VERSION 5.8 ;
BUSBITCHARS "[]" ;
DIVIDERCHAR "/" ;
UNITS
    DATABASE MICRONS 1000 ;
END UNITS

VIA ino_decode_predict_via1_2_1000_440_1_2_410_410
  VIARULE via1Array ;
  CUTSIZE 0.19 0.19 ;
  LAYERS Metal1 Via1 Metal2 ;
  CUTSPACING 0.22 0.22 ;
  ENCLOSURE 0.05 0.125 0.005 0.05 ;
  ROWCOL 1 2 ;
END ino_decode_predict_via1_2_1000_440_1_2_410_410

VIA ino_decode_predict_via2_3_1000_440_1_2_410_410
  VIARULE via2Array ;
  CUTSIZE 0.19 0.19 ;
  LAYERS Metal2 Via2 Metal3 ;
  CUTSPACING 0.22 0.22 ;
  ENCLOSURE 0.005 0.05 0.05 0.005 ;
  ROWCOL 1 2 ;
END ino_decode_predict_via2_3_1000_440_1_2_410_410

VIA ino_decode_predict_via3_4_1000_440_1_2_410_410
  VIARULE via3Array ;
  CUTSIZE 0.19 0.19 ;
  LAYERS Metal3 Via3 Metal4 ;
  CUTSPACING 0.22 0.22 ;
  ENCLOSURE 0.05 0.005 0.2 0.05 ;
  ROWCOL 1 2 ;
END ino_decode_predict_via3_4_1000_440_1_2_410_410

VIA ino_decode_predict_via4_5_1000_2000_1_1_840_840
  VIARULE viaTop1Array ;
  CUTSIZE 0.42 0.42 ;
  LAYERS Metal4 TopVia1 TopMetal1 ;
  CUTSPACING 0.42 0.42 ;
  ENCLOSURE 0.29 0.1 0.42 0.79 ;
END ino_decode_predict_via4_5_1000_2000_1_1_840_840

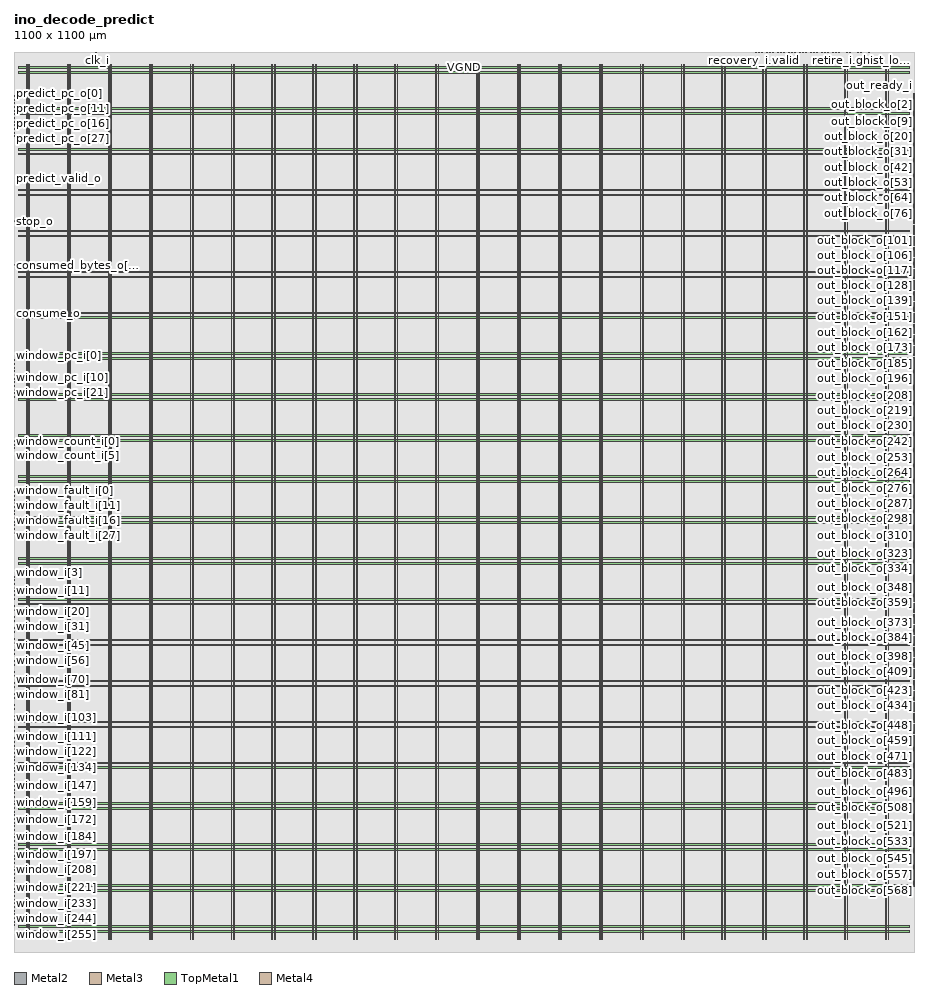
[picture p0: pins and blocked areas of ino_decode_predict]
MACRO ino_decode_predict
  FOREIGN ino_decode_predict 0 0 ;
  CLASS BLOCK ;
  SIZE 1100 BY 1100 ;
  PIN clk_i
    DIRECTION INPUT ;
    USE SIGNAL ;
    PORT
      LAYER Metal2 ;
        RECT  102.04 1099.6 102.44 1100 ;
    END
  END clk_i
  PIN consume_o
    DIRECTION OUTPUT ;
    USE SIGNAL ;
    PORT
      LAYER Metal3 ;
        RECT  0 780.58 0.4 780.98 ;
    END
  END consume_o
  PIN consumed_bytes_o[0]
    DIRECTION OUTPUT ;
    USE SIGNAL ;
    PORT
      LAYER Metal3 ;
        RECT  0 841.06 0.4 841.46 ;
    END
  END consumed_bytes_o[0]
  PIN consumed_bytes_o[1]
    DIRECTION OUTPUT ;
    USE SIGNAL ;
    PORT
      LAYER Metal3 ;
        RECT  0 839.38 0.4 839.78 ;
    END
  END consumed_bytes_o[1]
  PIN consumed_bytes_o[2]
    DIRECTION OUTPUT ;
    USE SIGNAL ;
    PORT
      LAYER Metal3 ;
        RECT  0 837.7 0.4 838.1 ;
    END
  END consumed_bytes_o[2]
  PIN consumed_bytes_o[3]
    DIRECTION OUTPUT ;
    USE SIGNAL ;
    PORT
      LAYER Metal3 ;
        RECT  0 836.02 0.4 836.42 ;
    END
  END consumed_bytes_o[3]
  PIN consumed_bytes_o[4]
    DIRECTION OUTPUT ;
    USE SIGNAL ;
    PORT
      LAYER Metal3 ;
        RECT  0 834.34 0.4 834.74 ;
    END
  END consumed_bytes_o[4]
  PIN consumed_bytes_o[5]
    DIRECTION OUTPUT ;
    USE SIGNAL ;
    PORT
      LAYER Metal3 ;
        RECT  0 832.66 0.4 833.06 ;
    END
  END consumed_bytes_o[5]
  PIN out_block_o[0]
    DIRECTION OUTPUT ;
    USE SIGNAL ;
    PORT
      LAYER Metal3 ;
        RECT  1099.6 1039.3 1100 1039.7 ;
    END
  END out_block_o[0]
  PIN out_block_o[100]
    DIRECTION OUTPUT ;
    USE SIGNAL ;
    PORT
      LAYER Metal3 ;
        RECT  1099.6 871.3 1100 871.7 ;
    END
  END out_block_o[100]
  PIN out_block_o[101]
    DIRECTION OUTPUT ;
    USE SIGNAL ;
    PORT
      LAYER Metal3 ;
        RECT  1099.6 869.62 1100 870.02 ;
    END
  END out_block_o[101]
  PIN out_block_o[102]
    DIRECTION OUTPUT ;
    USE SIGNAL ;
    PORT
      LAYER Metal3 ;
        RECT  1099.6 867.94 1100 868.34 ;
    END
  END out_block_o[102]
  PIN out_block_o[103]
    DIRECTION OUTPUT ;
    USE SIGNAL ;
    PORT
      LAYER Metal3 ;
        RECT  1099.6 866.26 1100 866.66 ;
    END
  END out_block_o[103]
  PIN out_block_o[104]
    DIRECTION OUTPUT ;
    USE SIGNAL ;
    PORT
      LAYER Metal3 ;
        RECT  1099.6 864.58 1100 864.98 ;
    END
  END out_block_o[104]
  PIN out_block_o[105]
    DIRECTION OUTPUT ;
    USE SIGNAL ;
    PORT
      LAYER Metal3 ;
        RECT  1099.6 862.9 1100 863.3 ;
    END
  END out_block_o[105]
  PIN out_block_o[106]
    DIRECTION OUTPUT ;
    USE SIGNAL ;
    PORT
      LAYER Metal3 ;
        RECT  1099.6 861.22 1100 861.62 ;
    END
  END out_block_o[106]
  PIN out_block_o[107]
    DIRECTION OUTPUT ;
    USE SIGNAL ;
    PORT
      LAYER Metal3 ;
        RECT  1099.6 859.54 1100 859.94 ;
    END
  END out_block_o[107]
  PIN out_block_o[108]
    DIRECTION OUTPUT ;
    USE SIGNAL ;
    PORT
      LAYER Metal3 ;
        RECT  1099.6 857.86 1100 858.26 ;
    END
  END out_block_o[108]
  PIN out_block_o[109]
    DIRECTION OUTPUT ;
    USE SIGNAL ;
    PORT
      LAYER Metal3 ;
        RECT  1099.6 856.18 1100 856.58 ;
    END
  END out_block_o[109]
  PIN out_block_o[10]
    DIRECTION OUTPUT ;
    USE SIGNAL ;
    PORT
      LAYER Metal3 ;
        RECT  1099.6 1022.5 1100 1022.9 ;
    END
  END out_block_o[10]
  PIN out_block_o[110]
    DIRECTION OUTPUT ;
    USE SIGNAL ;
    PORT
      LAYER Metal3 ;
        RECT  1099.6 854.5 1100 854.9 ;
    END
  END out_block_o[110]
  PIN out_block_o[111]
    DIRECTION OUTPUT ;
    USE SIGNAL ;
    PORT
      LAYER Metal3 ;
        RECT  1099.6 852.82 1100 853.22 ;
    END
  END out_block_o[111]
  PIN out_block_o[112]
    DIRECTION OUTPUT ;
    USE SIGNAL ;
    PORT
      LAYER Metal3 ;
        RECT  1099.6 851.14 1100 851.54 ;
    END
  END out_block_o[112]
  PIN out_block_o[113]
    DIRECTION OUTPUT ;
    USE SIGNAL ;
    PORT
      LAYER Metal3 ;
        RECT  1099.6 849.46 1100 849.86 ;
    END
  END out_block_o[113]
  PIN out_block_o[114]
    DIRECTION OUTPUT ;
    USE SIGNAL ;
    PORT
      LAYER Metal3 ;
        RECT  1099.6 847.78 1100 848.18 ;
    END
  END out_block_o[114]
  PIN out_block_o[115]
    DIRECTION OUTPUT ;
    USE SIGNAL ;
    PORT
      LAYER Metal3 ;
        RECT  1099.6 846.1 1100 846.5 ;
    END
  END out_block_o[115]
  PIN out_block_o[116]
    DIRECTION OUTPUT ;
    USE SIGNAL ;
    PORT
      LAYER Metal3 ;
        RECT  1099.6 844.42 1100 844.82 ;
    END
  END out_block_o[116]
  PIN out_block_o[117]
    DIRECTION OUTPUT ;
    USE SIGNAL ;
    PORT
      LAYER Metal3 ;
        RECT  1099.6 842.74 1100 843.14 ;
    END
  END out_block_o[117]
  PIN out_block_o[118]
    DIRECTION OUTPUT ;
    USE SIGNAL ;
    PORT
      LAYER Metal3 ;
        RECT  1099.6 841.06 1100 841.46 ;
    END
  END out_block_o[118]
  PIN out_block_o[119]
    DIRECTION OUTPUT ;
    USE SIGNAL ;
    PORT
      LAYER Metal3 ;
        RECT  1099.6 839.38 1100 839.78 ;
    END
  END out_block_o[119]
  PIN out_block_o[11]
    DIRECTION OUTPUT ;
    USE SIGNAL ;
    PORT
      LAYER Metal3 ;
        RECT  1099.6 1020.82 1100 1021.22 ;
    END
  END out_block_o[11]
  PIN out_block_o[120]
    DIRECTION OUTPUT ;
    USE SIGNAL ;
    PORT
      LAYER Metal3 ;
        RECT  1099.6 837.7 1100 838.1 ;
    END
  END out_block_o[120]
  PIN out_block_o[121]
    DIRECTION OUTPUT ;
    USE SIGNAL ;
    PORT
      LAYER Metal3 ;
        RECT  1099.6 836.02 1100 836.42 ;
    END
  END out_block_o[121]
  PIN out_block_o[122]
    DIRECTION OUTPUT ;
    USE SIGNAL ;
    PORT
      LAYER Metal3 ;
        RECT  1099.6 834.34 1100 834.74 ;
    END
  END out_block_o[122]
  PIN out_block_o[123]
    DIRECTION OUTPUT ;
    USE SIGNAL ;
    PORT
      LAYER Metal3 ;
        RECT  1099.6 832.66 1100 833.06 ;
    END
  END out_block_o[123]
  PIN out_block_o[124]
    DIRECTION OUTPUT ;
    USE SIGNAL ;
    PORT
      LAYER Metal3 ;
        RECT  1099.6 830.98 1100 831.38 ;
    END
  END out_block_o[124]
  PIN out_block_o[125]
    DIRECTION OUTPUT ;
    USE SIGNAL ;
    PORT
      LAYER Metal3 ;
        RECT  1099.6 829.3 1100 829.7 ;
    END
  END out_block_o[125]
  PIN out_block_o[126]
    DIRECTION OUTPUT ;
    USE SIGNAL ;
    PORT
      LAYER Metal3 ;
        RECT  1099.6 827.62 1100 828.02 ;
    END
  END out_block_o[126]
  PIN out_block_o[127]
    DIRECTION OUTPUT ;
    USE SIGNAL ;
    PORT
      LAYER Metal3 ;
        RECT  1099.6 825.94 1100 826.34 ;
    END
  END out_block_o[127]
  PIN out_block_o[128]
    DIRECTION OUTPUT ;
    USE SIGNAL ;
    PORT
      LAYER Metal3 ;
        RECT  1099.6 824.26 1100 824.66 ;
    END
  END out_block_o[128]
  PIN out_block_o[129]
    DIRECTION OUTPUT ;
    USE SIGNAL ;
    PORT
      LAYER Metal3 ;
        RECT  1099.6 822.58 1100 822.98 ;
    END
  END out_block_o[129]
  PIN out_block_o[12]
    DIRECTION OUTPUT ;
    USE SIGNAL ;
    PORT
      LAYER Metal3 ;
        RECT  1099.6 1019.14 1100 1019.54 ;
    END
  END out_block_o[12]
  PIN out_block_o[130]
    DIRECTION OUTPUT ;
    USE SIGNAL ;
    PORT
      LAYER Metal3 ;
        RECT  1099.6 820.9 1100 821.3 ;
    END
  END out_block_o[130]
  PIN out_block_o[131]
    DIRECTION OUTPUT ;
    USE SIGNAL ;
    PORT
      LAYER Metal3 ;
        RECT  1099.6 819.22 1100 819.62 ;
    END
  END out_block_o[131]
  PIN out_block_o[132]
    DIRECTION OUTPUT ;
    USE SIGNAL ;
    PORT
      LAYER Metal3 ;
        RECT  1099.6 817.54 1100 817.94 ;
    END
  END out_block_o[132]
  PIN out_block_o[133]
    DIRECTION OUTPUT ;
    USE SIGNAL ;
    PORT
      LAYER Metal3 ;
        RECT  1099.6 815.86 1100 816.26 ;
    END
  END out_block_o[133]
  PIN out_block_o[134]
    DIRECTION OUTPUT ;
    USE SIGNAL ;
    PORT
      LAYER Metal3 ;
        RECT  1099.6 814.18 1100 814.58 ;
    END
  END out_block_o[134]
  PIN out_block_o[135]
    DIRECTION OUTPUT ;
    USE SIGNAL ;
    PORT
      LAYER Metal3 ;
        RECT  1099.6 812.5 1100 812.9 ;
    END
  END out_block_o[135]
  PIN out_block_o[136]
    DIRECTION OUTPUT ;
    USE SIGNAL ;
    PORT
      LAYER Metal3 ;
        RECT  1099.6 810.82 1100 811.22 ;
    END
  END out_block_o[136]
  PIN out_block_o[137]
    DIRECTION OUTPUT ;
    USE SIGNAL ;
    PORT
      LAYER Metal3 ;
        RECT  1099.6 809.14 1100 809.54 ;
    END
  END out_block_o[137]
  PIN out_block_o[138]
    DIRECTION OUTPUT ;
    USE SIGNAL ;
    PORT
      LAYER Metal3 ;
        RECT  1099.6 807.46 1100 807.86 ;
    END
  END out_block_o[138]
  PIN out_block_o[139]
    DIRECTION OUTPUT ;
    USE SIGNAL ;
    PORT
      LAYER Metal3 ;
        RECT  1099.6 805.78 1100 806.18 ;
    END
  END out_block_o[139]
  PIN out_block_o[13]
    DIRECTION OUTPUT ;
    USE SIGNAL ;
    PORT
      LAYER Metal3 ;
        RECT  1099.6 1017.46 1100 1017.86 ;
    END
  END out_block_o[13]
  PIN out_block_o[140]
    DIRECTION OUTPUT ;
    USE SIGNAL ;
    PORT
      LAYER Metal3 ;
        RECT  1099.6 804.1 1100 804.5 ;
    END
  END out_block_o[140]
  PIN out_block_o[141]
    DIRECTION OUTPUT ;
    USE SIGNAL ;
    PORT
      LAYER Metal3 ;
        RECT  1099.6 802.42 1100 802.82 ;
    END
  END out_block_o[141]
  PIN out_block_o[142]
    DIRECTION OUTPUT ;
    USE SIGNAL ;
    PORT
      LAYER Metal3 ;
        RECT  1099.6 800.74 1100 801.14 ;
    END
  END out_block_o[142]
  PIN out_block_o[143]
    DIRECTION OUTPUT ;
    USE SIGNAL ;
    PORT
      LAYER Metal3 ;
        RECT  1099.6 799.06 1100 799.46 ;
    END
  END out_block_o[143]
  PIN out_block_o[144]
    DIRECTION OUTPUT ;
    USE SIGNAL ;
    PORT
      LAYER Metal3 ;
        RECT  1099.6 797.38 1100 797.78 ;
    END
  END out_block_o[144]
  PIN out_block_o[145]
    DIRECTION OUTPUT ;
    USE SIGNAL ;
    PORT
      LAYER Metal3 ;
        RECT  1099.6 795.7 1100 796.1 ;
    END
  END out_block_o[145]
  PIN out_block_o[146]
    DIRECTION OUTPUT ;
    USE SIGNAL ;
    PORT
      LAYER Metal3 ;
        RECT  1099.6 794.02 1100 794.42 ;
    END
  END out_block_o[146]
  PIN out_block_o[147]
    DIRECTION OUTPUT ;
    USE SIGNAL ;
    PORT
      LAYER Metal3 ;
        RECT  1099.6 792.34 1100 792.74 ;
    END
  END out_block_o[147]
  PIN out_block_o[148]
    DIRECTION OUTPUT ;
    USE SIGNAL ;
    PORT
      LAYER Metal3 ;
        RECT  1099.6 790.66 1100 791.06 ;
    END
  END out_block_o[148]
  PIN out_block_o[149]
    DIRECTION OUTPUT ;
    USE SIGNAL ;
    PORT
      LAYER Metal3 ;
        RECT  1099.6 788.98 1100 789.38 ;
    END
  END out_block_o[149]
  PIN out_block_o[14]
    DIRECTION OUTPUT ;
    USE SIGNAL ;
    PORT
      LAYER Metal3 ;
        RECT  1099.6 1015.78 1100 1016.18 ;
    END
  END out_block_o[14]
  PIN out_block_o[150]
    DIRECTION OUTPUT ;
    USE SIGNAL ;
    PORT
      LAYER Metal3 ;
        RECT  1099.6 787.3 1100 787.7 ;
    END
  END out_block_o[150]
  PIN out_block_o[151]
    DIRECTION OUTPUT ;
    USE SIGNAL ;
    PORT
      LAYER Metal3 ;
        RECT  1099.6 785.62 1100 786.02 ;
    END
  END out_block_o[151]
  PIN out_block_o[152]
    DIRECTION OUTPUT ;
    USE SIGNAL ;
    PORT
      LAYER Metal3 ;
        RECT  1099.6 783.94 1100 784.34 ;
    END
  END out_block_o[152]
  PIN out_block_o[153]
    DIRECTION OUTPUT ;
    USE SIGNAL ;
    PORT
      LAYER Metal3 ;
        RECT  1099.6 782.26 1100 782.66 ;
    END
  END out_block_o[153]
  PIN out_block_o[154]
    DIRECTION OUTPUT ;
    USE SIGNAL ;
    PORT
      LAYER Metal3 ;
        RECT  1099.6 780.58 1100 780.98 ;
    END
  END out_block_o[154]
  PIN out_block_o[155]
    DIRECTION OUTPUT ;
    USE SIGNAL ;
    PORT
      LAYER Metal3 ;
        RECT  1099.6 778.9 1100 779.3 ;
    END
  END out_block_o[155]
  PIN out_block_o[156]
    DIRECTION OUTPUT ;
    USE SIGNAL ;
    PORT
      LAYER Metal3 ;
        RECT  1099.6 777.22 1100 777.62 ;
    END
  END out_block_o[156]
  PIN out_block_o[157]
    DIRECTION OUTPUT ;
    USE SIGNAL ;
    PORT
      LAYER Metal3 ;
        RECT  1099.6 775.54 1100 775.94 ;
    END
  END out_block_o[157]
  PIN out_block_o[158]
    DIRECTION OUTPUT ;
    USE SIGNAL ;
    PORT
      LAYER Metal3 ;
        RECT  1099.6 773.86 1100 774.26 ;
    END
  END out_block_o[158]
  PIN out_block_o[159]
    DIRECTION OUTPUT ;
    USE SIGNAL ;
    PORT
      LAYER Metal3 ;
        RECT  1099.6 772.18 1100 772.58 ;
    END
  END out_block_o[159]
  PIN out_block_o[15]
    DIRECTION OUTPUT ;
    USE SIGNAL ;
    PORT
      LAYER Metal3 ;
        RECT  1099.6 1014.1 1100 1014.5 ;
    END
  END out_block_o[15]
  PIN out_block_o[160]
    DIRECTION OUTPUT ;
    USE SIGNAL ;
    PORT
      LAYER Metal3 ;
        RECT  1099.6 770.5 1100 770.9 ;
    END
  END out_block_o[160]
  PIN out_block_o[161]
    DIRECTION OUTPUT ;
    USE SIGNAL ;
    PORT
      LAYER Metal3 ;
        RECT  1099.6 768.82 1100 769.22 ;
    END
  END out_block_o[161]
  PIN out_block_o[162]
    DIRECTION OUTPUT ;
    USE SIGNAL ;
    PORT
      LAYER Metal3 ;
        RECT  1099.6 767.14 1100 767.54 ;
    END
  END out_block_o[162]
  PIN out_block_o[163]
    DIRECTION OUTPUT ;
    USE SIGNAL ;
    PORT
      LAYER Metal3 ;
        RECT  1099.6 765.46 1100 765.86 ;
    END
  END out_block_o[163]
  PIN out_block_o[164]
    DIRECTION OUTPUT ;
    USE SIGNAL ;
    PORT
      LAYER Metal3 ;
        RECT  1099.6 763.78 1100 764.18 ;
    END
  END out_block_o[164]
  PIN out_block_o[165]
    DIRECTION OUTPUT ;
    USE SIGNAL ;
    PORT
      LAYER Metal3 ;
        RECT  1099.6 762.1 1100 762.5 ;
    END
  END out_block_o[165]
  PIN out_block_o[166]
    DIRECTION OUTPUT ;
    USE SIGNAL ;
    PORT
      LAYER Metal3 ;
        RECT  1099.6 760.42 1100 760.82 ;
    END
  END out_block_o[166]
  PIN out_block_o[167]
    DIRECTION OUTPUT ;
    USE SIGNAL ;
    PORT
      LAYER Metal3 ;
        RECT  1099.6 758.74 1100 759.14 ;
    END
  END out_block_o[167]
  PIN out_block_o[168]
    DIRECTION OUTPUT ;
    USE SIGNAL ;
    PORT
      LAYER Metal3 ;
        RECT  1099.6 757.06 1100 757.46 ;
    END
  END out_block_o[168]
  PIN out_block_o[169]
    DIRECTION OUTPUT ;
    USE SIGNAL ;
    PORT
      LAYER Metal3 ;
        RECT  1099.6 755.38 1100 755.78 ;
    END
  END out_block_o[169]
  PIN out_block_o[16]
    DIRECTION OUTPUT ;
    USE SIGNAL ;
    PORT
      LAYER Metal3 ;
        RECT  1099.6 1012.42 1100 1012.82 ;
    END
  END out_block_o[16]
  PIN out_block_o[170]
    DIRECTION OUTPUT ;
    USE SIGNAL ;
    PORT
      LAYER Metal3 ;
        RECT  1099.6 753.7 1100 754.1 ;
    END
  END out_block_o[170]
  PIN out_block_o[171]
    DIRECTION OUTPUT ;
    USE SIGNAL ;
    PORT
      LAYER Metal3 ;
        RECT  1099.6 752.02 1100 752.42 ;
    END
  END out_block_o[171]
  PIN out_block_o[172]
    DIRECTION OUTPUT ;
    USE SIGNAL ;
    PORT
      LAYER Metal3 ;
        RECT  1099.6 750.34 1100 750.74 ;
    END
  END out_block_o[172]
  PIN out_block_o[173]
    DIRECTION OUTPUT ;
    USE SIGNAL ;
    PORT
      LAYER Metal3 ;
        RECT  1099.6 748.66 1100 749.06 ;
    END
  END out_block_o[173]
  PIN out_block_o[174]
    DIRECTION OUTPUT ;
    USE SIGNAL ;
    PORT
      LAYER Metal3 ;
        RECT  1099.6 746.98 1100 747.38 ;
    END
  END out_block_o[174]
  PIN out_block_o[175]
    DIRECTION OUTPUT ;
    USE SIGNAL ;
    PORT
      LAYER Metal3 ;
        RECT  1099.6 745.3 1100 745.7 ;
    END
  END out_block_o[175]
  PIN out_block_o[176]
    DIRECTION OUTPUT ;
    USE SIGNAL ;
    PORT
      LAYER Metal3 ;
        RECT  1099.6 743.62 1100 744.02 ;
    END
  END out_block_o[176]
  PIN out_block_o[177]
    DIRECTION OUTPUT ;
    USE SIGNAL ;
    PORT
      LAYER Metal3 ;
        RECT  1099.6 741.94 1100 742.34 ;
    END
  END out_block_o[177]
  PIN out_block_o[178]
    DIRECTION OUTPUT ;
    USE SIGNAL ;
    PORT
      LAYER Metal3 ;
        RECT  1099.6 740.26 1100 740.66 ;
    END
  END out_block_o[178]
  PIN out_block_o[179]
    DIRECTION OUTPUT ;
    USE SIGNAL ;
    PORT
      LAYER Metal3 ;
        RECT  1099.6 738.58 1100 738.98 ;
    END
  END out_block_o[179]
  PIN out_block_o[17]
    DIRECTION OUTPUT ;
    USE SIGNAL ;
    PORT
      LAYER Metal3 ;
        RECT  1099.6 1010.74 1100 1011.14 ;
    END
  END out_block_o[17]
  PIN out_block_o[180]
    DIRECTION OUTPUT ;
    USE SIGNAL ;
    PORT
      LAYER Metal3 ;
        RECT  1099.6 736.9 1100 737.3 ;
    END
  END out_block_o[180]
  PIN out_block_o[181]
    DIRECTION OUTPUT ;
    USE SIGNAL ;
    PORT
      LAYER Metal3 ;
        RECT  1099.6 735.22 1100 735.62 ;
    END
  END out_block_o[181]
  PIN out_block_o[182]
    DIRECTION OUTPUT ;
    USE SIGNAL ;
    PORT
      LAYER Metal3 ;
        RECT  1099.6 733.54 1100 733.94 ;
    END
  END out_block_o[182]
  PIN out_block_o[183]
    DIRECTION OUTPUT ;
    USE SIGNAL ;
    PORT
      LAYER Metal3 ;
        RECT  1099.6 731.86 1100 732.26 ;
    END
  END out_block_o[183]
  PIN out_block_o[184]
    DIRECTION OUTPUT ;
    USE SIGNAL ;
    PORT
      LAYER Metal3 ;
        RECT  1099.6 730.18 1100 730.58 ;
    END
  END out_block_o[184]
  PIN out_block_o[185]
    DIRECTION OUTPUT ;
    USE SIGNAL ;
    PORT
      LAYER Metal3 ;
        RECT  1099.6 728.5 1100 728.9 ;
    END
  END out_block_o[185]
  PIN out_block_o[186]
    DIRECTION OUTPUT ;
    USE SIGNAL ;
    PORT
      LAYER Metal3 ;
        RECT  1099.6 726.82 1100 727.22 ;
    END
  END out_block_o[186]
  PIN out_block_o[187]
    DIRECTION OUTPUT ;
    USE SIGNAL ;
    PORT
      LAYER Metal3 ;
        RECT  1099.6 725.14 1100 725.54 ;
    END
  END out_block_o[187]
  PIN out_block_o[188]
    DIRECTION OUTPUT ;
    USE SIGNAL ;
    PORT
      LAYER Metal3 ;
        RECT  1099.6 723.46 1100 723.86 ;
    END
  END out_block_o[188]
  PIN out_block_o[189]
    DIRECTION OUTPUT ;
    USE SIGNAL ;
    PORT
      LAYER Metal3 ;
        RECT  1099.6 721.78 1100 722.18 ;
    END
  END out_block_o[189]
  PIN out_block_o[18]
    DIRECTION OUTPUT ;
    USE SIGNAL ;
    PORT
      LAYER Metal3 ;
        RECT  1099.6 1009.06 1100 1009.46 ;
    END
  END out_block_o[18]
  PIN out_block_o[190]
    DIRECTION OUTPUT ;
    USE SIGNAL ;
    PORT
      LAYER Metal3 ;
        RECT  1099.6 720.1 1100 720.5 ;
    END
  END out_block_o[190]
  PIN out_block_o[191]
    DIRECTION OUTPUT ;
    USE SIGNAL ;
    PORT
      LAYER Metal3 ;
        RECT  1099.6 718.42 1100 718.82 ;
    END
  END out_block_o[191]
  PIN out_block_o[192]
    DIRECTION OUTPUT ;
    USE SIGNAL ;
    PORT
      LAYER Metal3 ;
        RECT  1099.6 716.74 1100 717.14 ;
    END
  END out_block_o[192]
  PIN out_block_o[193]
    DIRECTION OUTPUT ;
    USE SIGNAL ;
    PORT
      LAYER Metal3 ;
        RECT  1099.6 715.06 1100 715.46 ;
    END
  END out_block_o[193]
  PIN out_block_o[194]
    DIRECTION OUTPUT ;
    USE SIGNAL ;
    PORT
      LAYER Metal3 ;
        RECT  1099.6 713.38 1100 713.78 ;
    END
  END out_block_o[194]
  PIN out_block_o[195]
    DIRECTION OUTPUT ;
    USE SIGNAL ;
    PORT
      LAYER Metal3 ;
        RECT  1099.6 711.7 1100 712.1 ;
    END
  END out_block_o[195]
  PIN out_block_o[196]
    DIRECTION OUTPUT ;
    USE SIGNAL ;
    PORT
      LAYER Metal3 ;
        RECT  1099.6 710.02 1100 710.42 ;
    END
  END out_block_o[196]
  PIN out_block_o[197]
    DIRECTION OUTPUT ;
    USE SIGNAL ;
    PORT
      LAYER Metal3 ;
        RECT  1099.6 708.34 1100 708.74 ;
    END
  END out_block_o[197]
  PIN out_block_o[198]
    DIRECTION OUTPUT ;
    USE SIGNAL ;
    PORT
      LAYER Metal3 ;
        RECT  1099.6 706.66 1100 707.06 ;
    END
  END out_block_o[198]
  PIN out_block_o[199]
    DIRECTION OUTPUT ;
    USE SIGNAL ;
    PORT
      LAYER Metal3 ;
        RECT  1099.6 704.98 1100 705.38 ;
    END
  END out_block_o[199]
  PIN out_block_o[19]
    DIRECTION OUTPUT ;
    USE SIGNAL ;
    PORT
      LAYER Metal3 ;
        RECT  1099.6 1007.38 1100 1007.78 ;
    END
  END out_block_o[19]
  PIN out_block_o[1]
    DIRECTION OUTPUT ;
    USE SIGNAL ;
    PORT
      LAYER Metal3 ;
        RECT  1099.6 1037.62 1100 1038.02 ;
    END
  END out_block_o[1]
  PIN out_block_o[200]
    DIRECTION OUTPUT ;
    USE SIGNAL ;
    PORT
      LAYER Metal3 ;
        RECT  1099.6 703.3 1100 703.7 ;
    END
  END out_block_o[200]
  PIN out_block_o[201]
    DIRECTION OUTPUT ;
    USE SIGNAL ;
    PORT
      LAYER Metal3 ;
        RECT  1099.6 701.62 1100 702.02 ;
    END
  END out_block_o[201]
  PIN out_block_o[202]
    DIRECTION OUTPUT ;
    USE SIGNAL ;
    PORT
      LAYER Metal3 ;
        RECT  1099.6 699.94 1100 700.34 ;
    END
  END out_block_o[202]
  PIN out_block_o[203]
    DIRECTION OUTPUT ;
    USE SIGNAL ;
    PORT
      LAYER Metal3 ;
        RECT  1099.6 698.26 1100 698.66 ;
    END
  END out_block_o[203]
  PIN out_block_o[204]
    DIRECTION OUTPUT ;
    USE SIGNAL ;
    PORT
      LAYER Metal3 ;
        RECT  1099.6 696.58 1100 696.98 ;
    END
  END out_block_o[204]
  PIN out_block_o[205]
    DIRECTION OUTPUT ;
    USE SIGNAL ;
    PORT
      LAYER Metal3 ;
        RECT  1099.6 694.9 1100 695.3 ;
    END
  END out_block_o[205]
  PIN out_block_o[206]
    DIRECTION OUTPUT ;
    USE SIGNAL ;
    PORT
      LAYER Metal3 ;
        RECT  1099.6 693.22 1100 693.62 ;
    END
  END out_block_o[206]
  PIN out_block_o[207]
    DIRECTION OUTPUT ;
    USE SIGNAL ;
    PORT
      LAYER Metal3 ;
        RECT  1099.6 691.54 1100 691.94 ;
    END
  END out_block_o[207]
  PIN out_block_o[208]
    DIRECTION OUTPUT ;
    USE SIGNAL ;
    PORT
      LAYER Metal3 ;
        RECT  1099.6 689.86 1100 690.26 ;
    END
  END out_block_o[208]
  PIN out_block_o[209]
    DIRECTION OUTPUT ;
    USE SIGNAL ;
    PORT
      LAYER Metal3 ;
        RECT  1099.6 688.18 1100 688.58 ;
    END
  END out_block_o[209]
  PIN out_block_o[20]
    DIRECTION OUTPUT ;
    USE SIGNAL ;
    PORT
      LAYER Metal3 ;
        RECT  1099.6 1005.7 1100 1006.1 ;
    END
  END out_block_o[20]
  PIN out_block_o[210]
    DIRECTION OUTPUT ;
    USE SIGNAL ;
    PORT
      LAYER Metal3 ;
        RECT  1099.6 686.5 1100 686.9 ;
    END
  END out_block_o[210]
  PIN out_block_o[211]
    DIRECTION OUTPUT ;
    USE SIGNAL ;
    PORT
      LAYER Metal3 ;
        RECT  1099.6 684.82 1100 685.22 ;
    END
  END out_block_o[211]
  PIN out_block_o[212]
    DIRECTION OUTPUT ;
    USE SIGNAL ;
    PORT
      LAYER Metal3 ;
        RECT  1099.6 683.14 1100 683.54 ;
    END
  END out_block_o[212]
  PIN out_block_o[213]
    DIRECTION OUTPUT ;
    USE SIGNAL ;
    PORT
      LAYER Metal3 ;
        RECT  1099.6 681.46 1100 681.86 ;
    END
  END out_block_o[213]
  PIN out_block_o[214]
    DIRECTION OUTPUT ;
    USE SIGNAL ;
    PORT
      LAYER Metal3 ;
        RECT  1099.6 679.78 1100 680.18 ;
    END
  END out_block_o[214]
  PIN out_block_o[215]
    DIRECTION OUTPUT ;
    USE SIGNAL ;
    PORT
      LAYER Metal3 ;
        RECT  1099.6 678.1 1100 678.5 ;
    END
  END out_block_o[215]
  PIN out_block_o[216]
    DIRECTION OUTPUT ;
    USE SIGNAL ;
    PORT
      LAYER Metal3 ;
        RECT  1099.6 676.42 1100 676.82 ;
    END
  END out_block_o[216]
  PIN out_block_o[217]
    DIRECTION OUTPUT ;
    USE SIGNAL ;
    PORT
      LAYER Metal3 ;
        RECT  1099.6 674.74 1100 675.14 ;
    END
  END out_block_o[217]
  PIN out_block_o[218]
    DIRECTION OUTPUT ;
    USE SIGNAL ;
    PORT
      LAYER Metal3 ;
        RECT  1099.6 673.06 1100 673.46 ;
    END
  END out_block_o[218]
  PIN out_block_o[219]
    DIRECTION OUTPUT ;
    USE SIGNAL ;
    PORT
      LAYER Metal3 ;
        RECT  1099.6 671.38 1100 671.78 ;
    END
  END out_block_o[219]
  PIN out_block_o[21]
    DIRECTION OUTPUT ;
    USE SIGNAL ;
    PORT
      LAYER Metal3 ;
        RECT  1099.6 1004.02 1100 1004.42 ;
    END
  END out_block_o[21]
  PIN out_block_o[220]
    DIRECTION OUTPUT ;
    USE SIGNAL ;
    PORT
      LAYER Metal3 ;
        RECT  1099.6 669.7 1100 670.1 ;
    END
  END out_block_o[220]
  PIN out_block_o[221]
    DIRECTION OUTPUT ;
    USE SIGNAL ;
    PORT
      LAYER Metal3 ;
        RECT  1099.6 668.02 1100 668.42 ;
    END
  END out_block_o[221]
  PIN out_block_o[222]
    DIRECTION OUTPUT ;
    USE SIGNAL ;
    PORT
      LAYER Metal3 ;
        RECT  1099.6 666.34 1100 666.74 ;
    END
  END out_block_o[222]
  PIN out_block_o[223]
    DIRECTION OUTPUT ;
    USE SIGNAL ;
    PORT
      LAYER Metal3 ;
        RECT  1099.6 664.66 1100 665.06 ;
    END
  END out_block_o[223]
  PIN out_block_o[224]
    DIRECTION OUTPUT ;
    USE SIGNAL ;
    PORT
      LAYER Metal3 ;
        RECT  1099.6 662.98 1100 663.38 ;
    END
  END out_block_o[224]
  PIN out_block_o[225]
    DIRECTION OUTPUT ;
    USE SIGNAL ;
    PORT
      LAYER Metal3 ;
        RECT  1099.6 661.3 1100 661.7 ;
    END
  END out_block_o[225]
  PIN out_block_o[226]
    DIRECTION OUTPUT ;
    USE SIGNAL ;
    PORT
      LAYER Metal3 ;
        RECT  1099.6 659.62 1100 660.02 ;
    END
  END out_block_o[226]
  PIN out_block_o[227]
    DIRECTION OUTPUT ;
    USE SIGNAL ;
    PORT
      LAYER Metal3 ;
        RECT  1099.6 657.94 1100 658.34 ;
    END
  END out_block_o[227]
  PIN out_block_o[228]
    DIRECTION OUTPUT ;
    USE SIGNAL ;
    PORT
      LAYER Metal3 ;
        RECT  1099.6 656.26 1100 656.66 ;
    END
  END out_block_o[228]
  PIN out_block_o[229]
    DIRECTION OUTPUT ;
    USE SIGNAL ;
    PORT
      LAYER Metal3 ;
        RECT  1099.6 654.58 1100 654.98 ;
    END
  END out_block_o[229]
  PIN out_block_o[22]
    DIRECTION OUTPUT ;
    USE SIGNAL ;
    PORT
      LAYER Metal3 ;
        RECT  1099.6 1002.34 1100 1002.74 ;
    END
  END out_block_o[22]
  PIN out_block_o[230]
    DIRECTION OUTPUT ;
    USE SIGNAL ;
    PORT
      LAYER Metal3 ;
        RECT  1099.6 652.9 1100 653.3 ;
    END
  END out_block_o[230]
  PIN out_block_o[231]
    DIRECTION OUTPUT ;
    USE SIGNAL ;
    PORT
      LAYER Metal3 ;
        RECT  1099.6 651.22 1100 651.62 ;
    END
  END out_block_o[231]
  PIN out_block_o[232]
    DIRECTION OUTPUT ;
    USE SIGNAL ;
    PORT
      LAYER Metal3 ;
        RECT  1099.6 649.54 1100 649.94 ;
    END
  END out_block_o[232]
  PIN out_block_o[233]
    DIRECTION OUTPUT ;
    USE SIGNAL ;
    PORT
      LAYER Metal3 ;
        RECT  1099.6 647.86 1100 648.26 ;
    END
  END out_block_o[233]
  PIN out_block_o[234]
    DIRECTION OUTPUT ;
    USE SIGNAL ;
    PORT
      LAYER Metal3 ;
        RECT  1099.6 646.18 1100 646.58 ;
    END
  END out_block_o[234]
  PIN out_block_o[235]
    DIRECTION OUTPUT ;
    USE SIGNAL ;
    PORT
      LAYER Metal3 ;
        RECT  1099.6 644.5 1100 644.9 ;
    END
  END out_block_o[235]
  PIN out_block_o[236]
    DIRECTION OUTPUT ;
    USE SIGNAL ;
    PORT
      LAYER Metal3 ;
        RECT  1099.6 642.82 1100 643.22 ;
    END
  END out_block_o[236]
  PIN out_block_o[237]
    DIRECTION OUTPUT ;
    USE SIGNAL ;
    PORT
      LAYER Metal3 ;
        RECT  1099.6 641.14 1100 641.54 ;
    END
  END out_block_o[237]
  PIN out_block_o[238]
    DIRECTION OUTPUT ;
    USE SIGNAL ;
    PORT
      LAYER Metal3 ;
        RECT  1099.6 639.46 1100 639.86 ;
    END
  END out_block_o[238]
  PIN out_block_o[239]
    DIRECTION OUTPUT ;
    USE SIGNAL ;
    PORT
      LAYER Metal3 ;
        RECT  1099.6 637.78 1100 638.18 ;
    END
  END out_block_o[239]
  PIN out_block_o[23]
    DIRECTION OUTPUT ;
    USE SIGNAL ;
    PORT
      LAYER Metal3 ;
        RECT  1099.6 1000.66 1100 1001.06 ;
    END
  END out_block_o[23]
  PIN out_block_o[240]
    DIRECTION OUTPUT ;
    USE SIGNAL ;
    PORT
      LAYER Metal3 ;
        RECT  1099.6 636.1 1100 636.5 ;
    END
  END out_block_o[240]
  PIN out_block_o[241]
    DIRECTION OUTPUT ;
    USE SIGNAL ;
    PORT
      LAYER Metal3 ;
        RECT  1099.6 634.42 1100 634.82 ;
    END
  END out_block_o[241]
  PIN out_block_o[242]
    DIRECTION OUTPUT ;
    USE SIGNAL ;
    PORT
      LAYER Metal3 ;
        RECT  1099.6 632.74 1100 633.14 ;
    END
  END out_block_o[242]
  PIN out_block_o[243]
    DIRECTION OUTPUT ;
    USE SIGNAL ;
    PORT
      LAYER Metal3 ;
        RECT  1099.6 631.06 1100 631.46 ;
    END
  END out_block_o[243]
  PIN out_block_o[244]
    DIRECTION OUTPUT ;
    USE SIGNAL ;
    PORT
      LAYER Metal3 ;
        RECT  1099.6 629.38 1100 629.78 ;
    END
  END out_block_o[244]
  PIN out_block_o[245]
    DIRECTION OUTPUT ;
    USE SIGNAL ;
    PORT
      LAYER Metal3 ;
        RECT  1099.6 627.7 1100 628.1 ;
    END
  END out_block_o[245]
  PIN out_block_o[246]
    DIRECTION OUTPUT ;
    USE SIGNAL ;
    PORT
      LAYER Metal3 ;
        RECT  1099.6 626.02 1100 626.42 ;
    END
  END out_block_o[246]
  PIN out_block_o[247]
    DIRECTION OUTPUT ;
    USE SIGNAL ;
    PORT
      LAYER Metal3 ;
        RECT  1099.6 624.34 1100 624.74 ;
    END
  END out_block_o[247]
  PIN out_block_o[248]
    DIRECTION OUTPUT ;
    USE SIGNAL ;
    PORT
      LAYER Metal3 ;
        RECT  1099.6 622.66 1100 623.06 ;
    END
  END out_block_o[248]
  PIN out_block_o[249]
    DIRECTION OUTPUT ;
    USE SIGNAL ;
    PORT
      LAYER Metal3 ;
        RECT  1099.6 620.98 1100 621.38 ;
    END
  END out_block_o[249]
  PIN out_block_o[24]
    DIRECTION OUTPUT ;
    USE SIGNAL ;
    PORT
      LAYER Metal3 ;
        RECT  1099.6 998.98 1100 999.38 ;
    END
  END out_block_o[24]
  PIN out_block_o[250]
    DIRECTION OUTPUT ;
    USE SIGNAL ;
    PORT
      LAYER Metal3 ;
        RECT  1099.6 619.3 1100 619.7 ;
    END
  END out_block_o[250]
  PIN out_block_o[251]
    DIRECTION OUTPUT ;
    USE SIGNAL ;
    PORT
      LAYER Metal3 ;
        RECT  1099.6 617.62 1100 618.02 ;
    END
  END out_block_o[251]
  PIN out_block_o[252]
    DIRECTION OUTPUT ;
    USE SIGNAL ;
    PORT
      LAYER Metal3 ;
        RECT  1099.6 615.94 1100 616.34 ;
    END
  END out_block_o[252]
  PIN out_block_o[253]
    DIRECTION OUTPUT ;
    USE SIGNAL ;
    PORT
      LAYER Metal3 ;
        RECT  1099.6 614.26 1100 614.66 ;
    END
  END out_block_o[253]
  PIN out_block_o[254]
    DIRECTION OUTPUT ;
    USE SIGNAL ;
    PORT
      LAYER Metal3 ;
        RECT  1099.6 612.58 1100 612.98 ;
    END
  END out_block_o[254]
  PIN out_block_o[255]
    DIRECTION OUTPUT ;
    USE SIGNAL ;
    PORT
      LAYER Metal3 ;
        RECT  1099.6 610.9 1100 611.3 ;
    END
  END out_block_o[255]
  PIN out_block_o[256]
    DIRECTION OUTPUT ;
    USE SIGNAL ;
    PORT
      LAYER Metal3 ;
        RECT  1099.6 609.22 1100 609.62 ;
    END
  END out_block_o[256]
  PIN out_block_o[257]
    DIRECTION OUTPUT ;
    USE SIGNAL ;
    PORT
      LAYER Metal3 ;
        RECT  1099.6 607.54 1100 607.94 ;
    END
  END out_block_o[257]
  PIN out_block_o[258]
    DIRECTION OUTPUT ;
    USE SIGNAL ;
    PORT
      LAYER Metal3 ;
        RECT  1099.6 605.86 1100 606.26 ;
    END
  END out_block_o[258]
  PIN out_block_o[259]
    DIRECTION OUTPUT ;
    USE SIGNAL ;
    PORT
      LAYER Metal3 ;
        RECT  1099.6 604.18 1100 604.58 ;
    END
  END out_block_o[259]
  PIN out_block_o[25]
    DIRECTION OUTPUT ;
    USE SIGNAL ;
    PORT
      LAYER Metal3 ;
        RECT  1099.6 997.3 1100 997.7 ;
    END
  END out_block_o[25]
  PIN out_block_o[260]
    DIRECTION OUTPUT ;
    USE SIGNAL ;
    PORT
      LAYER Metal3 ;
        RECT  1099.6 602.5 1100 602.9 ;
    END
  END out_block_o[260]
  PIN out_block_o[261]
    DIRECTION OUTPUT ;
    USE SIGNAL ;
    PORT
      LAYER Metal3 ;
        RECT  1099.6 600.82 1100 601.22 ;
    END
  END out_block_o[261]
  PIN out_block_o[262]
    DIRECTION OUTPUT ;
    USE SIGNAL ;
    PORT
      LAYER Metal3 ;
        RECT  1099.6 599.14 1100 599.54 ;
    END
  END out_block_o[262]
  PIN out_block_o[263]
    DIRECTION OUTPUT ;
    USE SIGNAL ;
    PORT
      LAYER Metal3 ;
        RECT  1099.6 597.46 1100 597.86 ;
    END
  END out_block_o[263]
  PIN out_block_o[264]
    DIRECTION OUTPUT ;
    USE SIGNAL ;
    PORT
      LAYER Metal3 ;
        RECT  1099.6 595.78 1100 596.18 ;
    END
  END out_block_o[264]
  PIN out_block_o[265]
    DIRECTION OUTPUT ;
    USE SIGNAL ;
    PORT
      LAYER Metal3 ;
        RECT  1099.6 594.1 1100 594.5 ;
    END
  END out_block_o[265]
  PIN out_block_o[266]
    DIRECTION OUTPUT ;
    USE SIGNAL ;
    PORT
      LAYER Metal3 ;
        RECT  1099.6 592.42 1100 592.82 ;
    END
  END out_block_o[266]
  PIN out_block_o[267]
    DIRECTION OUTPUT ;
    USE SIGNAL ;
    PORT
      LAYER Metal3 ;
        RECT  1099.6 590.74 1100 591.14 ;
    END
  END out_block_o[267]
  PIN out_block_o[268]
    DIRECTION OUTPUT ;
    USE SIGNAL ;
    PORT
      LAYER Metal3 ;
        RECT  1099.6 589.06 1100 589.46 ;
    END
  END out_block_o[268]
  PIN out_block_o[269]
    DIRECTION OUTPUT ;
    USE SIGNAL ;
    PORT
      LAYER Metal3 ;
        RECT  1099.6 587.38 1100 587.78 ;
    END
  END out_block_o[269]
  PIN out_block_o[26]
    DIRECTION OUTPUT ;
    USE SIGNAL ;
    PORT
      LAYER Metal3 ;
        RECT  1099.6 995.62 1100 996.02 ;
    END
  END out_block_o[26]
  PIN out_block_o[270]
    DIRECTION OUTPUT ;
    USE SIGNAL ;
    PORT
      LAYER Metal3 ;
        RECT  1099.6 585.7 1100 586.1 ;
    END
  END out_block_o[270]
  PIN out_block_o[271]
    DIRECTION OUTPUT ;
    USE SIGNAL ;
    PORT
      LAYER Metal3 ;
        RECT  1099.6 584.02 1100 584.42 ;
    END
  END out_block_o[271]
  PIN out_block_o[272]
    DIRECTION OUTPUT ;
    USE SIGNAL ;
    PORT
      LAYER Metal3 ;
        RECT  1099.6 582.34 1100 582.74 ;
    END
  END out_block_o[272]
  PIN out_block_o[273]
    DIRECTION OUTPUT ;
    USE SIGNAL ;
    PORT
      LAYER Metal3 ;
        RECT  1099.6 580.66 1100 581.06 ;
    END
  END out_block_o[273]
  PIN out_block_o[274]
    DIRECTION OUTPUT ;
    USE SIGNAL ;
    PORT
      LAYER Metal3 ;
        RECT  1099.6 578.98 1100 579.38 ;
    END
  END out_block_o[274]
  PIN out_block_o[275]
    DIRECTION OUTPUT ;
    USE SIGNAL ;
    PORT
      LAYER Metal3 ;
        RECT  1099.6 577.3 1100 577.7 ;
    END
  END out_block_o[275]
  PIN out_block_o[276]
    DIRECTION OUTPUT ;
    USE SIGNAL ;
    PORT
      LAYER Metal3 ;
        RECT  1099.6 575.62 1100 576.02 ;
    END
  END out_block_o[276]
  PIN out_block_o[277]
    DIRECTION OUTPUT ;
    USE SIGNAL ;
    PORT
      LAYER Metal3 ;
        RECT  1099.6 573.94 1100 574.34 ;
    END
  END out_block_o[277]
  PIN out_block_o[278]
    DIRECTION OUTPUT ;
    USE SIGNAL ;
    PORT
      LAYER Metal3 ;
        RECT  1099.6 572.26 1100 572.66 ;
    END
  END out_block_o[278]
  PIN out_block_o[279]
    DIRECTION OUTPUT ;
    USE SIGNAL ;
    PORT
      LAYER Metal3 ;
        RECT  1099.6 570.58 1100 570.98 ;
    END
  END out_block_o[279]
  PIN out_block_o[27]
    DIRECTION OUTPUT ;
    USE SIGNAL ;
    PORT
      LAYER Metal3 ;
        RECT  1099.6 993.94 1100 994.34 ;
    END
  END out_block_o[27]
  PIN out_block_o[280]
    DIRECTION OUTPUT ;
    USE SIGNAL ;
    PORT
      LAYER Metal3 ;
        RECT  1099.6 568.9 1100 569.3 ;
    END
  END out_block_o[280]
  PIN out_block_o[281]
    DIRECTION OUTPUT ;
    USE SIGNAL ;
    PORT
      LAYER Metal3 ;
        RECT  1099.6 567.22 1100 567.62 ;
    END
  END out_block_o[281]
  PIN out_block_o[282]
    DIRECTION OUTPUT ;
    USE SIGNAL ;
    PORT
      LAYER Metal3 ;
        RECT  1099.6 565.54 1100 565.94 ;
    END
  END out_block_o[282]
  PIN out_block_o[283]
    DIRECTION OUTPUT ;
    USE SIGNAL ;
    PORT
      LAYER Metal3 ;
        RECT  1099.6 563.86 1100 564.26 ;
    END
  END out_block_o[283]
  PIN out_block_o[284]
    DIRECTION OUTPUT ;
    USE SIGNAL ;
    PORT
      LAYER Metal3 ;
        RECT  1099.6 562.18 1100 562.58 ;
    END
  END out_block_o[284]
  PIN out_block_o[285]
    DIRECTION OUTPUT ;
    USE SIGNAL ;
    PORT
      LAYER Metal3 ;
        RECT  1099.6 560.5 1100 560.9 ;
    END
  END out_block_o[285]
  PIN out_block_o[286]
    DIRECTION OUTPUT ;
    USE SIGNAL ;
    PORT
      LAYER Metal3 ;
        RECT  1099.6 558.82 1100 559.22 ;
    END
  END out_block_o[286]
  PIN out_block_o[287]
    DIRECTION OUTPUT ;
    USE SIGNAL ;
    PORT
      LAYER Metal3 ;
        RECT  1099.6 557.14 1100 557.54 ;
    END
  END out_block_o[287]
  PIN out_block_o[288]
    DIRECTION OUTPUT ;
    USE SIGNAL ;
    PORT
      LAYER Metal3 ;
        RECT  1099.6 555.46 1100 555.86 ;
    END
  END out_block_o[288]
  PIN out_block_o[289]
    DIRECTION OUTPUT ;
    USE SIGNAL ;
    PORT
      LAYER Metal3 ;
        RECT  1099.6 553.78 1100 554.18 ;
    END
  END out_block_o[289]
  PIN out_block_o[28]
    DIRECTION OUTPUT ;
    USE SIGNAL ;
    PORT
      LAYER Metal3 ;
        RECT  1099.6 992.26 1100 992.66 ;
    END
  END out_block_o[28]
  PIN out_block_o[290]
    DIRECTION OUTPUT ;
    USE SIGNAL ;
    PORT
      LAYER Metal3 ;
        RECT  1099.6 552.1 1100 552.5 ;
    END
  END out_block_o[290]
  PIN out_block_o[291]
    DIRECTION OUTPUT ;
    USE SIGNAL ;
    PORT
      LAYER Metal3 ;
        RECT  1099.6 550.42 1100 550.82 ;
    END
  END out_block_o[291]
  PIN out_block_o[292]
    DIRECTION OUTPUT ;
    USE SIGNAL ;
    PORT
      LAYER Metal3 ;
        RECT  1099.6 548.74 1100 549.14 ;
    END
  END out_block_o[292]
  PIN out_block_o[293]
    DIRECTION OUTPUT ;
    USE SIGNAL ;
    PORT
      LAYER Metal3 ;
        RECT  1099.6 547.06 1100 547.46 ;
    END
  END out_block_o[293]
  PIN out_block_o[294]
    DIRECTION OUTPUT ;
    USE SIGNAL ;
    PORT
      LAYER Metal3 ;
        RECT  1099.6 545.38 1100 545.78 ;
    END
  END out_block_o[294]
  PIN out_block_o[295]
    DIRECTION OUTPUT ;
    USE SIGNAL ;
    PORT
      LAYER Metal3 ;
        RECT  1099.6 543.7 1100 544.1 ;
    END
  END out_block_o[295]
  PIN out_block_o[296]
    DIRECTION OUTPUT ;
    USE SIGNAL ;
    PORT
      LAYER Metal3 ;
        RECT  1099.6 542.02 1100 542.42 ;
    END
  END out_block_o[296]
  PIN out_block_o[297]
    DIRECTION OUTPUT ;
    USE SIGNAL ;
    PORT
      LAYER Metal3 ;
        RECT  1099.6 540.34 1100 540.74 ;
    END
  END out_block_o[297]
  PIN out_block_o[298]
    DIRECTION OUTPUT ;
    USE SIGNAL ;
    PORT
      LAYER Metal3 ;
        RECT  1099.6 538.66 1100 539.06 ;
    END
  END out_block_o[298]
  PIN out_block_o[299]
    DIRECTION OUTPUT ;
    USE SIGNAL ;
    PORT
      LAYER Metal3 ;
        RECT  1099.6 536.98 1100 537.38 ;
    END
  END out_block_o[299]
  PIN out_block_o[29]
    DIRECTION OUTPUT ;
    USE SIGNAL ;
    PORT
      LAYER Metal3 ;
        RECT  1099.6 990.58 1100 990.98 ;
    END
  END out_block_o[29]
  PIN out_block_o[2]
    DIRECTION OUTPUT ;
    USE SIGNAL ;
    PORT
      LAYER Metal3 ;
        RECT  1099.6 1035.94 1100 1036.34 ;
    END
  END out_block_o[2]
  PIN out_block_o[300]
    DIRECTION OUTPUT ;
    USE SIGNAL ;
    PORT
      LAYER Metal3 ;
        RECT  1099.6 535.3 1100 535.7 ;
    END
  END out_block_o[300]
  PIN out_block_o[301]
    DIRECTION OUTPUT ;
    USE SIGNAL ;
    PORT
      LAYER Metal3 ;
        RECT  1099.6 533.62 1100 534.02 ;
    END
  END out_block_o[301]
  PIN out_block_o[302]
    DIRECTION OUTPUT ;
    USE SIGNAL ;
    PORT
      LAYER Metal3 ;
        RECT  1099.6 531.94 1100 532.34 ;
    END
  END out_block_o[302]
  PIN out_block_o[303]
    DIRECTION OUTPUT ;
    USE SIGNAL ;
    PORT
      LAYER Metal3 ;
        RECT  1099.6 530.26 1100 530.66 ;
    END
  END out_block_o[303]
  PIN out_block_o[304]
    DIRECTION OUTPUT ;
    USE SIGNAL ;
    PORT
      LAYER Metal3 ;
        RECT  1099.6 528.58 1100 528.98 ;
    END
  END out_block_o[304]
  PIN out_block_o[305]
    DIRECTION OUTPUT ;
    USE SIGNAL ;
    PORT
      LAYER Metal3 ;
        RECT  1099.6 526.9 1100 527.3 ;
    END
  END out_block_o[305]
  PIN out_block_o[306]
    DIRECTION OUTPUT ;
    USE SIGNAL ;
    PORT
      LAYER Metal3 ;
        RECT  1099.6 525.22 1100 525.62 ;
    END
  END out_block_o[306]
  PIN out_block_o[307]
    DIRECTION OUTPUT ;
    USE SIGNAL ;
    PORT
      LAYER Metal3 ;
        RECT  1099.6 523.54 1100 523.94 ;
    END
  END out_block_o[307]
  PIN out_block_o[308]
    DIRECTION OUTPUT ;
    USE SIGNAL ;
    PORT
      LAYER Metal3 ;
        RECT  1099.6 521.86 1100 522.26 ;
    END
  END out_block_o[308]
  PIN out_block_o[309]
    DIRECTION OUTPUT ;
    USE SIGNAL ;
    PORT
      LAYER Metal3 ;
        RECT  1099.6 520.18 1100 520.58 ;
    END
  END out_block_o[309]
  PIN out_block_o[30]
    DIRECTION OUTPUT ;
    USE SIGNAL ;
    PORT
      LAYER Metal3 ;
        RECT  1099.6 988.9 1100 989.3 ;
    END
  END out_block_o[30]
  PIN out_block_o[310]
    DIRECTION OUTPUT ;
    USE SIGNAL ;
    PORT
      LAYER Metal3 ;
        RECT  1099.6 518.5 1100 518.9 ;
    END
  END out_block_o[310]
  PIN out_block_o[311]
    DIRECTION OUTPUT ;
    USE SIGNAL ;
    PORT
      LAYER Metal3 ;
        RECT  1099.6 516.82 1100 517.22 ;
    END
  END out_block_o[311]
  PIN out_block_o[312]
    DIRECTION OUTPUT ;
    USE SIGNAL ;
    PORT
      LAYER Metal3 ;
        RECT  1099.6 515.14 1100 515.54 ;
    END
  END out_block_o[312]
  PIN out_block_o[313]
    DIRECTION OUTPUT ;
    USE SIGNAL ;
    PORT
      LAYER Metal3 ;
        RECT  1099.6 513.46 1100 513.86 ;
    END
  END out_block_o[313]
  PIN out_block_o[314]
    DIRECTION OUTPUT ;
    USE SIGNAL ;
    PORT
      LAYER Metal3 ;
        RECT  1099.6 511.78 1100 512.18 ;
    END
  END out_block_o[314]
  PIN out_block_o[315]
    DIRECTION OUTPUT ;
    USE SIGNAL ;
    PORT
      LAYER Metal3 ;
        RECT  1099.6 510.1 1100 510.5 ;
    END
  END out_block_o[315]
  PIN out_block_o[316]
    DIRECTION OUTPUT ;
    USE SIGNAL ;
    PORT
      LAYER Metal3 ;
        RECT  1099.6 508.42 1100 508.82 ;
    END
  END out_block_o[316]
  PIN out_block_o[317]
    DIRECTION OUTPUT ;
    USE SIGNAL ;
    PORT
      LAYER Metal3 ;
        RECT  1099.6 506.74 1100 507.14 ;
    END
  END out_block_o[317]
  PIN out_block_o[318]
    DIRECTION OUTPUT ;
    USE SIGNAL ;
    PORT
      LAYER Metal3 ;
        RECT  1099.6 505.06 1100 505.46 ;
    END
  END out_block_o[318]
  PIN out_block_o[319]
    DIRECTION OUTPUT ;
    USE SIGNAL ;
    PORT
      LAYER Metal3 ;
        RECT  1099.6 503.38 1100 503.78 ;
    END
  END out_block_o[319]
  PIN out_block_o[31]
    DIRECTION OUTPUT ;
    USE SIGNAL ;
    PORT
      LAYER Metal3 ;
        RECT  1099.6 987.22 1100 987.62 ;
    END
  END out_block_o[31]
  PIN out_block_o[320]
    DIRECTION OUTPUT ;
    USE SIGNAL ;
    PORT
      LAYER Metal3 ;
        RECT  1099.6 501.7 1100 502.1 ;
    END
  END out_block_o[320]
  PIN out_block_o[321]
    DIRECTION OUTPUT ;
    USE SIGNAL ;
    PORT
      LAYER Metal3 ;
        RECT  1099.6 500.02 1100 500.42 ;
    END
  END out_block_o[321]
  PIN out_block_o[322]
    DIRECTION OUTPUT ;
    USE SIGNAL ;
    PORT
      LAYER Metal3 ;
        RECT  1099.6 498.34 1100 498.74 ;
    END
  END out_block_o[322]
  PIN out_block_o[323]
    DIRECTION OUTPUT ;
    USE SIGNAL ;
    PORT
      LAYER Metal3 ;
        RECT  1099.6 496.66 1100 497.06 ;
    END
  END out_block_o[323]
  PIN out_block_o[324]
    DIRECTION OUTPUT ;
    USE SIGNAL ;
    PORT
      LAYER Metal3 ;
        RECT  1099.6 494.98 1100 495.38 ;
    END
  END out_block_o[324]
  PIN out_block_o[325]
    DIRECTION OUTPUT ;
    USE SIGNAL ;
    PORT
      LAYER Metal3 ;
        RECT  1099.6 493.3 1100 493.7 ;
    END
  END out_block_o[325]
  PIN out_block_o[326]
    DIRECTION OUTPUT ;
    USE SIGNAL ;
    PORT
      LAYER Metal3 ;
        RECT  1099.6 491.62 1100 492.02 ;
    END
  END out_block_o[326]
  PIN out_block_o[327]
    DIRECTION OUTPUT ;
    USE SIGNAL ;
    PORT
      LAYER Metal3 ;
        RECT  1099.6 489.94 1100 490.34 ;
    END
  END out_block_o[327]
  PIN out_block_o[328]
    DIRECTION OUTPUT ;
    USE SIGNAL ;
    PORT
      LAYER Metal3 ;
        RECT  1099.6 488.26 1100 488.66 ;
    END
  END out_block_o[328]
  PIN out_block_o[329]
    DIRECTION OUTPUT ;
    USE SIGNAL ;
    PORT
      LAYER Metal3 ;
        RECT  1099.6 486.58 1100 486.98 ;
    END
  END out_block_o[329]
  PIN out_block_o[32]
    DIRECTION OUTPUT ;
    USE SIGNAL ;
    PORT
      LAYER Metal3 ;
        RECT  1099.6 985.54 1100 985.94 ;
    END
  END out_block_o[32]
  PIN out_block_o[330]
    DIRECTION OUTPUT ;
    USE SIGNAL ;
    PORT
      LAYER Metal3 ;
        RECT  1099.6 484.9 1100 485.3 ;
    END
  END out_block_o[330]
  PIN out_block_o[331]
    DIRECTION OUTPUT ;
    USE SIGNAL ;
    PORT
      LAYER Metal3 ;
        RECT  1099.6 483.22 1100 483.62 ;
    END
  END out_block_o[331]
  PIN out_block_o[332]
    DIRECTION OUTPUT ;
    USE SIGNAL ;
    PORT
      LAYER Metal3 ;
        RECT  1099.6 481.54 1100 481.94 ;
    END
  END out_block_o[332]
  PIN out_block_o[333]
    DIRECTION OUTPUT ;
    USE SIGNAL ;
    PORT
      LAYER Metal3 ;
        RECT  1099.6 479.86 1100 480.26 ;
    END
  END out_block_o[333]
  PIN out_block_o[334]
    DIRECTION OUTPUT ;
    USE SIGNAL ;
    PORT
      LAYER Metal3 ;
        RECT  1099.6 478.18 1100 478.58 ;
    END
  END out_block_o[334]
  PIN out_block_o[335]
    DIRECTION OUTPUT ;
    USE SIGNAL ;
    PORT
      LAYER Metal3 ;
        RECT  1099.6 476.5 1100 476.9 ;
    END
  END out_block_o[335]
  PIN out_block_o[336]
    DIRECTION OUTPUT ;
    USE SIGNAL ;
    PORT
      LAYER Metal3 ;
        RECT  1099.6 474.82 1100 475.22 ;
    END
  END out_block_o[336]
  PIN out_block_o[337]
    DIRECTION OUTPUT ;
    USE SIGNAL ;
    PORT
      LAYER Metal3 ;
        RECT  1099.6 473.14 1100 473.54 ;
    END
  END out_block_o[337]
  PIN out_block_o[338]
    DIRECTION OUTPUT ;
    USE SIGNAL ;
    PORT
      LAYER Metal3 ;
        RECT  1099.6 471.46 1100 471.86 ;
    END
  END out_block_o[338]
  PIN out_block_o[339]
    DIRECTION OUTPUT ;
    USE SIGNAL ;
    PORT
      LAYER Metal3 ;
        RECT  1099.6 469.78 1100 470.18 ;
    END
  END out_block_o[339]
  PIN out_block_o[33]
    DIRECTION OUTPUT ;
    USE SIGNAL ;
    PORT
      LAYER Metal3 ;
        RECT  1099.6 983.86 1100 984.26 ;
    END
  END out_block_o[33]
  PIN out_block_o[340]
    DIRECTION OUTPUT ;
    USE SIGNAL ;
    PORT
      LAYER Metal3 ;
        RECT  1099.6 468.1 1100 468.5 ;
    END
  END out_block_o[340]
  PIN out_block_o[341]
    DIRECTION OUTPUT ;
    USE SIGNAL ;
    PORT
      LAYER Metal3 ;
        RECT  1099.6 466.42 1100 466.82 ;
    END
  END out_block_o[341]
  PIN out_block_o[342]
    DIRECTION OUTPUT ;
    USE SIGNAL ;
    PORT
      LAYER Metal3 ;
        RECT  1099.6 464.74 1100 465.14 ;
    END
  END out_block_o[342]
  PIN out_block_o[343]
    DIRECTION OUTPUT ;
    USE SIGNAL ;
    PORT
      LAYER Metal3 ;
        RECT  1099.6 463.06 1100 463.46 ;
    END
  END out_block_o[343]
  PIN out_block_o[344]
    DIRECTION OUTPUT ;
    USE SIGNAL ;
    PORT
      LAYER Metal3 ;
        RECT  1099.6 461.38 1100 461.78 ;
    END
  END out_block_o[344]
  PIN out_block_o[345]
    DIRECTION OUTPUT ;
    USE SIGNAL ;
    PORT
      LAYER Metal3 ;
        RECT  1099.6 459.7 1100 460.1 ;
    END
  END out_block_o[345]
  PIN out_block_o[346]
    DIRECTION OUTPUT ;
    USE SIGNAL ;
    PORT
      LAYER Metal3 ;
        RECT  1099.6 458.02 1100 458.42 ;
    END
  END out_block_o[346]
  PIN out_block_o[347]
    DIRECTION OUTPUT ;
    USE SIGNAL ;
    PORT
      LAYER Metal3 ;
        RECT  1099.6 456.34 1100 456.74 ;
    END
  END out_block_o[347]
  PIN out_block_o[348]
    DIRECTION OUTPUT ;
    USE SIGNAL ;
    PORT
      LAYER Metal3 ;
        RECT  1099.6 454.66 1100 455.06 ;
    END
  END out_block_o[348]
  PIN out_block_o[349]
    DIRECTION OUTPUT ;
    USE SIGNAL ;
    PORT
      LAYER Metal3 ;
        RECT  1099.6 452.98 1100 453.38 ;
    END
  END out_block_o[349]
  PIN out_block_o[34]
    DIRECTION OUTPUT ;
    USE SIGNAL ;
    PORT
      LAYER Metal3 ;
        RECT  1099.6 982.18 1100 982.58 ;
    END
  END out_block_o[34]
  PIN out_block_o[350]
    DIRECTION OUTPUT ;
    USE SIGNAL ;
    PORT
      LAYER Metal3 ;
        RECT  1099.6 451.3 1100 451.7 ;
    END
  END out_block_o[350]
  PIN out_block_o[351]
    DIRECTION OUTPUT ;
    USE SIGNAL ;
    PORT
      LAYER Metal3 ;
        RECT  1099.6 449.62 1100 450.02 ;
    END
  END out_block_o[351]
  PIN out_block_o[352]
    DIRECTION OUTPUT ;
    USE SIGNAL ;
    PORT
      LAYER Metal3 ;
        RECT  1099.6 447.94 1100 448.34 ;
    END
  END out_block_o[352]
  PIN out_block_o[353]
    DIRECTION OUTPUT ;
    USE SIGNAL ;
    PORT
      LAYER Metal3 ;
        RECT  1099.6 446.26 1100 446.66 ;
    END
  END out_block_o[353]
  PIN out_block_o[354]
    DIRECTION OUTPUT ;
    USE SIGNAL ;
    PORT
      LAYER Metal3 ;
        RECT  1099.6 444.58 1100 444.98 ;
    END
  END out_block_o[354]
  PIN out_block_o[355]
    DIRECTION OUTPUT ;
    USE SIGNAL ;
    PORT
      LAYER Metal3 ;
        RECT  1099.6 442.9 1100 443.3 ;
    END
  END out_block_o[355]
  PIN out_block_o[356]
    DIRECTION OUTPUT ;
    USE SIGNAL ;
    PORT
      LAYER Metal3 ;
        RECT  1099.6 441.22 1100 441.62 ;
    END
  END out_block_o[356]
  PIN out_block_o[357]
    DIRECTION OUTPUT ;
    USE SIGNAL ;
    PORT
      LAYER Metal3 ;
        RECT  1099.6 439.54 1100 439.94 ;
    END
  END out_block_o[357]
  PIN out_block_o[358]
    DIRECTION OUTPUT ;
    USE SIGNAL ;
    PORT
      LAYER Metal3 ;
        RECT  1099.6 437.86 1100 438.26 ;
    END
  END out_block_o[358]
  PIN out_block_o[359]
    DIRECTION OUTPUT ;
    USE SIGNAL ;
    PORT
      LAYER Metal3 ;
        RECT  1099.6 436.18 1100 436.58 ;
    END
  END out_block_o[359]
  PIN out_block_o[35]
    DIRECTION OUTPUT ;
    USE SIGNAL ;
    PORT
      LAYER Metal3 ;
        RECT  1099.6 980.5 1100 980.9 ;
    END
  END out_block_o[35]
  PIN out_block_o[360]
    DIRECTION OUTPUT ;
    USE SIGNAL ;
    PORT
      LAYER Metal3 ;
        RECT  1099.6 434.5 1100 434.9 ;
    END
  END out_block_o[360]
  PIN out_block_o[361]
    DIRECTION OUTPUT ;
    USE SIGNAL ;
    PORT
      LAYER Metal3 ;
        RECT  1099.6 432.82 1100 433.22 ;
    END
  END out_block_o[361]
  PIN out_block_o[362]
    DIRECTION OUTPUT ;
    USE SIGNAL ;
    PORT
      LAYER Metal3 ;
        RECT  1099.6 431.14 1100 431.54 ;
    END
  END out_block_o[362]
  PIN out_block_o[363]
    DIRECTION OUTPUT ;
    USE SIGNAL ;
    PORT
      LAYER Metal3 ;
        RECT  1099.6 429.46 1100 429.86 ;
    END
  END out_block_o[363]
  PIN out_block_o[364]
    DIRECTION OUTPUT ;
    USE SIGNAL ;
    PORT
      LAYER Metal3 ;
        RECT  1099.6 427.78 1100 428.18 ;
    END
  END out_block_o[364]
  PIN out_block_o[365]
    DIRECTION OUTPUT ;
    USE SIGNAL ;
    PORT
      LAYER Metal3 ;
        RECT  1099.6 426.1 1100 426.5 ;
    END
  END out_block_o[365]
  PIN out_block_o[366]
    DIRECTION OUTPUT ;
    USE SIGNAL ;
    PORT
      LAYER Metal3 ;
        RECT  1099.6 424.42 1100 424.82 ;
    END
  END out_block_o[366]
  PIN out_block_o[367]
    DIRECTION OUTPUT ;
    USE SIGNAL ;
    PORT
      LAYER Metal3 ;
        RECT  1099.6 422.74 1100 423.14 ;
    END
  END out_block_o[367]
  PIN out_block_o[368]
    DIRECTION OUTPUT ;
    USE SIGNAL ;
    PORT
      LAYER Metal3 ;
        RECT  1099.6 421.06 1100 421.46 ;
    END
  END out_block_o[368]
  PIN out_block_o[369]
    DIRECTION OUTPUT ;
    USE SIGNAL ;
    PORT
      LAYER Metal3 ;
        RECT  1099.6 419.38 1100 419.78 ;
    END
  END out_block_o[369]
  PIN out_block_o[36]
    DIRECTION OUTPUT ;
    USE SIGNAL ;
    PORT
      LAYER Metal3 ;
        RECT  1099.6 978.82 1100 979.22 ;
    END
  END out_block_o[36]
  PIN out_block_o[370]
    DIRECTION OUTPUT ;
    USE SIGNAL ;
    PORT
      LAYER Metal3 ;
        RECT  1099.6 417.7 1100 418.1 ;
    END
  END out_block_o[370]
  PIN out_block_o[371]
    DIRECTION OUTPUT ;
    USE SIGNAL ;
    PORT
      LAYER Metal3 ;
        RECT  1099.6 416.02 1100 416.42 ;
    END
  END out_block_o[371]
  PIN out_block_o[372]
    DIRECTION OUTPUT ;
    USE SIGNAL ;
    PORT
      LAYER Metal3 ;
        RECT  1099.6 414.34 1100 414.74 ;
    END
  END out_block_o[372]
  PIN out_block_o[373]
    DIRECTION OUTPUT ;
    USE SIGNAL ;
    PORT
      LAYER Metal3 ;
        RECT  1099.6 412.66 1100 413.06 ;
    END
  END out_block_o[373]
  PIN out_block_o[374]
    DIRECTION OUTPUT ;
    USE SIGNAL ;
    PORT
      LAYER Metal3 ;
        RECT  1099.6 410.98 1100 411.38 ;
    END
  END out_block_o[374]
  PIN out_block_o[375]
    DIRECTION OUTPUT ;
    USE SIGNAL ;
    PORT
      LAYER Metal3 ;
        RECT  1099.6 409.3 1100 409.7 ;
    END
  END out_block_o[375]
  PIN out_block_o[376]
    DIRECTION OUTPUT ;
    USE SIGNAL ;
    PORT
      LAYER Metal3 ;
        RECT  1099.6 407.62 1100 408.02 ;
    END
  END out_block_o[376]
  PIN out_block_o[377]
    DIRECTION OUTPUT ;
    USE SIGNAL ;
    PORT
      LAYER Metal3 ;
        RECT  1099.6 405.94 1100 406.34 ;
    END
  END out_block_o[377]
  PIN out_block_o[378]
    DIRECTION OUTPUT ;
    USE SIGNAL ;
    PORT
      LAYER Metal3 ;
        RECT  1099.6 404.26 1100 404.66 ;
    END
  END out_block_o[378]
  PIN out_block_o[379]
    DIRECTION OUTPUT ;
    USE SIGNAL ;
    PORT
      LAYER Metal3 ;
        RECT  1099.6 402.58 1100 402.98 ;
    END
  END out_block_o[379]
  PIN out_block_o[37]
    DIRECTION OUTPUT ;
    USE SIGNAL ;
    PORT
      LAYER Metal3 ;
        RECT  1099.6 977.14 1100 977.54 ;
    END
  END out_block_o[37]
  PIN out_block_o[380]
    DIRECTION OUTPUT ;
    USE SIGNAL ;
    PORT
      LAYER Metal3 ;
        RECT  1099.6 400.9 1100 401.3 ;
    END
  END out_block_o[380]
  PIN out_block_o[381]
    DIRECTION OUTPUT ;
    USE SIGNAL ;
    PORT
      LAYER Metal3 ;
        RECT  1099.6 399.22 1100 399.62 ;
    END
  END out_block_o[381]
  PIN out_block_o[382]
    DIRECTION OUTPUT ;
    USE SIGNAL ;
    PORT
      LAYER Metal3 ;
        RECT  1099.6 397.54 1100 397.94 ;
    END
  END out_block_o[382]
  PIN out_block_o[383]
    DIRECTION OUTPUT ;
    USE SIGNAL ;
    PORT
      LAYER Metal3 ;
        RECT  1099.6 395.86 1100 396.26 ;
    END
  END out_block_o[383]
  PIN out_block_o[384]
    DIRECTION OUTPUT ;
    USE SIGNAL ;
    PORT
      LAYER Metal3 ;
        RECT  1099.6 394.18 1100 394.58 ;
    END
  END out_block_o[384]
  PIN out_block_o[385]
    DIRECTION OUTPUT ;
    USE SIGNAL ;
    PORT
      LAYER Metal3 ;
        RECT  1099.6 392.5 1100 392.9 ;
    END
  END out_block_o[385]
  PIN out_block_o[386]
    DIRECTION OUTPUT ;
    USE SIGNAL ;
    PORT
      LAYER Metal3 ;
        RECT  1099.6 390.82 1100 391.22 ;
    END
  END out_block_o[386]
  PIN out_block_o[387]
    DIRECTION OUTPUT ;
    USE SIGNAL ;
    PORT
      LAYER Metal3 ;
        RECT  1099.6 389.14 1100 389.54 ;
    END
  END out_block_o[387]
  PIN out_block_o[388]
    DIRECTION OUTPUT ;
    USE SIGNAL ;
    PORT
      LAYER Metal3 ;
        RECT  1099.6 387.46 1100 387.86 ;
    END
  END out_block_o[388]
  PIN out_block_o[389]
    DIRECTION OUTPUT ;
    USE SIGNAL ;
    PORT
      LAYER Metal3 ;
        RECT  1099.6 385.78 1100 386.18 ;
    END
  END out_block_o[389]
  PIN out_block_o[38]
    DIRECTION OUTPUT ;
    USE SIGNAL ;
    PORT
      LAYER Metal3 ;
        RECT  1099.6 975.46 1100 975.86 ;
    END
  END out_block_o[38]
  PIN out_block_o[390]
    DIRECTION OUTPUT ;
    USE SIGNAL ;
    PORT
      LAYER Metal3 ;
        RECT  1099.6 384.1 1100 384.5 ;
    END
  END out_block_o[390]
  PIN out_block_o[391]
    DIRECTION OUTPUT ;
    USE SIGNAL ;
    PORT
      LAYER Metal3 ;
        RECT  1099.6 382.42 1100 382.82 ;
    END
  END out_block_o[391]
  PIN out_block_o[392]
    DIRECTION OUTPUT ;
    USE SIGNAL ;
    PORT
      LAYER Metal3 ;
        RECT  1099.6 380.74 1100 381.14 ;
    END
  END out_block_o[392]
  PIN out_block_o[393]
    DIRECTION OUTPUT ;
    USE SIGNAL ;
    PORT
      LAYER Metal3 ;
        RECT  1099.6 379.06 1100 379.46 ;
    END
  END out_block_o[393]
  PIN out_block_o[394]
    DIRECTION OUTPUT ;
    USE SIGNAL ;
    PORT
      LAYER Metal3 ;
        RECT  1099.6 377.38 1100 377.78 ;
    END
  END out_block_o[394]
  PIN out_block_o[395]
    DIRECTION OUTPUT ;
    USE SIGNAL ;
    PORT
      LAYER Metal3 ;
        RECT  1099.6 375.7 1100 376.1 ;
    END
  END out_block_o[395]
  PIN out_block_o[396]
    DIRECTION OUTPUT ;
    USE SIGNAL ;
    PORT
      LAYER Metal3 ;
        RECT  1099.6 374.02 1100 374.42 ;
    END
  END out_block_o[396]
  PIN out_block_o[397]
    DIRECTION OUTPUT ;
    USE SIGNAL ;
    PORT
      LAYER Metal3 ;
        RECT  1099.6 372.34 1100 372.74 ;
    END
  END out_block_o[397]
  PIN out_block_o[398]
    DIRECTION OUTPUT ;
    USE SIGNAL ;
    PORT
      LAYER Metal3 ;
        RECT  1099.6 370.66 1100 371.06 ;
    END
  END out_block_o[398]
  PIN out_block_o[399]
    DIRECTION OUTPUT ;
    USE SIGNAL ;
    PORT
      LAYER Metal3 ;
        RECT  1099.6 368.98 1100 369.38 ;
    END
  END out_block_o[399]
  PIN out_block_o[39]
    DIRECTION OUTPUT ;
    USE SIGNAL ;
    PORT
      LAYER Metal3 ;
        RECT  1099.6 973.78 1100 974.18 ;
    END
  END out_block_o[39]
  PIN out_block_o[3]
    DIRECTION OUTPUT ;
    USE SIGNAL ;
    PORT
      LAYER Metal3 ;
        RECT  1099.6 1034.26 1100 1034.66 ;
    END
  END out_block_o[3]
  PIN out_block_o[400]
    DIRECTION OUTPUT ;
    USE SIGNAL ;
    PORT
      LAYER Metal3 ;
        RECT  1099.6 367.3 1100 367.7 ;
    END
  END out_block_o[400]
  PIN out_block_o[401]
    DIRECTION OUTPUT ;
    USE SIGNAL ;
    PORT
      LAYER Metal3 ;
        RECT  1099.6 365.62 1100 366.02 ;
    END
  END out_block_o[401]
  PIN out_block_o[402]
    DIRECTION OUTPUT ;
    USE SIGNAL ;
    PORT
      LAYER Metal3 ;
        RECT  1099.6 363.94 1100 364.34 ;
    END
  END out_block_o[402]
  PIN out_block_o[403]
    DIRECTION OUTPUT ;
    USE SIGNAL ;
    PORT
      LAYER Metal3 ;
        RECT  1099.6 362.26 1100 362.66 ;
    END
  END out_block_o[403]
  PIN out_block_o[404]
    DIRECTION OUTPUT ;
    USE SIGNAL ;
    PORT
      LAYER Metal3 ;
        RECT  1099.6 360.58 1100 360.98 ;
    END
  END out_block_o[404]
  PIN out_block_o[405]
    DIRECTION OUTPUT ;
    USE SIGNAL ;
    PORT
      LAYER Metal3 ;
        RECT  1099.6 358.9 1100 359.3 ;
    END
  END out_block_o[405]
  PIN out_block_o[406]
    DIRECTION OUTPUT ;
    USE SIGNAL ;
    PORT
      LAYER Metal3 ;
        RECT  1099.6 357.22 1100 357.62 ;
    END
  END out_block_o[406]
  PIN out_block_o[407]
    DIRECTION OUTPUT ;
    USE SIGNAL ;
    PORT
      LAYER Metal3 ;
        RECT  1099.6 355.54 1100 355.94 ;
    END
  END out_block_o[407]
  PIN out_block_o[408]
    DIRECTION OUTPUT ;
    USE SIGNAL ;
    PORT
      LAYER Metal3 ;
        RECT  1099.6 353.86 1100 354.26 ;
    END
  END out_block_o[408]
  PIN out_block_o[409]
    DIRECTION OUTPUT ;
    USE SIGNAL ;
    PORT
      LAYER Metal3 ;
        RECT  1099.6 352.18 1100 352.58 ;
    END
  END out_block_o[409]
  PIN out_block_o[40]
    DIRECTION OUTPUT ;
    USE SIGNAL ;
    PORT
      LAYER Metal3 ;
        RECT  1099.6 972.1 1100 972.5 ;
    END
  END out_block_o[40]
  PIN out_block_o[410]
    DIRECTION OUTPUT ;
    USE SIGNAL ;
    PORT
      LAYER Metal3 ;
        RECT  1099.6 350.5 1100 350.9 ;
    END
  END out_block_o[410]
  PIN out_block_o[411]
    DIRECTION OUTPUT ;
    USE SIGNAL ;
    PORT
      LAYER Metal3 ;
        RECT  1099.6 348.82 1100 349.22 ;
    END
  END out_block_o[411]
  PIN out_block_o[412]
    DIRECTION OUTPUT ;
    USE SIGNAL ;
    PORT
      LAYER Metal3 ;
        RECT  1099.6 347.14 1100 347.54 ;
    END
  END out_block_o[412]
  PIN out_block_o[413]
    DIRECTION OUTPUT ;
    USE SIGNAL ;
    PORT
      LAYER Metal3 ;
        RECT  1099.6 345.46 1100 345.86 ;
    END
  END out_block_o[413]
  PIN out_block_o[414]
    DIRECTION OUTPUT ;
    USE SIGNAL ;
    PORT
      LAYER Metal3 ;
        RECT  1099.6 343.78 1100 344.18 ;
    END
  END out_block_o[414]
  PIN out_block_o[415]
    DIRECTION OUTPUT ;
    USE SIGNAL ;
    PORT
      LAYER Metal3 ;
        RECT  1099.6 342.1 1100 342.5 ;
    END
  END out_block_o[415]
  PIN out_block_o[416]
    DIRECTION OUTPUT ;
    USE SIGNAL ;
    PORT
      LAYER Metal3 ;
        RECT  1099.6 340.42 1100 340.82 ;
    END
  END out_block_o[416]
  PIN out_block_o[417]
    DIRECTION OUTPUT ;
    USE SIGNAL ;
    PORT
      LAYER Metal3 ;
        RECT  1099.6 338.74 1100 339.14 ;
    END
  END out_block_o[417]
  PIN out_block_o[418]
    DIRECTION OUTPUT ;
    USE SIGNAL ;
    PORT
      LAYER Metal3 ;
        RECT  1099.6 337.06 1100 337.46 ;
    END
  END out_block_o[418]
  PIN out_block_o[419]
    DIRECTION OUTPUT ;
    USE SIGNAL ;
    PORT
      LAYER Metal3 ;
        RECT  1099.6 335.38 1100 335.78 ;
    END
  END out_block_o[419]
  PIN out_block_o[41]
    DIRECTION OUTPUT ;
    USE SIGNAL ;
    PORT
      LAYER Metal3 ;
        RECT  1099.6 970.42 1100 970.82 ;
    END
  END out_block_o[41]
  PIN out_block_o[420]
    DIRECTION OUTPUT ;
    USE SIGNAL ;
    PORT
      LAYER Metal3 ;
        RECT  1099.6 333.7 1100 334.1 ;
    END
  END out_block_o[420]
  PIN out_block_o[421]
    DIRECTION OUTPUT ;
    USE SIGNAL ;
    PORT
      LAYER Metal3 ;
        RECT  1099.6 332.02 1100 332.42 ;
    END
  END out_block_o[421]
  PIN out_block_o[422]
    DIRECTION OUTPUT ;
    USE SIGNAL ;
    PORT
      LAYER Metal3 ;
        RECT  1099.6 330.34 1100 330.74 ;
    END
  END out_block_o[422]
  PIN out_block_o[423]
    DIRECTION OUTPUT ;
    USE SIGNAL ;
    PORT
      LAYER Metal3 ;
        RECT  1099.6 328.66 1100 329.06 ;
    END
  END out_block_o[423]
  PIN out_block_o[424]
    DIRECTION OUTPUT ;
    USE SIGNAL ;
    PORT
      LAYER Metal3 ;
        RECT  1099.6 326.98 1100 327.38 ;
    END
  END out_block_o[424]
  PIN out_block_o[425]
    DIRECTION OUTPUT ;
    USE SIGNAL ;
    PORT
      LAYER Metal3 ;
        RECT  1099.6 325.3 1100 325.7 ;
    END
  END out_block_o[425]
  PIN out_block_o[426]
    DIRECTION OUTPUT ;
    USE SIGNAL ;
    PORT
      LAYER Metal3 ;
        RECT  1099.6 323.62 1100 324.02 ;
    END
  END out_block_o[426]
  PIN out_block_o[427]
    DIRECTION OUTPUT ;
    USE SIGNAL ;
    PORT
      LAYER Metal3 ;
        RECT  1099.6 321.94 1100 322.34 ;
    END
  END out_block_o[427]
  PIN out_block_o[428]
    DIRECTION OUTPUT ;
    USE SIGNAL ;
    PORT
      LAYER Metal3 ;
        RECT  1099.6 320.26 1100 320.66 ;
    END
  END out_block_o[428]
  PIN out_block_o[429]
    DIRECTION OUTPUT ;
    USE SIGNAL ;
    PORT
      LAYER Metal3 ;
        RECT  1099.6 318.58 1100 318.98 ;
    END
  END out_block_o[429]
  PIN out_block_o[42]
    DIRECTION OUTPUT ;
    USE SIGNAL ;
    PORT
      LAYER Metal3 ;
        RECT  1099.6 968.74 1100 969.14 ;
    END
  END out_block_o[42]
  PIN out_block_o[430]
    DIRECTION OUTPUT ;
    USE SIGNAL ;
    PORT
      LAYER Metal3 ;
        RECT  1099.6 316.9 1100 317.3 ;
    END
  END out_block_o[430]
  PIN out_block_o[431]
    DIRECTION OUTPUT ;
    USE SIGNAL ;
    PORT
      LAYER Metal3 ;
        RECT  1099.6 315.22 1100 315.62 ;
    END
  END out_block_o[431]
  PIN out_block_o[432]
    DIRECTION OUTPUT ;
    USE SIGNAL ;
    PORT
      LAYER Metal3 ;
        RECT  1099.6 313.54 1100 313.94 ;
    END
  END out_block_o[432]
  PIN out_block_o[433]
    DIRECTION OUTPUT ;
    USE SIGNAL ;
    PORT
      LAYER Metal3 ;
        RECT  1099.6 311.86 1100 312.26 ;
    END
  END out_block_o[433]
  PIN out_block_o[434]
    DIRECTION OUTPUT ;
    USE SIGNAL ;
    PORT
      LAYER Metal3 ;
        RECT  1099.6 310.18 1100 310.58 ;
    END
  END out_block_o[434]
  PIN out_block_o[435]
    DIRECTION OUTPUT ;
    USE SIGNAL ;
    PORT
      LAYER Metal3 ;
        RECT  1099.6 308.5 1100 308.9 ;
    END
  END out_block_o[435]
  PIN out_block_o[436]
    DIRECTION OUTPUT ;
    USE SIGNAL ;
    PORT
      LAYER Metal3 ;
        RECT  1099.6 306.82 1100 307.22 ;
    END
  END out_block_o[436]
  PIN out_block_o[437]
    DIRECTION OUTPUT ;
    USE SIGNAL ;
    PORT
      LAYER Metal3 ;
        RECT  1099.6 305.14 1100 305.54 ;
    END
  END out_block_o[437]
  PIN out_block_o[438]
    DIRECTION OUTPUT ;
    USE SIGNAL ;
    PORT
      LAYER Metal3 ;
        RECT  1099.6 303.46 1100 303.86 ;
    END
  END out_block_o[438]
  PIN out_block_o[439]
    DIRECTION OUTPUT ;
    USE SIGNAL ;
    PORT
      LAYER Metal3 ;
        RECT  1099.6 301.78 1100 302.18 ;
    END
  END out_block_o[439]
  PIN out_block_o[43]
    DIRECTION OUTPUT ;
    USE SIGNAL ;
    PORT
      LAYER Metal3 ;
        RECT  1099.6 967.06 1100 967.46 ;
    END
  END out_block_o[43]
  PIN out_block_o[440]
    DIRECTION OUTPUT ;
    USE SIGNAL ;
    PORT
      LAYER Metal3 ;
        RECT  1099.6 300.1 1100 300.5 ;
    END
  END out_block_o[440]
  PIN out_block_o[441]
    DIRECTION OUTPUT ;
    USE SIGNAL ;
    PORT
      LAYER Metal3 ;
        RECT  1099.6 298.42 1100 298.82 ;
    END
  END out_block_o[441]
  PIN out_block_o[442]
    DIRECTION OUTPUT ;
    USE SIGNAL ;
    PORT
      LAYER Metal3 ;
        RECT  1099.6 296.74 1100 297.14 ;
    END
  END out_block_o[442]
  PIN out_block_o[443]
    DIRECTION OUTPUT ;
    USE SIGNAL ;
    PORT
      LAYER Metal3 ;
        RECT  1099.6 295.06 1100 295.46 ;
    END
  END out_block_o[443]
  PIN out_block_o[444]
    DIRECTION OUTPUT ;
    USE SIGNAL ;
    PORT
      LAYER Metal3 ;
        RECT  1099.6 293.38 1100 293.78 ;
    END
  END out_block_o[444]
  PIN out_block_o[445]
    DIRECTION OUTPUT ;
    USE SIGNAL ;
    PORT
      LAYER Metal3 ;
        RECT  1099.6 291.7 1100 292.1 ;
    END
  END out_block_o[445]
  PIN out_block_o[446]
    DIRECTION OUTPUT ;
    USE SIGNAL ;
    PORT
      LAYER Metal3 ;
        RECT  1099.6 290.02 1100 290.42 ;
    END
  END out_block_o[446]
  PIN out_block_o[447]
    DIRECTION OUTPUT ;
    USE SIGNAL ;
    PORT
      LAYER Metal3 ;
        RECT  1099.6 288.34 1100 288.74 ;
    END
  END out_block_o[447]
  PIN out_block_o[448]
    DIRECTION OUTPUT ;
    USE SIGNAL ;
    PORT
      LAYER Metal3 ;
        RECT  1099.6 286.66 1100 287.06 ;
    END
  END out_block_o[448]
  PIN out_block_o[449]
    DIRECTION OUTPUT ;
    USE SIGNAL ;
    PORT
      LAYER Metal3 ;
        RECT  1099.6 284.98 1100 285.38 ;
    END
  END out_block_o[449]
  PIN out_block_o[44]
    DIRECTION OUTPUT ;
    USE SIGNAL ;
    PORT
      LAYER Metal3 ;
        RECT  1099.6 965.38 1100 965.78 ;
    END
  END out_block_o[44]
  PIN out_block_o[450]
    DIRECTION OUTPUT ;
    USE SIGNAL ;
    PORT
      LAYER Metal3 ;
        RECT  1099.6 283.3 1100 283.7 ;
    END
  END out_block_o[450]
  PIN out_block_o[451]
    DIRECTION OUTPUT ;
    USE SIGNAL ;
    PORT
      LAYER Metal3 ;
        RECT  1099.6 281.62 1100 282.02 ;
    END
  END out_block_o[451]
  PIN out_block_o[452]
    DIRECTION OUTPUT ;
    USE SIGNAL ;
    PORT
      LAYER Metal3 ;
        RECT  1099.6 279.94 1100 280.34 ;
    END
  END out_block_o[452]
  PIN out_block_o[453]
    DIRECTION OUTPUT ;
    USE SIGNAL ;
    PORT
      LAYER Metal3 ;
        RECT  1099.6 278.26 1100 278.66 ;
    END
  END out_block_o[453]
  PIN out_block_o[454]
    DIRECTION OUTPUT ;
    USE SIGNAL ;
    PORT
      LAYER Metal3 ;
        RECT  1099.6 276.58 1100 276.98 ;
    END
  END out_block_o[454]
  PIN out_block_o[455]
    DIRECTION OUTPUT ;
    USE SIGNAL ;
    PORT
      LAYER Metal3 ;
        RECT  1099.6 274.9 1100 275.3 ;
    END
  END out_block_o[455]
  PIN out_block_o[456]
    DIRECTION OUTPUT ;
    USE SIGNAL ;
    PORT
      LAYER Metal3 ;
        RECT  1099.6 273.22 1100 273.62 ;
    END
  END out_block_o[456]
  PIN out_block_o[457]
    DIRECTION OUTPUT ;
    USE SIGNAL ;
    PORT
      LAYER Metal3 ;
        RECT  1099.6 271.54 1100 271.94 ;
    END
  END out_block_o[457]
  PIN out_block_o[458]
    DIRECTION OUTPUT ;
    USE SIGNAL ;
    PORT
      LAYER Metal3 ;
        RECT  1099.6 269.86 1100 270.26 ;
    END
  END out_block_o[458]
  PIN out_block_o[459]
    DIRECTION OUTPUT ;
    USE SIGNAL ;
    PORT
      LAYER Metal3 ;
        RECT  1099.6 268.18 1100 268.58 ;
    END
  END out_block_o[459]
  PIN out_block_o[45]
    DIRECTION OUTPUT ;
    USE SIGNAL ;
    PORT
      LAYER Metal3 ;
        RECT  1099.6 963.7 1100 964.1 ;
    END
  END out_block_o[45]
  PIN out_block_o[460]
    DIRECTION OUTPUT ;
    USE SIGNAL ;
    PORT
      LAYER Metal3 ;
        RECT  1099.6 266.5 1100 266.9 ;
    END
  END out_block_o[460]
  PIN out_block_o[461]
    DIRECTION OUTPUT ;
    USE SIGNAL ;
    PORT
      LAYER Metal3 ;
        RECT  1099.6 264.82 1100 265.22 ;
    END
  END out_block_o[461]
  PIN out_block_o[462]
    DIRECTION OUTPUT ;
    USE SIGNAL ;
    PORT
      LAYER Metal3 ;
        RECT  1099.6 263.14 1100 263.54 ;
    END
  END out_block_o[462]
  PIN out_block_o[463]
    DIRECTION OUTPUT ;
    USE SIGNAL ;
    PORT
      LAYER Metal3 ;
        RECT  1099.6 261.46 1100 261.86 ;
    END
  END out_block_o[463]
  PIN out_block_o[464]
    DIRECTION OUTPUT ;
    USE SIGNAL ;
    PORT
      LAYER Metal3 ;
        RECT  1099.6 259.78 1100 260.18 ;
    END
  END out_block_o[464]
  PIN out_block_o[465]
    DIRECTION OUTPUT ;
    USE SIGNAL ;
    PORT
      LAYER Metal3 ;
        RECT  1099.6 258.1 1100 258.5 ;
    END
  END out_block_o[465]
  PIN out_block_o[466]
    DIRECTION OUTPUT ;
    USE SIGNAL ;
    PORT
      LAYER Metal3 ;
        RECT  1099.6 256.42 1100 256.82 ;
    END
  END out_block_o[466]
  PIN out_block_o[467]
    DIRECTION OUTPUT ;
    USE SIGNAL ;
    PORT
      LAYER Metal3 ;
        RECT  1099.6 254.74 1100 255.14 ;
    END
  END out_block_o[467]
  PIN out_block_o[468]
    DIRECTION OUTPUT ;
    USE SIGNAL ;
    PORT
      LAYER Metal3 ;
        RECT  1099.6 253.06 1100 253.46 ;
    END
  END out_block_o[468]
  PIN out_block_o[469]
    DIRECTION OUTPUT ;
    USE SIGNAL ;
    PORT
      LAYER Metal3 ;
        RECT  1099.6 251.38 1100 251.78 ;
    END
  END out_block_o[469]
  PIN out_block_o[46]
    DIRECTION OUTPUT ;
    USE SIGNAL ;
    PORT
      LAYER Metal3 ;
        RECT  1099.6 962.02 1100 962.42 ;
    END
  END out_block_o[46]
  PIN out_block_o[470]
    DIRECTION OUTPUT ;
    USE SIGNAL ;
    PORT
      LAYER Metal3 ;
        RECT  1099.6 249.7 1100 250.1 ;
    END
  END out_block_o[470]
  PIN out_block_o[471]
    DIRECTION OUTPUT ;
    USE SIGNAL ;
    PORT
      LAYER Metal3 ;
        RECT  1099.6 248.02 1100 248.42 ;
    END
  END out_block_o[471]
  PIN out_block_o[472]
    DIRECTION OUTPUT ;
    USE SIGNAL ;
    PORT
      LAYER Metal3 ;
        RECT  1099.6 246.34 1100 246.74 ;
    END
  END out_block_o[472]
  PIN out_block_o[473]
    DIRECTION OUTPUT ;
    USE SIGNAL ;
    PORT
      LAYER Metal3 ;
        RECT  1099.6 244.66 1100 245.06 ;
    END
  END out_block_o[473]
  PIN out_block_o[474]
    DIRECTION OUTPUT ;
    USE SIGNAL ;
    PORT
      LAYER Metal3 ;
        RECT  1099.6 242.98 1100 243.38 ;
    END
  END out_block_o[474]
  PIN out_block_o[475]
    DIRECTION OUTPUT ;
    USE SIGNAL ;
    PORT
      LAYER Metal3 ;
        RECT  1099.6 241.3 1100 241.7 ;
    END
  END out_block_o[475]
  PIN out_block_o[476]
    DIRECTION OUTPUT ;
    USE SIGNAL ;
    PORT
      LAYER Metal3 ;
        RECT  1099.6 239.62 1100 240.02 ;
    END
  END out_block_o[476]
  PIN out_block_o[477]
    DIRECTION OUTPUT ;
    USE SIGNAL ;
    PORT
      LAYER Metal3 ;
        RECT  1099.6 237.94 1100 238.34 ;
    END
  END out_block_o[477]
  PIN out_block_o[478]
    DIRECTION OUTPUT ;
    USE SIGNAL ;
    PORT
      LAYER Metal3 ;
        RECT  1099.6 236.26 1100 236.66 ;
    END
  END out_block_o[478]
  PIN out_block_o[479]
    DIRECTION OUTPUT ;
    USE SIGNAL ;
    PORT
      LAYER Metal3 ;
        RECT  1099.6 234.58 1100 234.98 ;
    END
  END out_block_o[479]
  PIN out_block_o[47]
    DIRECTION OUTPUT ;
    USE SIGNAL ;
    PORT
      LAYER Metal3 ;
        RECT  1099.6 960.34 1100 960.74 ;
    END
  END out_block_o[47]
  PIN out_block_o[480]
    DIRECTION OUTPUT ;
    USE SIGNAL ;
    PORT
      LAYER Metal3 ;
        RECT  1099.6 232.9 1100 233.3 ;
    END
  END out_block_o[480]
  PIN out_block_o[481]
    DIRECTION OUTPUT ;
    USE SIGNAL ;
    PORT
      LAYER Metal3 ;
        RECT  1099.6 231.22 1100 231.62 ;
    END
  END out_block_o[481]
  PIN out_block_o[482]
    DIRECTION OUTPUT ;
    USE SIGNAL ;
    PORT
      LAYER Metal3 ;
        RECT  1099.6 229.54 1100 229.94 ;
    END
  END out_block_o[482]
  PIN out_block_o[483]
    DIRECTION OUTPUT ;
    USE SIGNAL ;
    PORT
      LAYER Metal3 ;
        RECT  1099.6 227.86 1100 228.26 ;
    END
  END out_block_o[483]
  PIN out_block_o[484]
    DIRECTION OUTPUT ;
    USE SIGNAL ;
    PORT
      LAYER Metal3 ;
        RECT  1099.6 226.18 1100 226.58 ;
    END
  END out_block_o[484]
  PIN out_block_o[485]
    DIRECTION OUTPUT ;
    USE SIGNAL ;
    PORT
      LAYER Metal3 ;
        RECT  1099.6 224.5 1100 224.9 ;
    END
  END out_block_o[485]
  PIN out_block_o[486]
    DIRECTION OUTPUT ;
    USE SIGNAL ;
    PORT
      LAYER Metal3 ;
        RECT  1099.6 222.82 1100 223.22 ;
    END
  END out_block_o[486]
  PIN out_block_o[487]
    DIRECTION OUTPUT ;
    USE SIGNAL ;
    PORT
      LAYER Metal3 ;
        RECT  1099.6 221.14 1100 221.54 ;
    END
  END out_block_o[487]
  PIN out_block_o[488]
    DIRECTION OUTPUT ;
    USE SIGNAL ;
    PORT
      LAYER Metal3 ;
        RECT  1099.6 219.46 1100 219.86 ;
    END
  END out_block_o[488]
  PIN out_block_o[489]
    DIRECTION OUTPUT ;
    USE SIGNAL ;
    PORT
      LAYER Metal3 ;
        RECT  1099.6 217.78 1100 218.18 ;
    END
  END out_block_o[489]
  PIN out_block_o[48]
    DIRECTION OUTPUT ;
    USE SIGNAL ;
    PORT
      LAYER Metal3 ;
        RECT  1099.6 958.66 1100 959.06 ;
    END
  END out_block_o[48]
  PIN out_block_o[490]
    DIRECTION OUTPUT ;
    USE SIGNAL ;
    PORT
      LAYER Metal3 ;
        RECT  1099.6 216.1 1100 216.5 ;
    END
  END out_block_o[490]
  PIN out_block_o[491]
    DIRECTION OUTPUT ;
    USE SIGNAL ;
    PORT
      LAYER Metal3 ;
        RECT  1099.6 214.42 1100 214.82 ;
    END
  END out_block_o[491]
  PIN out_block_o[492]
    DIRECTION OUTPUT ;
    USE SIGNAL ;
    PORT
      LAYER Metal3 ;
        RECT  1099.6 212.74 1100 213.14 ;
    END
  END out_block_o[492]
  PIN out_block_o[493]
    DIRECTION OUTPUT ;
    USE SIGNAL ;
    PORT
      LAYER Metal3 ;
        RECT  1099.6 211.06 1100 211.46 ;
    END
  END out_block_o[493]
  PIN out_block_o[494]
    DIRECTION OUTPUT ;
    USE SIGNAL ;
    PORT
      LAYER Metal3 ;
        RECT  1099.6 209.38 1100 209.78 ;
    END
  END out_block_o[494]
  PIN out_block_o[495]
    DIRECTION OUTPUT ;
    USE SIGNAL ;
    PORT
      LAYER Metal3 ;
        RECT  1099.6 207.7 1100 208.1 ;
    END
  END out_block_o[495]
  PIN out_block_o[496]
    DIRECTION OUTPUT ;
    USE SIGNAL ;
    PORT
      LAYER Metal3 ;
        RECT  1099.6 206.02 1100 206.42 ;
    END
  END out_block_o[496]
  PIN out_block_o[497]
    DIRECTION OUTPUT ;
    USE SIGNAL ;
    PORT
      LAYER Metal3 ;
        RECT  1099.6 204.34 1100 204.74 ;
    END
  END out_block_o[497]
  PIN out_block_o[498]
    DIRECTION OUTPUT ;
    USE SIGNAL ;
    PORT
      LAYER Metal3 ;
        RECT  1099.6 202.66 1100 203.06 ;
    END
  END out_block_o[498]
  PIN out_block_o[499]
    DIRECTION OUTPUT ;
    USE SIGNAL ;
    PORT
      LAYER Metal3 ;
        RECT  1099.6 200.98 1100 201.38 ;
    END
  END out_block_o[499]
  PIN out_block_o[49]
    DIRECTION OUTPUT ;
    USE SIGNAL ;
    PORT
      LAYER Metal3 ;
        RECT  1099.6 956.98 1100 957.38 ;
    END
  END out_block_o[49]
  PIN out_block_o[4]
    DIRECTION OUTPUT ;
    USE SIGNAL ;
    PORT
      LAYER Metal3 ;
        RECT  1099.6 1032.58 1100 1032.98 ;
    END
  END out_block_o[4]
  PIN out_block_o[500]
    DIRECTION OUTPUT ;
    USE SIGNAL ;
    PORT
      LAYER Metal3 ;
        RECT  1099.6 199.3 1100 199.7 ;
    END
  END out_block_o[500]
  PIN out_block_o[501]
    DIRECTION OUTPUT ;
    USE SIGNAL ;
    PORT
      LAYER Metal3 ;
        RECT  1099.6 197.62 1100 198.02 ;
    END
  END out_block_o[501]
  PIN out_block_o[502]
    DIRECTION OUTPUT ;
    USE SIGNAL ;
    PORT
      LAYER Metal3 ;
        RECT  1099.6 195.94 1100 196.34 ;
    END
  END out_block_o[502]
  PIN out_block_o[503]
    DIRECTION OUTPUT ;
    USE SIGNAL ;
    PORT
      LAYER Metal3 ;
        RECT  1099.6 194.26 1100 194.66 ;
    END
  END out_block_o[503]
  PIN out_block_o[504]
    DIRECTION OUTPUT ;
    USE SIGNAL ;
    PORT
      LAYER Metal3 ;
        RECT  1099.6 192.58 1100 192.98 ;
    END
  END out_block_o[504]
  PIN out_block_o[505]
    DIRECTION OUTPUT ;
    USE SIGNAL ;
    PORT
      LAYER Metal3 ;
        RECT  1099.6 190.9 1100 191.3 ;
    END
  END out_block_o[505]
  PIN out_block_o[506]
    DIRECTION OUTPUT ;
    USE SIGNAL ;
    PORT
      LAYER Metal3 ;
        RECT  1099.6 189.22 1100 189.62 ;
    END
  END out_block_o[506]
  PIN out_block_o[507]
    DIRECTION OUTPUT ;
    USE SIGNAL ;
    PORT
      LAYER Metal3 ;
        RECT  1099.6 187.54 1100 187.94 ;
    END
  END out_block_o[507]
  PIN out_block_o[508]
    DIRECTION OUTPUT ;
    USE SIGNAL ;
    PORT
      LAYER Metal3 ;
        RECT  1099.6 185.86 1100 186.26 ;
    END
  END out_block_o[508]
  PIN out_block_o[509]
    DIRECTION OUTPUT ;
    USE SIGNAL ;
    PORT
      LAYER Metal3 ;
        RECT  1099.6 184.18 1100 184.58 ;
    END
  END out_block_o[509]
  PIN out_block_o[50]
    DIRECTION OUTPUT ;
    USE SIGNAL ;
    PORT
      LAYER Metal3 ;
        RECT  1099.6 955.3 1100 955.7 ;
    END
  END out_block_o[50]
  PIN out_block_o[510]
    DIRECTION OUTPUT ;
    USE SIGNAL ;
    PORT
      LAYER Metal3 ;
        RECT  1099.6 182.5 1100 182.9 ;
    END
  END out_block_o[510]
  PIN out_block_o[511]
    DIRECTION OUTPUT ;
    USE SIGNAL ;
    PORT
      LAYER Metal3 ;
        RECT  1099.6 180.82 1100 181.22 ;
    END
  END out_block_o[511]
  PIN out_block_o[512]
    DIRECTION OUTPUT ;
    USE SIGNAL ;
    PORT
      LAYER Metal3 ;
        RECT  1099.6 179.14 1100 179.54 ;
    END
  END out_block_o[512]
  PIN out_block_o[513]
    DIRECTION OUTPUT ;
    USE SIGNAL ;
    PORT
      LAYER Metal3 ;
        RECT  1099.6 177.46 1100 177.86 ;
    END
  END out_block_o[513]
  PIN out_block_o[514]
    DIRECTION OUTPUT ;
    USE SIGNAL ;
    PORT
      LAYER Metal3 ;
        RECT  1099.6 175.78 1100 176.18 ;
    END
  END out_block_o[514]
  PIN out_block_o[515]
    DIRECTION OUTPUT ;
    USE SIGNAL ;
    PORT
      LAYER Metal3 ;
        RECT  1099.6 174.1 1100 174.5 ;
    END
  END out_block_o[515]
  PIN out_block_o[516]
    DIRECTION OUTPUT ;
    USE SIGNAL ;
    PORT
      LAYER Metal3 ;
        RECT  1099.6 172.42 1100 172.82 ;
    END
  END out_block_o[516]
  PIN out_block_o[517]
    DIRECTION OUTPUT ;
    USE SIGNAL ;
    PORT
      LAYER Metal3 ;
        RECT  1099.6 170.74 1100 171.14 ;
    END
  END out_block_o[517]
  PIN out_block_o[518]
    DIRECTION OUTPUT ;
    USE SIGNAL ;
    PORT
      LAYER Metal3 ;
        RECT  1099.6 169.06 1100 169.46 ;
    END
  END out_block_o[518]
  PIN out_block_o[519]
    DIRECTION OUTPUT ;
    USE SIGNAL ;
    PORT
      LAYER Metal3 ;
        RECT  1099.6 167.38 1100 167.78 ;
    END
  END out_block_o[519]
  PIN out_block_o[51]
    DIRECTION OUTPUT ;
    USE SIGNAL ;
    PORT
      LAYER Metal3 ;
        RECT  1099.6 953.62 1100 954.02 ;
    END
  END out_block_o[51]
  PIN out_block_o[520]
    DIRECTION OUTPUT ;
    USE SIGNAL ;
    PORT
      LAYER Metal3 ;
        RECT  1099.6 165.7 1100 166.1 ;
    END
  END out_block_o[520]
  PIN out_block_o[521]
    DIRECTION OUTPUT ;
    USE SIGNAL ;
    PORT
      LAYER Metal3 ;
        RECT  1099.6 164.02 1100 164.42 ;
    END
  END out_block_o[521]
  PIN out_block_o[522]
    DIRECTION OUTPUT ;
    USE SIGNAL ;
    PORT
      LAYER Metal3 ;
        RECT  1099.6 162.34 1100 162.74 ;
    END
  END out_block_o[522]
  PIN out_block_o[523]
    DIRECTION OUTPUT ;
    USE SIGNAL ;
    PORT
      LAYER Metal3 ;
        RECT  1099.6 160.66 1100 161.06 ;
    END
  END out_block_o[523]
  PIN out_block_o[524]
    DIRECTION OUTPUT ;
    USE SIGNAL ;
    PORT
      LAYER Metal3 ;
        RECT  1099.6 158.98 1100 159.38 ;
    END
  END out_block_o[524]
  PIN out_block_o[525]
    DIRECTION OUTPUT ;
    USE SIGNAL ;
    PORT
      LAYER Metal3 ;
        RECT  1099.6 157.3 1100 157.7 ;
    END
  END out_block_o[525]
  PIN out_block_o[526]
    DIRECTION OUTPUT ;
    USE SIGNAL ;
    PORT
      LAYER Metal3 ;
        RECT  1099.6 155.62 1100 156.02 ;
    END
  END out_block_o[526]
  PIN out_block_o[527]
    DIRECTION OUTPUT ;
    USE SIGNAL ;
    PORT
      LAYER Metal3 ;
        RECT  1099.6 153.94 1100 154.34 ;
    END
  END out_block_o[527]
  PIN out_block_o[528]
    DIRECTION OUTPUT ;
    USE SIGNAL ;
    PORT
      LAYER Metal3 ;
        RECT  1099.6 152.26 1100 152.66 ;
    END
  END out_block_o[528]
  PIN out_block_o[529]
    DIRECTION OUTPUT ;
    USE SIGNAL ;
    PORT
      LAYER Metal3 ;
        RECT  1099.6 150.58 1100 150.98 ;
    END
  END out_block_o[529]
  PIN out_block_o[52]
    DIRECTION OUTPUT ;
    USE SIGNAL ;
    PORT
      LAYER Metal3 ;
        RECT  1099.6 951.94 1100 952.34 ;
    END
  END out_block_o[52]
  PIN out_block_o[530]
    DIRECTION OUTPUT ;
    USE SIGNAL ;
    PORT
      LAYER Metal3 ;
        RECT  1099.6 148.9 1100 149.3 ;
    END
  END out_block_o[530]
  PIN out_block_o[531]
    DIRECTION OUTPUT ;
    USE SIGNAL ;
    PORT
      LAYER Metal3 ;
        RECT  1099.6 147.22 1100 147.62 ;
    END
  END out_block_o[531]
  PIN out_block_o[532]
    DIRECTION OUTPUT ;
    USE SIGNAL ;
    PORT
      LAYER Metal3 ;
        RECT  1099.6 145.54 1100 145.94 ;
    END
  END out_block_o[532]
  PIN out_block_o[533]
    DIRECTION OUTPUT ;
    USE SIGNAL ;
    PORT
      LAYER Metal3 ;
        RECT  1099.6 143.86 1100 144.26 ;
    END
  END out_block_o[533]
  PIN out_block_o[534]
    DIRECTION OUTPUT ;
    USE SIGNAL ;
    PORT
      LAYER Metal3 ;
        RECT  1099.6 142.18 1100 142.58 ;
    END
  END out_block_o[534]
  PIN out_block_o[535]
    DIRECTION OUTPUT ;
    USE SIGNAL ;
    PORT
      LAYER Metal3 ;
        RECT  1099.6 140.5 1100 140.9 ;
    END
  END out_block_o[535]
  PIN out_block_o[536]
    DIRECTION OUTPUT ;
    USE SIGNAL ;
    PORT
      LAYER Metal3 ;
        RECT  1099.6 138.82 1100 139.22 ;
    END
  END out_block_o[536]
  PIN out_block_o[537]
    DIRECTION OUTPUT ;
    USE SIGNAL ;
    PORT
      LAYER Metal3 ;
        RECT  1099.6 137.14 1100 137.54 ;
    END
  END out_block_o[537]
  PIN out_block_o[538]
    DIRECTION OUTPUT ;
    USE SIGNAL ;
    PORT
      LAYER Metal3 ;
        RECT  1099.6 135.46 1100 135.86 ;
    END
  END out_block_o[538]
  PIN out_block_o[539]
    DIRECTION OUTPUT ;
    USE SIGNAL ;
    PORT
      LAYER Metal3 ;
        RECT  1099.6 133.78 1100 134.18 ;
    END
  END out_block_o[539]
  PIN out_block_o[53]
    DIRECTION OUTPUT ;
    USE SIGNAL ;
    PORT
      LAYER Metal3 ;
        RECT  1099.6 950.26 1100 950.66 ;
    END
  END out_block_o[53]
  PIN out_block_o[540]
    DIRECTION OUTPUT ;
    USE SIGNAL ;
    PORT
      LAYER Metal3 ;
        RECT  1099.6 132.1 1100 132.5 ;
    END
  END out_block_o[540]
  PIN out_block_o[541]
    DIRECTION OUTPUT ;
    USE SIGNAL ;
    PORT
      LAYER Metal3 ;
        RECT  1099.6 130.42 1100 130.82 ;
    END
  END out_block_o[541]
  PIN out_block_o[542]
    DIRECTION OUTPUT ;
    USE SIGNAL ;
    PORT
      LAYER Metal3 ;
        RECT  1099.6 128.74 1100 129.14 ;
    END
  END out_block_o[542]
  PIN out_block_o[543]
    DIRECTION OUTPUT ;
    USE SIGNAL ;
    PORT
      LAYER Metal3 ;
        RECT  1099.6 127.06 1100 127.46 ;
    END
  END out_block_o[543]
  PIN out_block_o[544]
    DIRECTION OUTPUT ;
    USE SIGNAL ;
    PORT
      LAYER Metal3 ;
        RECT  1099.6 125.38 1100 125.78 ;
    END
  END out_block_o[544]
  PIN out_block_o[545]
    DIRECTION OUTPUT ;
    USE SIGNAL ;
    PORT
      LAYER Metal3 ;
        RECT  1099.6 123.7 1100 124.1 ;
    END
  END out_block_o[545]
  PIN out_block_o[546]
    DIRECTION OUTPUT ;
    USE SIGNAL ;
    PORT
      LAYER Metal3 ;
        RECT  1099.6 122.02 1100 122.42 ;
    END
  END out_block_o[546]
  PIN out_block_o[547]
    DIRECTION OUTPUT ;
    USE SIGNAL ;
    PORT
      LAYER Metal3 ;
        RECT  1099.6 120.34 1100 120.74 ;
    END
  END out_block_o[547]
  PIN out_block_o[548]
    DIRECTION OUTPUT ;
    USE SIGNAL ;
    PORT
      LAYER Metal3 ;
        RECT  1099.6 118.66 1100 119.06 ;
    END
  END out_block_o[548]
  PIN out_block_o[549]
    DIRECTION OUTPUT ;
    USE SIGNAL ;
    PORT
      LAYER Metal3 ;
        RECT  1099.6 116.98 1100 117.38 ;
    END
  END out_block_o[549]
  PIN out_block_o[54]
    DIRECTION OUTPUT ;
    USE SIGNAL ;
    PORT
      LAYER Metal3 ;
        RECT  1099.6 948.58 1100 948.98 ;
    END
  END out_block_o[54]
  PIN out_block_o[550]
    DIRECTION OUTPUT ;
    USE SIGNAL ;
    PORT
      LAYER Metal3 ;
        RECT  1099.6 115.3 1100 115.7 ;
    END
  END out_block_o[550]
  PIN out_block_o[551]
    DIRECTION OUTPUT ;
    USE SIGNAL ;
    PORT
      LAYER Metal3 ;
        RECT  1099.6 113.62 1100 114.02 ;
    END
  END out_block_o[551]
  PIN out_block_o[552]
    DIRECTION OUTPUT ;
    USE SIGNAL ;
    PORT
      LAYER Metal3 ;
        RECT  1099.6 111.94 1100 112.34 ;
    END
  END out_block_o[552]
  PIN out_block_o[553]
    DIRECTION OUTPUT ;
    USE SIGNAL ;
    PORT
      LAYER Metal3 ;
        RECT  1099.6 110.26 1100 110.66 ;
    END
  END out_block_o[553]
  PIN out_block_o[554]
    DIRECTION OUTPUT ;
    USE SIGNAL ;
    PORT
      LAYER Metal3 ;
        RECT  1099.6 108.58 1100 108.98 ;
    END
  END out_block_o[554]
  PIN out_block_o[555]
    DIRECTION OUTPUT ;
    USE SIGNAL ;
    PORT
      LAYER Metal3 ;
        RECT  1099.6 106.9 1100 107.3 ;
    END
  END out_block_o[555]
  PIN out_block_o[556]
    DIRECTION OUTPUT ;
    USE SIGNAL ;
    PORT
      LAYER Metal3 ;
        RECT  1099.6 105.22 1100 105.62 ;
    END
  END out_block_o[556]
  PIN out_block_o[557]
    DIRECTION OUTPUT ;
    USE SIGNAL ;
    PORT
      LAYER Metal3 ;
        RECT  1099.6 103.54 1100 103.94 ;
    END
  END out_block_o[557]
  PIN out_block_o[558]
    DIRECTION OUTPUT ;
    USE SIGNAL ;
    PORT
      LAYER Metal3 ;
        RECT  1099.6 101.86 1100 102.26 ;
    END
  END out_block_o[558]
  PIN out_block_o[559]
    DIRECTION OUTPUT ;
    USE SIGNAL ;
    PORT
      LAYER Metal3 ;
        RECT  1099.6 100.18 1100 100.58 ;
    END
  END out_block_o[559]
  PIN out_block_o[55]
    DIRECTION OUTPUT ;
    USE SIGNAL ;
    PORT
      LAYER Metal3 ;
        RECT  1099.6 946.9 1100 947.3 ;
    END
  END out_block_o[55]
  PIN out_block_o[560]
    DIRECTION OUTPUT ;
    USE SIGNAL ;
    PORT
      LAYER Metal3 ;
        RECT  1099.6 98.5 1100 98.9 ;
    END
  END out_block_o[560]
  PIN out_block_o[561]
    DIRECTION OUTPUT ;
    USE SIGNAL ;
    PORT
      LAYER Metal3 ;
        RECT  1099.6 96.82 1100 97.22 ;
    END
  END out_block_o[561]
  PIN out_block_o[562]
    DIRECTION OUTPUT ;
    USE SIGNAL ;
    PORT
      LAYER Metal3 ;
        RECT  1099.6 95.14 1100 95.54 ;
    END
  END out_block_o[562]
  PIN out_block_o[563]
    DIRECTION OUTPUT ;
    USE SIGNAL ;
    PORT
      LAYER Metal3 ;
        RECT  1099.6 93.46 1100 93.86 ;
    END
  END out_block_o[563]
  PIN out_block_o[564]
    DIRECTION OUTPUT ;
    USE SIGNAL ;
    PORT
      LAYER Metal3 ;
        RECT  1099.6 91.78 1100 92.18 ;
    END
  END out_block_o[564]
  PIN out_block_o[565]
    DIRECTION OUTPUT ;
    USE SIGNAL ;
    PORT
      LAYER Metal3 ;
        RECT  1099.6 90.1 1100 90.5 ;
    END
  END out_block_o[565]
  PIN out_block_o[566]
    DIRECTION OUTPUT ;
    USE SIGNAL ;
    PORT
      LAYER Metal3 ;
        RECT  1099.6 88.42 1100 88.82 ;
    END
  END out_block_o[566]
  PIN out_block_o[567]
    DIRECTION OUTPUT ;
    USE SIGNAL ;
    PORT
      LAYER Metal3 ;
        RECT  1099.6 86.74 1100 87.14 ;
    END
  END out_block_o[567]
  PIN out_block_o[568]
    DIRECTION OUTPUT ;
    USE SIGNAL ;
    PORT
      LAYER Metal3 ;
        RECT  1099.6 85.06 1100 85.46 ;
    END
  END out_block_o[568]
  PIN out_block_o[569]
    DIRECTION OUTPUT ;
    USE SIGNAL ;
    PORT
      LAYER Metal3 ;
        RECT  1099.6 83.38 1100 83.78 ;
    END
  END out_block_o[569]
  PIN out_block_o[56]
    DIRECTION OUTPUT ;
    USE SIGNAL ;
    PORT
      LAYER Metal3 ;
        RECT  1099.6 945.22 1100 945.62 ;
    END
  END out_block_o[56]
  PIN out_block_o[570]
    DIRECTION OUTPUT ;
    USE SIGNAL ;
    PORT
      LAYER Metal3 ;
        RECT  1099.6 81.7 1100 82.1 ;
    END
  END out_block_o[570]
  PIN out_block_o[571]
    DIRECTION OUTPUT ;
    USE SIGNAL ;
    PORT
      LAYER Metal3 ;
        RECT  1099.6 80.02 1100 80.42 ;
    END
  END out_block_o[571]
  PIN out_block_o[57]
    DIRECTION OUTPUT ;
    USE SIGNAL ;
    PORT
      LAYER Metal3 ;
        RECT  1099.6 943.54 1100 943.94 ;
    END
  END out_block_o[57]
  PIN out_block_o[58]
    DIRECTION OUTPUT ;
    USE SIGNAL ;
    PORT
      LAYER Metal3 ;
        RECT  1099.6 941.86 1100 942.26 ;
    END
  END out_block_o[58]
  PIN out_block_o[59]
    DIRECTION OUTPUT ;
    USE SIGNAL ;
    PORT
      LAYER Metal3 ;
        RECT  1099.6 940.18 1100 940.58 ;
    END
  END out_block_o[59]
  PIN out_block_o[5]
    DIRECTION OUTPUT ;
    USE SIGNAL ;
    PORT
      LAYER Metal3 ;
        RECT  1099.6 1030.9 1100 1031.3 ;
    END
  END out_block_o[5]
  PIN out_block_o[60]
    DIRECTION OUTPUT ;
    USE SIGNAL ;
    PORT
      LAYER Metal3 ;
        RECT  1099.6 938.5 1100 938.9 ;
    END
  END out_block_o[60]
  PIN out_block_o[61]
    DIRECTION OUTPUT ;
    USE SIGNAL ;
    PORT
      LAYER Metal3 ;
        RECT  1099.6 936.82 1100 937.22 ;
    END
  END out_block_o[61]
  PIN out_block_o[62]
    DIRECTION OUTPUT ;
    USE SIGNAL ;
    PORT
      LAYER Metal3 ;
        RECT  1099.6 935.14 1100 935.54 ;
    END
  END out_block_o[62]
  PIN out_block_o[63]
    DIRECTION OUTPUT ;
    USE SIGNAL ;
    PORT
      LAYER Metal3 ;
        RECT  1099.6 933.46 1100 933.86 ;
    END
  END out_block_o[63]
  PIN out_block_o[64]
    DIRECTION OUTPUT ;
    USE SIGNAL ;
    PORT
      LAYER Metal3 ;
        RECT  1099.6 931.78 1100 932.18 ;
    END
  END out_block_o[64]
  PIN out_block_o[65]
    DIRECTION OUTPUT ;
    USE SIGNAL ;
    PORT
      LAYER Metal3 ;
        RECT  1099.6 930.1 1100 930.5 ;
    END
  END out_block_o[65]
  PIN out_block_o[66]
    DIRECTION OUTPUT ;
    USE SIGNAL ;
    PORT
      LAYER Metal3 ;
        RECT  1099.6 928.42 1100 928.82 ;
    END
  END out_block_o[66]
  PIN out_block_o[67]
    DIRECTION OUTPUT ;
    USE SIGNAL ;
    PORT
      LAYER Metal3 ;
        RECT  1099.6 926.74 1100 927.14 ;
    END
  END out_block_o[67]
  PIN out_block_o[68]
    DIRECTION OUTPUT ;
    USE SIGNAL ;
    PORT
      LAYER Metal3 ;
        RECT  1099.6 925.06 1100 925.46 ;
    END
  END out_block_o[68]
  PIN out_block_o[69]
    DIRECTION OUTPUT ;
    USE SIGNAL ;
    PORT
      LAYER Metal3 ;
        RECT  1099.6 923.38 1100 923.78 ;
    END
  END out_block_o[69]
  PIN out_block_o[6]
    DIRECTION OUTPUT ;
    USE SIGNAL ;
    PORT
      LAYER Metal3 ;
        RECT  1099.6 1029.22 1100 1029.62 ;
    END
  END out_block_o[6]
  PIN out_block_o[70]
    DIRECTION OUTPUT ;
    USE SIGNAL ;
    PORT
      LAYER Metal3 ;
        RECT  1099.6 921.7 1100 922.1 ;
    END
  END out_block_o[70]
  PIN out_block_o[71]
    DIRECTION OUTPUT ;
    USE SIGNAL ;
    PORT
      LAYER Metal3 ;
        RECT  1099.6 920.02 1100 920.42 ;
    END
  END out_block_o[71]
  PIN out_block_o[72]
    DIRECTION OUTPUT ;
    USE SIGNAL ;
    PORT
      LAYER Metal3 ;
        RECT  1099.6 918.34 1100 918.74 ;
    END
  END out_block_o[72]
  PIN out_block_o[73]
    DIRECTION OUTPUT ;
    USE SIGNAL ;
    PORT
      LAYER Metal3 ;
        RECT  1099.6 916.66 1100 917.06 ;
    END
  END out_block_o[73]
  PIN out_block_o[74]
    DIRECTION OUTPUT ;
    USE SIGNAL ;
    PORT
      LAYER Metal3 ;
        RECT  1099.6 914.98 1100 915.38 ;
    END
  END out_block_o[74]
  PIN out_block_o[75]
    DIRECTION OUTPUT ;
    USE SIGNAL ;
    PORT
      LAYER Metal3 ;
        RECT  1099.6 913.3 1100 913.7 ;
    END
  END out_block_o[75]
  PIN out_block_o[76]
    DIRECTION OUTPUT ;
    USE SIGNAL ;
    PORT
      LAYER Metal3 ;
        RECT  1099.6 911.62 1100 912.02 ;
    END
  END out_block_o[76]
  PIN out_block_o[77]
    DIRECTION OUTPUT ;
    USE SIGNAL ;
    PORT
      LAYER Metal3 ;
        RECT  1099.6 909.94 1100 910.34 ;
    END
  END out_block_o[77]
  PIN out_block_o[78]
    DIRECTION OUTPUT ;
    USE SIGNAL ;
    PORT
      LAYER Metal3 ;
        RECT  1099.6 908.26 1100 908.66 ;
    END
  END out_block_o[78]
  PIN out_block_o[79]
    DIRECTION OUTPUT ;
    USE SIGNAL ;
    PORT
      LAYER Metal3 ;
        RECT  1099.6 906.58 1100 906.98 ;
    END
  END out_block_o[79]
  PIN out_block_o[7]
    DIRECTION OUTPUT ;
    USE SIGNAL ;
    PORT
      LAYER Metal3 ;
        RECT  1099.6 1027.54 1100 1027.94 ;
    END
  END out_block_o[7]
  PIN out_block_o[80]
    DIRECTION OUTPUT ;
    USE SIGNAL ;
    PORT
      LAYER Metal3 ;
        RECT  1099.6 904.9 1100 905.3 ;
    END
  END out_block_o[80]
  PIN out_block_o[81]
    DIRECTION OUTPUT ;
    USE SIGNAL ;
    PORT
      LAYER Metal3 ;
        RECT  1099.6 903.22 1100 903.62 ;
    END
  END out_block_o[81]
  PIN out_block_o[82]
    DIRECTION OUTPUT ;
    USE SIGNAL ;
    PORT
      LAYER Metal3 ;
        RECT  1099.6 901.54 1100 901.94 ;
    END
  END out_block_o[82]
  PIN out_block_o[83]
    DIRECTION OUTPUT ;
    USE SIGNAL ;
    PORT
      LAYER Metal3 ;
        RECT  1099.6 899.86 1100 900.26 ;
    END
  END out_block_o[83]
  PIN out_block_o[84]
    DIRECTION OUTPUT ;
    USE SIGNAL ;
    PORT
      LAYER Metal3 ;
        RECT  1099.6 898.18 1100 898.58 ;
    END
  END out_block_o[84]
  PIN out_block_o[85]
    DIRECTION OUTPUT ;
    USE SIGNAL ;
    PORT
      LAYER Metal3 ;
        RECT  1099.6 896.5 1100 896.9 ;
    END
  END out_block_o[85]
  PIN out_block_o[86]
    DIRECTION OUTPUT ;
    USE SIGNAL ;
    PORT
      LAYER Metal3 ;
        RECT  1099.6 894.82 1100 895.22 ;
    END
  END out_block_o[86]
  PIN out_block_o[87]
    DIRECTION OUTPUT ;
    USE SIGNAL ;
    PORT
      LAYER Metal3 ;
        RECT  1099.6 893.14 1100 893.54 ;
    END
  END out_block_o[87]
  PIN out_block_o[88]
    DIRECTION OUTPUT ;
    USE SIGNAL ;
    PORT
      LAYER Metal3 ;
        RECT  1099.6 891.46 1100 891.86 ;
    END
  END out_block_o[88]
  PIN out_block_o[89]
    DIRECTION OUTPUT ;
    USE SIGNAL ;
    PORT
      LAYER Metal3 ;
        RECT  1099.6 889.78 1100 890.18 ;
    END
  END out_block_o[89]
  PIN out_block_o[8]
    DIRECTION OUTPUT ;
    USE SIGNAL ;
    PORT
      LAYER Metal3 ;
        RECT  1099.6 1025.86 1100 1026.26 ;
    END
  END out_block_o[8]
  PIN out_block_o[90]
    DIRECTION OUTPUT ;
    USE SIGNAL ;
    PORT
      LAYER Metal3 ;
        RECT  1099.6 888.1 1100 888.5 ;
    END
  END out_block_o[90]
  PIN out_block_o[91]
    DIRECTION OUTPUT ;
    USE SIGNAL ;
    PORT
      LAYER Metal3 ;
        RECT  1099.6 886.42 1100 886.82 ;
    END
  END out_block_o[91]
  PIN out_block_o[92]
    DIRECTION OUTPUT ;
    USE SIGNAL ;
    PORT
      LAYER Metal3 ;
        RECT  1099.6 884.74 1100 885.14 ;
    END
  END out_block_o[92]
  PIN out_block_o[93]
    DIRECTION OUTPUT ;
    USE SIGNAL ;
    PORT
      LAYER Metal3 ;
        RECT  1099.6 883.06 1100 883.46 ;
    END
  END out_block_o[93]
  PIN out_block_o[94]
    DIRECTION OUTPUT ;
    USE SIGNAL ;
    PORT
      LAYER Metal3 ;
        RECT  1099.6 881.38 1100 881.78 ;
    END
  END out_block_o[94]
  PIN out_block_o[95]
    DIRECTION OUTPUT ;
    USE SIGNAL ;
    PORT
      LAYER Metal3 ;
        RECT  1099.6 879.7 1100 880.1 ;
    END
  END out_block_o[95]
  PIN out_block_o[96]
    DIRECTION OUTPUT ;
    USE SIGNAL ;
    PORT
      LAYER Metal3 ;
        RECT  1099.6 878.02 1100 878.42 ;
    END
  END out_block_o[96]
  PIN out_block_o[97]
    DIRECTION OUTPUT ;
    USE SIGNAL ;
    PORT
      LAYER Metal3 ;
        RECT  1099.6 876.34 1100 876.74 ;
    END
  END out_block_o[97]
  PIN out_block_o[98]
    DIRECTION OUTPUT ;
    USE SIGNAL ;
    PORT
      LAYER Metal3 ;
        RECT  1099.6 874.66 1100 875.06 ;
    END
  END out_block_o[98]
  PIN out_block_o[99]
    DIRECTION OUTPUT ;
    USE SIGNAL ;
    PORT
      LAYER Metal3 ;
        RECT  1099.6 872.98 1100 873.38 ;
    END
  END out_block_o[99]
  PIN out_block_o[9]
    DIRECTION OUTPUT ;
    USE SIGNAL ;
    PORT
      LAYER Metal3 ;
        RECT  1099.6 1024.18 1100 1024.58 ;
    END
  END out_block_o[9]
  PIN out_count_o[0]
    DIRECTION OUTPUT ;
    USE SIGNAL ;
    PORT
      LAYER Metal3 ;
        RECT  1099.6 1046.02 1100 1046.42 ;
    END
  END out_count_o[0]
  PIN out_count_o[1]
    DIRECTION OUTPUT ;
    USE SIGNAL ;
    PORT
      LAYER Metal3 ;
        RECT  1099.6 1044.34 1100 1044.74 ;
    END
  END out_count_o[1]
  PIN out_count_o[2]
    DIRECTION OUTPUT ;
    USE SIGNAL ;
    PORT
      LAYER Metal3 ;
        RECT  1099.6 1042.66 1100 1043.06 ;
    END
  END out_count_o[2]
  PIN out_count_o[3]
    DIRECTION OUTPUT ;
    USE SIGNAL ;
    PORT
      LAYER Metal3 ;
        RECT  1099.6 1040.98 1100 1041.38 ;
    END
  END out_count_o[3]
  PIN out_ready_i
    DIRECTION INPUT ;
    USE SIGNAL ;
    PORT
      LAYER Metal3 ;
        RECT  1099.6 1049.38 1100 1049.78 ;
    END
  END out_ready_i
  PIN out_valid_o
    DIRECTION OUTPUT ;
    USE SIGNAL ;
    PORT
      LAYER Metal3 ;
        RECT  1099.6 1047.7 1100 1048.1 ;
    END
  END out_valid_o
  PIN predict_pc_o[0]
    DIRECTION OUTPUT ;
    USE SIGNAL ;
    PORT
      LAYER Metal3 ;
        RECT  0 1049.38 0.4 1049.78 ;
    END
  END predict_pc_o[0]
  PIN predict_pc_o[10]
    DIRECTION OUTPUT ;
    USE SIGNAL ;
    PORT
      LAYER Metal3 ;
        RECT  0 1032.58 0.4 1032.98 ;
    END
  END predict_pc_o[10]
  PIN predict_pc_o[11]
    DIRECTION OUTPUT ;
    USE SIGNAL ;
    PORT
      LAYER Metal3 ;
        RECT  0 1030.9 0.4 1031.3 ;
    END
  END predict_pc_o[11]
  PIN predict_pc_o[12]
    DIRECTION OUTPUT ;
    USE SIGNAL ;
    PORT
      LAYER Metal3 ;
        RECT  0 1029.22 0.4 1029.62 ;
    END
  END predict_pc_o[12]
  PIN predict_pc_o[13]
    DIRECTION OUTPUT ;
    USE SIGNAL ;
    PORT
      LAYER Metal3 ;
        RECT  0 1027.54 0.4 1027.94 ;
    END
  END predict_pc_o[13]
  PIN predict_pc_o[14]
    DIRECTION OUTPUT ;
    USE SIGNAL ;
    PORT
      LAYER Metal3 ;
        RECT  0 1025.86 0.4 1026.26 ;
    END
  END predict_pc_o[14]
  PIN predict_pc_o[15]
    DIRECTION OUTPUT ;
    USE SIGNAL ;
    PORT
      LAYER Metal3 ;
        RECT  0 1024.18 0.4 1024.58 ;
    END
  END predict_pc_o[15]
  PIN predict_pc_o[16]
    DIRECTION OUTPUT ;
    USE SIGNAL ;
    PORT
      LAYER Metal3 ;
        RECT  0 1022.5 0.4 1022.9 ;
    END
  END predict_pc_o[16]
  PIN predict_pc_o[17]
    DIRECTION OUTPUT ;
    USE SIGNAL ;
    PORT
      LAYER Metal3 ;
        RECT  0 1020.82 0.4 1021.22 ;
    END
  END predict_pc_o[17]
  PIN predict_pc_o[18]
    DIRECTION OUTPUT ;
    USE SIGNAL ;
    PORT
      LAYER Metal3 ;
        RECT  0 1019.14 0.4 1019.54 ;
    END
  END predict_pc_o[18]
  PIN predict_pc_o[19]
    DIRECTION OUTPUT ;
    USE SIGNAL ;
    PORT
      LAYER Metal3 ;
        RECT  0 1017.46 0.4 1017.86 ;
    END
  END predict_pc_o[19]
  PIN predict_pc_o[1]
    DIRECTION OUTPUT ;
    USE SIGNAL ;
    PORT
      LAYER Metal3 ;
        RECT  0 1047.7 0.4 1048.1 ;
    END
  END predict_pc_o[1]
  PIN predict_pc_o[20]
    DIRECTION OUTPUT ;
    USE SIGNAL ;
    PORT
      LAYER Metal3 ;
        RECT  0 1015.78 0.4 1016.18 ;
    END
  END predict_pc_o[20]
  PIN predict_pc_o[21]
    DIRECTION OUTPUT ;
    USE SIGNAL ;
    PORT
      LAYER Metal3 ;
        RECT  0 1014.1 0.4 1014.5 ;
    END
  END predict_pc_o[21]
  PIN predict_pc_o[22]
    DIRECTION OUTPUT ;
    USE SIGNAL ;
    PORT
      LAYER Metal3 ;
        RECT  0 1012.42 0.4 1012.82 ;
    END
  END predict_pc_o[22]
  PIN predict_pc_o[23]
    DIRECTION OUTPUT ;
    USE SIGNAL ;
    PORT
      LAYER Metal3 ;
        RECT  0 1010.74 0.4 1011.14 ;
    END
  END predict_pc_o[23]
  PIN predict_pc_o[24]
    DIRECTION OUTPUT ;
    USE SIGNAL ;
    PORT
      LAYER Metal3 ;
        RECT  0 1009.06 0.4 1009.46 ;
    END
  END predict_pc_o[24]
  PIN predict_pc_o[25]
    DIRECTION OUTPUT ;
    USE SIGNAL ;
    PORT
      LAYER Metal3 ;
        RECT  0 1007.38 0.4 1007.78 ;
    END
  END predict_pc_o[25]
  PIN predict_pc_o[26]
    DIRECTION OUTPUT ;
    USE SIGNAL ;
    PORT
      LAYER Metal3 ;
        RECT  0 1005.7 0.4 1006.1 ;
    END
  END predict_pc_o[26]
  PIN predict_pc_o[27]
    DIRECTION OUTPUT ;
    USE SIGNAL ;
    PORT
      LAYER Metal3 ;
        RECT  0 1004.02 0.4 1004.42 ;
    END
  END predict_pc_o[27]
  PIN predict_pc_o[28]
    DIRECTION OUTPUT ;
    USE SIGNAL ;
    PORT
      LAYER Metal3 ;
        RECT  0 1002.34 0.4 1002.74 ;
    END
  END predict_pc_o[28]
  PIN predict_pc_o[29]
    DIRECTION OUTPUT ;
    USE SIGNAL ;
    PORT
      LAYER Metal3 ;
        RECT  0 1000.66 0.4 1001.06 ;
    END
  END predict_pc_o[29]
  PIN predict_pc_o[2]
    DIRECTION OUTPUT ;
    USE SIGNAL ;
    PORT
      LAYER Metal3 ;
        RECT  0 1046.02 0.4 1046.42 ;
    END
  END predict_pc_o[2]
  PIN predict_pc_o[30]
    DIRECTION OUTPUT ;
    USE SIGNAL ;
    PORT
      LAYER Metal3 ;
        RECT  0 998.98 0.4 999.38 ;
    END
  END predict_pc_o[30]
  PIN predict_pc_o[31]
    DIRECTION OUTPUT ;
    USE SIGNAL ;
    PORT
      LAYER Metal3 ;
        RECT  0 997.3 0.4 997.7 ;
    END
  END predict_pc_o[31]
  PIN predict_pc_o[3]
    DIRECTION OUTPUT ;
    USE SIGNAL ;
    PORT
      LAYER Metal3 ;
        RECT  0 1044.34 0.4 1044.74 ;
    END
  END predict_pc_o[3]
  PIN predict_pc_o[4]
    DIRECTION OUTPUT ;
    USE SIGNAL ;
    PORT
      LAYER Metal3 ;
        RECT  0 1042.66 0.4 1043.06 ;
    END
  END predict_pc_o[4]
  PIN predict_pc_o[5]
    DIRECTION OUTPUT ;
    USE SIGNAL ;
    PORT
      LAYER Metal3 ;
        RECT  0 1040.98 0.4 1041.38 ;
    END
  END predict_pc_o[5]
  PIN predict_pc_o[6]
    DIRECTION OUTPUT ;
    USE SIGNAL ;
    PORT
      LAYER Metal3 ;
        RECT  0 1039.3 0.4 1039.7 ;
    END
  END predict_pc_o[6]
  PIN predict_pc_o[7]
    DIRECTION OUTPUT ;
    USE SIGNAL ;
    PORT
      LAYER Metal3 ;
        RECT  0 1037.62 0.4 1038.02 ;
    END
  END predict_pc_o[7]
  PIN predict_pc_o[8]
    DIRECTION OUTPUT ;
    USE SIGNAL ;
    PORT
      LAYER Metal3 ;
        RECT  0 1035.94 0.4 1036.34 ;
    END
  END predict_pc_o[8]
  PIN predict_pc_o[9]
    DIRECTION OUTPUT ;
    USE SIGNAL ;
    PORT
      LAYER Metal3 ;
        RECT  0 1034.26 0.4 1034.66 ;
    END
  END predict_pc_o[9]
  PIN predict_valid_o
    DIRECTION OUTPUT ;
    USE SIGNAL ;
    PORT
      LAYER Metal3 ;
        RECT  0 945.22 0.4 945.62 ;
    END
  END predict_valid_o
  PIN recovery_i.ghist[0]
    DIRECTION INPUT ;
    USE SIGNAL ;
    PORT
      LAYER Metal2 ;
        RECT  906.52 1099.6 906.92 1100 ;
    END
  END recovery_i.ghist[0]
  PIN recovery_i.ghist[10]
    DIRECTION INPUT ;
    USE SIGNAL ;
    PORT
      LAYER Metal2 ;
        RECT  950.68 1099.6 951.08 1100 ;
    END
  END recovery_i.ghist[10]
  PIN recovery_i.ghist[11]
    DIRECTION INPUT ;
    USE SIGNAL ;
    PORT
      LAYER Metal2 ;
        RECT  954.52 1099.6 954.92 1100 ;
    END
  END recovery_i.ghist[11]
  PIN recovery_i.ghist[12]
    DIRECTION INPUT ;
    USE SIGNAL ;
    PORT
      LAYER Metal2 ;
        RECT  958.36 1099.6 958.76 1100 ;
    END
  END recovery_i.ghist[12]
  PIN recovery_i.ghist[13]
    DIRECTION INPUT ;
    USE SIGNAL ;
    PORT
      LAYER Metal2 ;
        RECT  962.2 1099.6 962.6 1100 ;
    END
  END recovery_i.ghist[13]
  PIN recovery_i.ghist[14]
    DIRECTION INPUT ;
    USE SIGNAL ;
    PORT
      LAYER Metal2 ;
        RECT  966.04 1099.6 966.44 1100 ;
    END
  END recovery_i.ghist[14]
  PIN recovery_i.ghist[15]
    DIRECTION INPUT ;
    USE SIGNAL ;
    PORT
      LAYER Metal2 ;
        RECT  969.88 1099.6 970.28 1100 ;
    END
  END recovery_i.ghist[15]
  PIN recovery_i.ghist[1]
    DIRECTION INPUT ;
    USE SIGNAL ;
    PORT
      LAYER Metal2 ;
        RECT  912.28 1099.6 912.68 1100 ;
    END
  END recovery_i.ghist[1]
  PIN recovery_i.ghist[2]
    DIRECTION INPUT ;
    USE SIGNAL ;
    PORT
      LAYER Metal2 ;
        RECT  918.04 1099.6 918.44 1100 ;
    END
  END recovery_i.ghist[2]
  PIN recovery_i.ghist[3]
    DIRECTION INPUT ;
    USE SIGNAL ;
    PORT
      LAYER Metal2 ;
        RECT  923.8 1099.6 924.2 1100 ;
    END
  END recovery_i.ghist[3]
  PIN recovery_i.ghist[4]
    DIRECTION INPUT ;
    USE SIGNAL ;
    PORT
      LAYER Metal2 ;
        RECT  927.64 1099.6 928.04 1100 ;
    END
  END recovery_i.ghist[4]
  PIN recovery_i.ghist[5]
    DIRECTION INPUT ;
    USE SIGNAL ;
    PORT
      LAYER Metal2 ;
        RECT  931.48 1099.6 931.88 1100 ;
    END
  END recovery_i.ghist[5]
  PIN recovery_i.ghist[6]
    DIRECTION INPUT ;
    USE SIGNAL ;
    PORT
      LAYER Metal2 ;
        RECT  935.32 1099.6 935.72 1100 ;
    END
  END recovery_i.ghist[6]
  PIN recovery_i.ghist[7]
    DIRECTION INPUT ;
    USE SIGNAL ;
    PORT
      LAYER Metal2 ;
        RECT  939.16 1099.6 939.56 1100 ;
    END
  END recovery_i.ghist[7]
  PIN recovery_i.ghist[8]
    DIRECTION INPUT ;
    USE SIGNAL ;
    PORT
      LAYER Metal2 ;
        RECT  943 1099.6 943.4 1100 ;
    END
  END recovery_i.ghist[8]
  PIN recovery_i.ghist[9]
    DIRECTION INPUT ;
    USE SIGNAL ;
    PORT
      LAYER Metal2 ;
        RECT  946.84 1099.6 947.24 1100 ;
    END
  END recovery_i.ghist[9]
  PIN recovery_i.new_pc[0]
    DIRECTION INPUT ;
    USE SIGNAL ;
    PORT
      LAYER Metal2 ;
        RECT  908.44 1099.6 908.84 1100 ;
    END
  END recovery_i.new_pc[0]
  PIN recovery_i.new_pc[10]
    DIRECTION INPUT ;
    USE SIGNAL ;
    PORT
      LAYER Metal2 ;
        RECT  952.6 1099.6 953 1100 ;
    END
  END recovery_i.new_pc[10]
  PIN recovery_i.new_pc[11]
    DIRECTION INPUT ;
    USE SIGNAL ;
    PORT
      LAYER Metal2 ;
        RECT  956.44 1099.6 956.84 1100 ;
    END
  END recovery_i.new_pc[11]
  PIN recovery_i.new_pc[12]
    DIRECTION INPUT ;
    USE SIGNAL ;
    PORT
      LAYER Metal2 ;
        RECT  960.28 1099.6 960.68 1100 ;
    END
  END recovery_i.new_pc[12]
  PIN recovery_i.new_pc[13]
    DIRECTION INPUT ;
    USE SIGNAL ;
    PORT
      LAYER Metal2 ;
        RECT  964.12 1099.6 964.52 1100 ;
    END
  END recovery_i.new_pc[13]
  PIN recovery_i.new_pc[14]
    DIRECTION INPUT ;
    USE SIGNAL ;
    PORT
      LAYER Metal2 ;
        RECT  967.96 1099.6 968.36 1100 ;
    END
  END recovery_i.new_pc[14]
  PIN recovery_i.new_pc[15]
    DIRECTION INPUT ;
    USE SIGNAL ;
    PORT
      LAYER Metal2 ;
        RECT  971.8 1099.6 972.2 1100 ;
    END
  END recovery_i.new_pc[15]
  PIN recovery_i.new_pc[16]
    DIRECTION INPUT ;
    USE SIGNAL ;
    PORT
      LAYER Metal2 ;
        RECT  973.72 1099.6 974.12 1100 ;
    END
  END recovery_i.new_pc[16]
  PIN recovery_i.new_pc[17]
    DIRECTION INPUT ;
    USE SIGNAL ;
    PORT
      LAYER Metal2 ;
        RECT  975.64 1099.6 976.04 1100 ;
    END
  END recovery_i.new_pc[17]
  PIN recovery_i.new_pc[18]
    DIRECTION INPUT ;
    USE SIGNAL ;
    PORT
      LAYER Metal2 ;
        RECT  977.56 1099.6 977.96 1100 ;
    END
  END recovery_i.new_pc[18]
  PIN recovery_i.new_pc[19]
    DIRECTION INPUT ;
    USE SIGNAL ;
    PORT
      LAYER Metal2 ;
        RECT  979.48 1099.6 979.88 1100 ;
    END
  END recovery_i.new_pc[19]
  PIN recovery_i.new_pc[1]
    DIRECTION INPUT ;
    USE SIGNAL ;
    PORT
      LAYER Metal2 ;
        RECT  914.2 1099.6 914.6 1100 ;
    END
  END recovery_i.new_pc[1]
  PIN recovery_i.new_pc[20]
    DIRECTION INPUT ;
    USE SIGNAL ;
    PORT
      LAYER Metal2 ;
        RECT  981.4 1099.6 981.8 1100 ;
    END
  END recovery_i.new_pc[20]
  PIN recovery_i.new_pc[21]
    DIRECTION INPUT ;
    USE SIGNAL ;
    PORT
      LAYER Metal2 ;
        RECT  983.32 1099.6 983.72 1100 ;
    END
  END recovery_i.new_pc[21]
  PIN recovery_i.new_pc[22]
    DIRECTION INPUT ;
    USE SIGNAL ;
    PORT
      LAYER Metal2 ;
        RECT  985.24 1099.6 985.64 1100 ;
    END
  END recovery_i.new_pc[22]
  PIN recovery_i.new_pc[23]
    DIRECTION INPUT ;
    USE SIGNAL ;
    PORT
      LAYER Metal2 ;
        RECT  987.16 1099.6 987.56 1100 ;
    END
  END recovery_i.new_pc[23]
  PIN recovery_i.new_pc[24]
    DIRECTION INPUT ;
    USE SIGNAL ;
    PORT
      LAYER Metal2 ;
        RECT  989.08 1099.6 989.48 1100 ;
    END
  END recovery_i.new_pc[24]
  PIN recovery_i.new_pc[25]
    DIRECTION INPUT ;
    USE SIGNAL ;
    PORT
      LAYER Metal2 ;
        RECT  991 1099.6 991.4 1100 ;
    END
  END recovery_i.new_pc[25]
  PIN recovery_i.new_pc[26]
    DIRECTION INPUT ;
    USE SIGNAL ;
    PORT
      LAYER Metal2 ;
        RECT  992.92 1099.6 993.32 1100 ;
    END
  END recovery_i.new_pc[26]
  PIN recovery_i.new_pc[27]
    DIRECTION INPUT ;
    USE SIGNAL ;
    PORT
      LAYER Metal2 ;
        RECT  994.84 1099.6 995.24 1100 ;
    END
  END recovery_i.new_pc[27]
  PIN recovery_i.new_pc[28]
    DIRECTION INPUT ;
    USE SIGNAL ;
    PORT
      LAYER Metal2 ;
        RECT  996.76 1099.6 997.16 1100 ;
    END
  END recovery_i.new_pc[28]
  PIN recovery_i.new_pc[29]
    DIRECTION INPUT ;
    USE SIGNAL ;
    PORT
      LAYER Metal2 ;
        RECT  998.68 1099.6 999.08 1100 ;
    END
  END recovery_i.new_pc[29]
  PIN recovery_i.new_pc[2]
    DIRECTION INPUT ;
    USE SIGNAL ;
    PORT
      LAYER Metal2 ;
        RECT  919.96 1099.6 920.36 1100 ;
    END
  END recovery_i.new_pc[2]
  PIN recovery_i.new_pc[30]
    DIRECTION INPUT ;
    USE SIGNAL ;
    PORT
      LAYER Metal2 ;
        RECT  1000.6 1099.6 1001 1100 ;
    END
  END recovery_i.new_pc[30]
  PIN recovery_i.new_pc[31]
    DIRECTION INPUT ;
    USE SIGNAL ;
    PORT
      LAYER Metal2 ;
        RECT  1002.52 1099.6 1002.92 1100 ;
    END
  END recovery_i.new_pc[31]
  PIN recovery_i.new_pc[3]
    DIRECTION INPUT ;
    USE SIGNAL ;
    PORT
      LAYER Metal2 ;
        RECT  925.72 1099.6 926.12 1100 ;
    END
  END recovery_i.new_pc[3]
  PIN recovery_i.new_pc[4]
    DIRECTION INPUT ;
    USE SIGNAL ;
    PORT
      LAYER Metal2 ;
        RECT  929.56 1099.6 929.96 1100 ;
    END
  END recovery_i.new_pc[4]
  PIN recovery_i.new_pc[5]
    DIRECTION INPUT ;
    USE SIGNAL ;
    PORT
      LAYER Metal2 ;
        RECT  933.4 1099.6 933.8 1100 ;
    END
  END recovery_i.new_pc[5]
  PIN recovery_i.new_pc[6]
    DIRECTION INPUT ;
    USE SIGNAL ;
    PORT
      LAYER Metal2 ;
        RECT  937.24 1099.6 937.64 1100 ;
    END
  END recovery_i.new_pc[6]
  PIN recovery_i.new_pc[7]
    DIRECTION INPUT ;
    USE SIGNAL ;
    PORT
      LAYER Metal2 ;
        RECT  941.08 1099.6 941.48 1100 ;
    END
  END recovery_i.new_pc[7]
  PIN recovery_i.new_pc[8]
    DIRECTION INPUT ;
    USE SIGNAL ;
    PORT
      LAYER Metal2 ;
        RECT  944.92 1099.6 945.32 1100 ;
    END
  END recovery_i.new_pc[8]
  PIN recovery_i.new_pc[9]
    DIRECTION INPUT ;
    USE SIGNAL ;
    PORT
      LAYER Metal2 ;
        RECT  948.76 1099.6 949.16 1100 ;
    END
  END recovery_i.new_pc[9]
  PIN recovery_i.ras_ptr[0]
    DIRECTION INPUT ;
    USE SIGNAL ;
    PORT
      LAYER Metal2 ;
        RECT  910.36 1099.6 910.76 1100 ;
    END
  END recovery_i.ras_ptr[0]
  PIN recovery_i.ras_ptr[1]
    DIRECTION INPUT ;
    USE SIGNAL ;
    PORT
      LAYER Metal2 ;
        RECT  916.12 1099.6 916.52 1100 ;
    END
  END recovery_i.ras_ptr[1]
  PIN recovery_i.ras_ptr[2]
    DIRECTION INPUT ;
    USE SIGNAL ;
    PORT
      LAYER Metal2 ;
        RECT  921.88 1099.6 922.28 1100 ;
    END
  END recovery_i.ras_ptr[2]
  PIN recovery_i.valid
    DIRECTION INPUT ;
    USE SIGNAL ;
    PORT
      LAYER Metal2 ;
        RECT  904.6 1099.6 905 1100 ;
    END
  END recovery_i.valid
  PIN reset_i
    DIRECTION INPUT ;
    USE SIGNAL ;
    PORT
      LAYER Metal2 ;
        RECT  100.12 1099.6 100.52 1100 ;
    END
  END reset_i
  PIN retire_i.conditional
    DIRECTION INPUT ;
    USE SIGNAL ;
    PORT
      LAYER Metal2 ;
        RECT  1004.44 1099.6 1004.84 1100 ;
    END
  END retire_i.conditional
  PIN retire_i.ghist_low[0]
    DIRECTION INPUT ;
    USE SIGNAL ;
    PORT
      LAYER Metal2 ;
        RECT  1012.12 1099.6 1012.52 1100 ;
    END
  END retire_i.ghist_low[0]
  PIN retire_i.ghist_low[1]
    DIRECTION INPUT ;
    USE SIGNAL ;
    PORT
      LAYER Metal2 ;
        RECT  1015.96 1099.6 1016.36 1100 ;
    END
  END retire_i.ghist_low[1]
  PIN retire_i.ghist_low[2]
    DIRECTION INPUT ;
    USE SIGNAL ;
    PORT
      LAYER Metal2 ;
        RECT  1019.8 1099.6 1020.2 1100 ;
    END
  END retire_i.ghist_low[2]
  PIN retire_i.ghist_low[3]
    DIRECTION INPUT ;
    USE SIGNAL ;
    PORT
      LAYER Metal2 ;
        RECT  1023.64 1099.6 1024.04 1100 ;
    END
  END retire_i.ghist_low[3]
  PIN retire_i.ghist_low[4]
    DIRECTION INPUT ;
    USE SIGNAL ;
    PORT
      LAYER Metal2 ;
        RECT  1027.48 1099.6 1027.88 1100 ;
    END
  END retire_i.ghist_low[4]
  PIN retire_i.ghist_low[5]
    DIRECTION INPUT ;
    USE SIGNAL ;
    PORT
      LAYER Metal2 ;
        RECT  1031.32 1099.6 1031.72 1100 ;
    END
  END retire_i.ghist_low[5]
  PIN retire_i.ghist_low[6]
    DIRECTION INPUT ;
    USE SIGNAL ;
    PORT
      LAYER Metal2 ;
        RECT  1035.16 1099.6 1035.56 1100 ;
    END
  END retire_i.ghist_low[6]
  PIN retire_i.ghist_low[7]
    DIRECTION INPUT ;
    USE SIGNAL ;
    PORT
      LAYER Metal2 ;
        RECT  1039 1099.6 1039.4 1100 ;
    END
  END retire_i.ghist_low[7]
  PIN retire_i.ghist_low[8]
    DIRECTION INPUT ;
    USE SIGNAL ;
    PORT
      LAYER Metal2 ;
        RECT  1042.84 1099.6 1043.24 1100 ;
    END
  END retire_i.ghist_low[8]
  PIN retire_i.is_control
    DIRECTION INPUT ;
    USE SIGNAL ;
    PORT
      LAYER Metal2 ;
        RECT  1006.36 1099.6 1006.76 1100 ;
    END
  END retire_i.is_control
  PIN retire_i.pc_low[0]
    DIRECTION INPUT ;
    USE SIGNAL ;
    PORT
      LAYER Metal2 ;
        RECT  1014.04 1099.6 1014.44 1100 ;
    END
  END retire_i.pc_low[0]
  PIN retire_i.pc_low[1]
    DIRECTION INPUT ;
    USE SIGNAL ;
    PORT
      LAYER Metal2 ;
        RECT  1017.88 1099.6 1018.28 1100 ;
    END
  END retire_i.pc_low[1]
  PIN retire_i.pc_low[2]
    DIRECTION INPUT ;
    USE SIGNAL ;
    PORT
      LAYER Metal2 ;
        RECT  1021.72 1099.6 1022.12 1100 ;
    END
  END retire_i.pc_low[2]
  PIN retire_i.pc_low[3]
    DIRECTION INPUT ;
    USE SIGNAL ;
    PORT
      LAYER Metal2 ;
        RECT  1025.56 1099.6 1025.96 1100 ;
    END
  END retire_i.pc_low[3]
  PIN retire_i.pc_low[4]
    DIRECTION INPUT ;
    USE SIGNAL ;
    PORT
      LAYER Metal2 ;
        RECT  1029.4 1099.6 1029.8 1100 ;
    END
  END retire_i.pc_low[4]
  PIN retire_i.pc_low[5]
    DIRECTION INPUT ;
    USE SIGNAL ;
    PORT
      LAYER Metal2 ;
        RECT  1033.24 1099.6 1033.64 1100 ;
    END
  END retire_i.pc_low[5]
  PIN retire_i.pc_low[6]
    DIRECTION INPUT ;
    USE SIGNAL ;
    PORT
      LAYER Metal2 ;
        RECT  1037.08 1099.6 1037.48 1100 ;
    END
  END retire_i.pc_low[6]
  PIN retire_i.pc_low[7]
    DIRECTION INPUT ;
    USE SIGNAL ;
    PORT
      LAYER Metal2 ;
        RECT  1040.92 1099.6 1041.32 1100 ;
    END
  END retire_i.pc_low[7]
  PIN retire_i.pc_low[8]
    DIRECTION INPUT ;
    USE SIGNAL ;
    PORT
      LAYER Metal2 ;
        RECT  1044.76 1099.6 1045.16 1100 ;
    END
  END retire_i.pc_low[8]
  PIN retire_i.taken
    DIRECTION INPUT ;
    USE SIGNAL ;
    PORT
      LAYER Metal2 ;
        RECT  1008.28 1099.6 1008.68 1100 ;
    END
  END retire_i.taken
  PIN retire_i.valid
    DIRECTION INPUT ;
    USE SIGNAL ;
    PORT
      LAYER Metal2 ;
        RECT  1010.2 1099.6 1010.6 1100 ;
    END
  END retire_i.valid
  PIN stop_o
    DIRECTION OUTPUT ;
    USE SIGNAL ;
    PORT
      LAYER Metal3 ;
        RECT  0 893.14 0.4 893.54 ;
    END
  END stop_o
  PIN window_count_i[0]
    DIRECTION INPUT ;
    USE SIGNAL ;
    PORT
      LAYER Metal3 ;
        RECT  0 624.34 0.4 624.74 ;
    END
  END window_count_i[0]
  PIN window_count_i[1]
    DIRECTION INPUT ;
    USE SIGNAL ;
    PORT
      LAYER Metal3 ;
        RECT  0 622.66 0.4 623.06 ;
    END
  END window_count_i[1]
  PIN window_count_i[2]
    DIRECTION INPUT ;
    USE SIGNAL ;
    PORT
      LAYER Metal3 ;
        RECT  0 620.98 0.4 621.38 ;
    END
  END window_count_i[2]
  PIN window_count_i[3]
    DIRECTION INPUT ;
    USE SIGNAL ;
    PORT
      LAYER Metal3 ;
        RECT  0 619.3 0.4 619.7 ;
    END
  END window_count_i[3]
  PIN window_count_i[4]
    DIRECTION INPUT ;
    USE SIGNAL ;
    PORT
      LAYER Metal3 ;
        RECT  0 617.62 0.4 618.02 ;
    END
  END window_count_i[4]
  PIN window_count_i[5]
    DIRECTION INPUT ;
    USE SIGNAL ;
    PORT
      LAYER Metal3 ;
        RECT  0 615.94 0.4 616.34 ;
    END
  END window_count_i[5]
  PIN window_fault_i[0]
    DIRECTION INPUT ;
    USE SIGNAL ;
    PORT
      LAYER Metal3 ;
        RECT  0 563.86 0.4 564.26 ;
    END
  END window_fault_i[0]
  PIN window_fault_i[10]
    DIRECTION INPUT ;
    USE SIGNAL ;
    PORT
      LAYER Metal3 ;
        RECT  0 547.06 0.4 547.46 ;
    END
  END window_fault_i[10]
  PIN window_fault_i[11]
    DIRECTION INPUT ;
    USE SIGNAL ;
    PORT
      LAYER Metal3 ;
        RECT  0 545.38 0.4 545.78 ;
    END
  END window_fault_i[11]
  PIN window_fault_i[12]
    DIRECTION INPUT ;
    USE SIGNAL ;
    PORT
      LAYER Metal3 ;
        RECT  0 543.7 0.4 544.1 ;
    END
  END window_fault_i[12]
  PIN window_fault_i[13]
    DIRECTION INPUT ;
    USE SIGNAL ;
    PORT
      LAYER Metal3 ;
        RECT  0 542.02 0.4 542.42 ;
    END
  END window_fault_i[13]
  PIN window_fault_i[14]
    DIRECTION INPUT ;
    USE SIGNAL ;
    PORT
      LAYER Metal3 ;
        RECT  0 540.34 0.4 540.74 ;
    END
  END window_fault_i[14]
  PIN window_fault_i[15]
    DIRECTION INPUT ;
    USE SIGNAL ;
    PORT
      LAYER Metal3 ;
        RECT  0 538.66 0.4 539.06 ;
    END
  END window_fault_i[15]
  PIN window_fault_i[16]
    DIRECTION INPUT ;
    USE SIGNAL ;
    PORT
      LAYER Metal3 ;
        RECT  0 536.98 0.4 537.38 ;
    END
  END window_fault_i[16]
  PIN window_fault_i[17]
    DIRECTION INPUT ;
    USE SIGNAL ;
    PORT
      LAYER Metal3 ;
        RECT  0 535.3 0.4 535.7 ;
    END
  END window_fault_i[17]
  PIN window_fault_i[18]
    DIRECTION INPUT ;
    USE SIGNAL ;
    PORT
      LAYER Metal3 ;
        RECT  0 533.62 0.4 534.02 ;
    END
  END window_fault_i[18]
  PIN window_fault_i[19]
    DIRECTION INPUT ;
    USE SIGNAL ;
    PORT
      LAYER Metal3 ;
        RECT  0 531.94 0.4 532.34 ;
    END
  END window_fault_i[19]
  PIN window_fault_i[1]
    DIRECTION INPUT ;
    USE SIGNAL ;
    PORT
      LAYER Metal3 ;
        RECT  0 562.18 0.4 562.58 ;
    END
  END window_fault_i[1]
  PIN window_fault_i[20]
    DIRECTION INPUT ;
    USE SIGNAL ;
    PORT
      LAYER Metal3 ;
        RECT  0 530.26 0.4 530.66 ;
    END
  END window_fault_i[20]
  PIN window_fault_i[21]
    DIRECTION INPUT ;
    USE SIGNAL ;
    PORT
      LAYER Metal3 ;
        RECT  0 528.58 0.4 528.98 ;
    END
  END window_fault_i[21]
  PIN window_fault_i[22]
    DIRECTION INPUT ;
    USE SIGNAL ;
    PORT
      LAYER Metal3 ;
        RECT  0 526.9 0.4 527.3 ;
    END
  END window_fault_i[22]
  PIN window_fault_i[23]
    DIRECTION INPUT ;
    USE SIGNAL ;
    PORT
      LAYER Metal3 ;
        RECT  0 525.22 0.4 525.62 ;
    END
  END window_fault_i[23]
  PIN window_fault_i[24]
    DIRECTION INPUT ;
    USE SIGNAL ;
    PORT
      LAYER Metal3 ;
        RECT  0 523.54 0.4 523.94 ;
    END
  END window_fault_i[24]
  PIN window_fault_i[25]
    DIRECTION INPUT ;
    USE SIGNAL ;
    PORT
      LAYER Metal3 ;
        RECT  0 521.86 0.4 522.26 ;
    END
  END window_fault_i[25]
  PIN window_fault_i[26]
    DIRECTION INPUT ;
    USE SIGNAL ;
    PORT
      LAYER Metal3 ;
        RECT  0 520.18 0.4 520.58 ;
    END
  END window_fault_i[26]
  PIN window_fault_i[27]
    DIRECTION INPUT ;
    USE SIGNAL ;
    PORT
      LAYER Metal3 ;
        RECT  0 518.5 0.4 518.9 ;
    END
  END window_fault_i[27]
  PIN window_fault_i[28]
    DIRECTION INPUT ;
    USE SIGNAL ;
    PORT
      LAYER Metal3 ;
        RECT  0 516.82 0.4 517.22 ;
    END
  END window_fault_i[28]
  PIN window_fault_i[29]
    DIRECTION INPUT ;
    USE SIGNAL ;
    PORT
      LAYER Metal3 ;
        RECT  0 515.14 0.4 515.54 ;
    END
  END window_fault_i[29]
  PIN window_fault_i[2]
    DIRECTION INPUT ;
    USE SIGNAL ;
    PORT
      LAYER Metal3 ;
        RECT  0 560.5 0.4 560.9 ;
    END
  END window_fault_i[2]
  PIN window_fault_i[30]
    DIRECTION INPUT ;
    USE SIGNAL ;
    PORT
      LAYER Metal3 ;
        RECT  0 513.46 0.4 513.86 ;
    END
  END window_fault_i[30]
  PIN window_fault_i[31]
    DIRECTION INPUT ;
    USE SIGNAL ;
    PORT
      LAYER Metal3 ;
        RECT  0 511.78 0.4 512.18 ;
    END
  END window_fault_i[31]
  PIN window_fault_i[3]
    DIRECTION INPUT ;
    USE SIGNAL ;
    PORT
      LAYER Metal3 ;
        RECT  0 558.82 0.4 559.22 ;
    END
  END window_fault_i[3]
  PIN window_fault_i[4]
    DIRECTION INPUT ;
    USE SIGNAL ;
    PORT
      LAYER Metal3 ;
        RECT  0 557.14 0.4 557.54 ;
    END
  END window_fault_i[4]
  PIN window_fault_i[5]
    DIRECTION INPUT ;
    USE SIGNAL ;
    PORT
      LAYER Metal3 ;
        RECT  0 555.46 0.4 555.86 ;
    END
  END window_fault_i[5]
  PIN window_fault_i[6]
    DIRECTION INPUT ;
    USE SIGNAL ;
    PORT
      LAYER Metal3 ;
        RECT  0 553.78 0.4 554.18 ;
    END
  END window_fault_i[6]
  PIN window_fault_i[7]
    DIRECTION INPUT ;
    USE SIGNAL ;
    PORT
      LAYER Metal3 ;
        RECT  0 552.1 0.4 552.5 ;
    END
  END window_fault_i[7]
  PIN window_fault_i[8]
    DIRECTION INPUT ;
    USE SIGNAL ;
    PORT
      LAYER Metal3 ;
        RECT  0 550.42 0.4 550.82 ;
    END
  END window_fault_i[8]
  PIN window_fault_i[9]
    DIRECTION INPUT ;
    USE SIGNAL ;
    PORT
      LAYER Metal3 ;
        RECT  0 548.74 0.4 549.14 ;
    END
  END window_fault_i[9]
  PIN window_i[0]
    DIRECTION INPUT ;
    USE SIGNAL ;
    PORT
      LAYER Metal3 ;
        RECT  0 459.7 0.4 460.1 ;
    END
  END window_i[0]
  PIN window_i[100]
    DIRECTION INPUT ;
    USE SIGNAL ;
    PORT
      LAYER Metal3 ;
        RECT  0 291.7 0.4 292.1 ;
    END
  END window_i[100]
  PIN window_i[101]
    DIRECTION INPUT ;
    USE SIGNAL ;
    PORT
      LAYER Metal3 ;
        RECT  0 290.02 0.4 290.42 ;
    END
  END window_i[101]
  PIN window_i[102]
    DIRECTION INPUT ;
    USE SIGNAL ;
    PORT
      LAYER Metal3 ;
        RECT  0 288.34 0.4 288.74 ;
    END
  END window_i[102]
  PIN window_i[103]
    DIRECTION INPUT ;
    USE SIGNAL ;
    PORT
      LAYER Metal3 ;
        RECT  0 286.66 0.4 287.06 ;
    END
  END window_i[103]
  PIN window_i[104]
    DIRECTION INPUT ;
    USE SIGNAL ;
    PORT
      LAYER Metal3 ;
        RECT  0 284.98 0.4 285.38 ;
    END
  END window_i[104]
  PIN window_i[105]
    DIRECTION INPUT ;
    USE SIGNAL ;
    PORT
      LAYER Metal3 ;
        RECT  0 283.3 0.4 283.7 ;
    END
  END window_i[105]
  PIN window_i[106]
    DIRECTION INPUT ;
    USE SIGNAL ;
    PORT
      LAYER Metal3 ;
        RECT  0 281.62 0.4 282.02 ;
    END
  END window_i[106]
  PIN window_i[107]
    DIRECTION INPUT ;
    USE SIGNAL ;
    PORT
      LAYER Metal3 ;
        RECT  0 279.94 0.4 280.34 ;
    END
  END window_i[107]
  PIN window_i[108]
    DIRECTION INPUT ;
    USE SIGNAL ;
    PORT
      LAYER Metal3 ;
        RECT  0 278.26 0.4 278.66 ;
    END
  END window_i[108]
  PIN window_i[109]
    DIRECTION INPUT ;
    USE SIGNAL ;
    PORT
      LAYER Metal3 ;
        RECT  0 276.58 0.4 276.98 ;
    END
  END window_i[109]
  PIN window_i[10]
    DIRECTION INPUT ;
    USE SIGNAL ;
    PORT
      LAYER Metal3 ;
        RECT  0 442.9 0.4 443.3 ;
    END
  END window_i[10]
  PIN window_i[110]
    DIRECTION INPUT ;
    USE SIGNAL ;
    PORT
      LAYER Metal3 ;
        RECT  0 274.9 0.4 275.3 ;
    END
  END window_i[110]
  PIN window_i[111]
    DIRECTION INPUT ;
    USE SIGNAL ;
    PORT
      LAYER Metal3 ;
        RECT  0 273.22 0.4 273.62 ;
    END
  END window_i[111]
  PIN window_i[112]
    DIRECTION INPUT ;
    USE SIGNAL ;
    PORT
      LAYER Metal3 ;
        RECT  0 271.54 0.4 271.94 ;
    END
  END window_i[112]
  PIN window_i[113]
    DIRECTION INPUT ;
    USE SIGNAL ;
    PORT
      LAYER Metal3 ;
        RECT  0 269.86 0.4 270.26 ;
    END
  END window_i[113]
  PIN window_i[114]
    DIRECTION INPUT ;
    USE SIGNAL ;
    PORT
      LAYER Metal3 ;
        RECT  0 268.18 0.4 268.58 ;
    END
  END window_i[114]
  PIN window_i[115]
    DIRECTION INPUT ;
    USE SIGNAL ;
    PORT
      LAYER Metal3 ;
        RECT  0 266.5 0.4 266.9 ;
    END
  END window_i[115]
  PIN window_i[116]
    DIRECTION INPUT ;
    USE SIGNAL ;
    PORT
      LAYER Metal3 ;
        RECT  0 264.82 0.4 265.22 ;
    END
  END window_i[116]
  PIN window_i[117]
    DIRECTION INPUT ;
    USE SIGNAL ;
    PORT
      LAYER Metal3 ;
        RECT  0 263.14 0.4 263.54 ;
    END
  END window_i[117]
  PIN window_i[118]
    DIRECTION INPUT ;
    USE SIGNAL ;
    PORT
      LAYER Metal3 ;
        RECT  0 261.46 0.4 261.86 ;
    END
  END window_i[118]
  PIN window_i[119]
    DIRECTION INPUT ;
    USE SIGNAL ;
    PORT
      LAYER Metal3 ;
        RECT  0 259.78 0.4 260.18 ;
    END
  END window_i[119]
  PIN window_i[11]
    DIRECTION INPUT ;
    USE SIGNAL ;
    PORT
      LAYER Metal3 ;
        RECT  0 441.22 0.4 441.62 ;
    END
  END window_i[11]
  PIN window_i[120]
    DIRECTION INPUT ;
    USE SIGNAL ;
    PORT
      LAYER Metal3 ;
        RECT  0 258.1 0.4 258.5 ;
    END
  END window_i[120]
  PIN window_i[121]
    DIRECTION INPUT ;
    USE SIGNAL ;
    PORT
      LAYER Metal3 ;
        RECT  0 256.42 0.4 256.82 ;
    END
  END window_i[121]
  PIN window_i[122]
    DIRECTION INPUT ;
    USE SIGNAL ;
    PORT
      LAYER Metal3 ;
        RECT  0 254.74 0.4 255.14 ;
    END
  END window_i[122]
  PIN window_i[123]
    DIRECTION INPUT ;
    USE SIGNAL ;
    PORT
      LAYER Metal3 ;
        RECT  0 253.06 0.4 253.46 ;
    END
  END window_i[123]
  PIN window_i[124]
    DIRECTION INPUT ;
    USE SIGNAL ;
    PORT
      LAYER Metal3 ;
        RECT  0 251.38 0.4 251.78 ;
    END
  END window_i[124]
  PIN window_i[125]
    DIRECTION INPUT ;
    USE SIGNAL ;
    PORT
      LAYER Metal3 ;
        RECT  0 249.7 0.4 250.1 ;
    END
  END window_i[125]
  PIN window_i[126]
    DIRECTION INPUT ;
    USE SIGNAL ;
    PORT
      LAYER Metal3 ;
        RECT  0 248.02 0.4 248.42 ;
    END
  END window_i[126]
  PIN window_i[127]
    DIRECTION INPUT ;
    USE SIGNAL ;
    PORT
      LAYER Metal3 ;
        RECT  0 246.34 0.4 246.74 ;
    END
  END window_i[127]
  PIN window_i[128]
    DIRECTION INPUT ;
    USE SIGNAL ;
    PORT
      LAYER Metal3 ;
        RECT  0 244.66 0.4 245.06 ;
    END
  END window_i[128]
  PIN window_i[129]
    DIRECTION INPUT ;
    USE SIGNAL ;
    PORT
      LAYER Metal3 ;
        RECT  0 242.98 0.4 243.38 ;
    END
  END window_i[129]
  PIN window_i[12]
    DIRECTION INPUT ;
    USE SIGNAL ;
    PORT
      LAYER Metal3 ;
        RECT  0 439.54 0.4 439.94 ;
    END
  END window_i[12]
  PIN window_i[130]
    DIRECTION INPUT ;
    USE SIGNAL ;
    PORT
      LAYER Metal3 ;
        RECT  0 241.3 0.4 241.7 ;
    END
  END window_i[130]
  PIN window_i[131]
    DIRECTION INPUT ;
    USE SIGNAL ;
    PORT
      LAYER Metal3 ;
        RECT  0 239.62 0.4 240.02 ;
    END
  END window_i[131]
  PIN window_i[132]
    DIRECTION INPUT ;
    USE SIGNAL ;
    PORT
      LAYER Metal3 ;
        RECT  0 237.94 0.4 238.34 ;
    END
  END window_i[132]
  PIN window_i[133]
    DIRECTION INPUT ;
    USE SIGNAL ;
    PORT
      LAYER Metal3 ;
        RECT  0 236.26 0.4 236.66 ;
    END
  END window_i[133]
  PIN window_i[134]
    DIRECTION INPUT ;
    USE SIGNAL ;
    PORT
      LAYER Metal3 ;
        RECT  0 234.58 0.4 234.98 ;
    END
  END window_i[134]
  PIN window_i[135]
    DIRECTION INPUT ;
    USE SIGNAL ;
    PORT
      LAYER Metal3 ;
        RECT  0 232.9 0.4 233.3 ;
    END
  END window_i[135]
  PIN window_i[136]
    DIRECTION INPUT ;
    USE SIGNAL ;
    PORT
      LAYER Metal3 ;
        RECT  0 231.22 0.4 231.62 ;
    END
  END window_i[136]
  PIN window_i[137]
    DIRECTION INPUT ;
    USE SIGNAL ;
    PORT
      LAYER Metal3 ;
        RECT  0 229.54 0.4 229.94 ;
    END
  END window_i[137]
  PIN window_i[138]
    DIRECTION INPUT ;
    USE SIGNAL ;
    PORT
      LAYER Metal3 ;
        RECT  0 227.86 0.4 228.26 ;
    END
  END window_i[138]
  PIN window_i[139]
    DIRECTION INPUT ;
    USE SIGNAL ;
    PORT
      LAYER Metal3 ;
        RECT  0 226.18 0.4 226.58 ;
    END
  END window_i[139]
  PIN window_i[13]
    DIRECTION INPUT ;
    USE SIGNAL ;
    PORT
      LAYER Metal3 ;
        RECT  0 437.86 0.4 438.26 ;
    END
  END window_i[13]
  PIN window_i[140]
    DIRECTION INPUT ;
    USE SIGNAL ;
    PORT
      LAYER Metal3 ;
        RECT  0 224.5 0.4 224.9 ;
    END
  END window_i[140]
  PIN window_i[141]
    DIRECTION INPUT ;
    USE SIGNAL ;
    PORT
      LAYER Metal3 ;
        RECT  0 222.82 0.4 223.22 ;
    END
  END window_i[141]
  PIN window_i[142]
    DIRECTION INPUT ;
    USE SIGNAL ;
    PORT
      LAYER Metal3 ;
        RECT  0 221.14 0.4 221.54 ;
    END
  END window_i[142]
  PIN window_i[143]
    DIRECTION INPUT ;
    USE SIGNAL ;
    PORT
      LAYER Metal3 ;
        RECT  0 219.46 0.4 219.86 ;
    END
  END window_i[143]
  PIN window_i[144]
    DIRECTION INPUT ;
    USE SIGNAL ;
    PORT
      LAYER Metal3 ;
        RECT  0 217.78 0.4 218.18 ;
    END
  END window_i[144]
  PIN window_i[145]
    DIRECTION INPUT ;
    USE SIGNAL ;
    PORT
      LAYER Metal3 ;
        RECT  0 216.1 0.4 216.5 ;
    END
  END window_i[145]
  PIN window_i[146]
    DIRECTION INPUT ;
    USE SIGNAL ;
    PORT
      LAYER Metal3 ;
        RECT  0 214.42 0.4 214.82 ;
    END
  END window_i[146]
  PIN window_i[147]
    DIRECTION INPUT ;
    USE SIGNAL ;
    PORT
      LAYER Metal3 ;
        RECT  0 212.74 0.4 213.14 ;
    END
  END window_i[147]
  PIN window_i[148]
    DIRECTION INPUT ;
    USE SIGNAL ;
    PORT
      LAYER Metal3 ;
        RECT  0 211.06 0.4 211.46 ;
    END
  END window_i[148]
  PIN window_i[149]
    DIRECTION INPUT ;
    USE SIGNAL ;
    PORT
      LAYER Metal3 ;
        RECT  0 209.38 0.4 209.78 ;
    END
  END window_i[149]
  PIN window_i[14]
    DIRECTION INPUT ;
    USE SIGNAL ;
    PORT
      LAYER Metal3 ;
        RECT  0 436.18 0.4 436.58 ;
    END
  END window_i[14]
  PIN window_i[150]
    DIRECTION INPUT ;
    USE SIGNAL ;
    PORT
      LAYER Metal3 ;
        RECT  0 207.7 0.4 208.1 ;
    END
  END window_i[150]
  PIN window_i[151]
    DIRECTION INPUT ;
    USE SIGNAL ;
    PORT
      LAYER Metal3 ;
        RECT  0 206.02 0.4 206.42 ;
    END
  END window_i[151]
  PIN window_i[152]
    DIRECTION INPUT ;
    USE SIGNAL ;
    PORT
      LAYER Metal3 ;
        RECT  0 204.34 0.4 204.74 ;
    END
  END window_i[152]
  PIN window_i[153]
    DIRECTION INPUT ;
    USE SIGNAL ;
    PORT
      LAYER Metal3 ;
        RECT  0 202.66 0.4 203.06 ;
    END
  END window_i[153]
  PIN window_i[154]
    DIRECTION INPUT ;
    USE SIGNAL ;
    PORT
      LAYER Metal3 ;
        RECT  0 200.98 0.4 201.38 ;
    END
  END window_i[154]
  PIN window_i[155]
    DIRECTION INPUT ;
    USE SIGNAL ;
    PORT
      LAYER Metal3 ;
        RECT  0 199.3 0.4 199.7 ;
    END
  END window_i[155]
  PIN window_i[156]
    DIRECTION INPUT ;
    USE SIGNAL ;
    PORT
      LAYER Metal3 ;
        RECT  0 197.62 0.4 198.02 ;
    END
  END window_i[156]
  PIN window_i[157]
    DIRECTION INPUT ;
    USE SIGNAL ;
    PORT
      LAYER Metal3 ;
        RECT  0 195.94 0.4 196.34 ;
    END
  END window_i[157]
  PIN window_i[158]
    DIRECTION INPUT ;
    USE SIGNAL ;
    PORT
      LAYER Metal3 ;
        RECT  0 194.26 0.4 194.66 ;
    END
  END window_i[158]
  PIN window_i[159]
    DIRECTION INPUT ;
    USE SIGNAL ;
    PORT
      LAYER Metal3 ;
        RECT  0 192.58 0.4 192.98 ;
    END
  END window_i[159]
  PIN window_i[15]
    DIRECTION INPUT ;
    USE SIGNAL ;
    PORT
      LAYER Metal3 ;
        RECT  0 434.5 0.4 434.9 ;
    END
  END window_i[15]
  PIN window_i[160]
    DIRECTION INPUT ;
    USE SIGNAL ;
    PORT
      LAYER Metal3 ;
        RECT  0 190.9 0.4 191.3 ;
    END
  END window_i[160]
  PIN window_i[161]
    DIRECTION INPUT ;
    USE SIGNAL ;
    PORT
      LAYER Metal3 ;
        RECT  0 189.22 0.4 189.62 ;
    END
  END window_i[161]
  PIN window_i[162]
    DIRECTION INPUT ;
    USE SIGNAL ;
    PORT
      LAYER Metal3 ;
        RECT  0 187.54 0.4 187.94 ;
    END
  END window_i[162]
  PIN window_i[163]
    DIRECTION INPUT ;
    USE SIGNAL ;
    PORT
      LAYER Metal3 ;
        RECT  0 185.86 0.4 186.26 ;
    END
  END window_i[163]
  PIN window_i[164]
    DIRECTION INPUT ;
    USE SIGNAL ;
    PORT
      LAYER Metal3 ;
        RECT  0 184.18 0.4 184.58 ;
    END
  END window_i[164]
  PIN window_i[165]
    DIRECTION INPUT ;
    USE SIGNAL ;
    PORT
      LAYER Metal3 ;
        RECT  0 182.5 0.4 182.9 ;
    END
  END window_i[165]
  PIN window_i[166]
    DIRECTION INPUT ;
    USE SIGNAL ;
    PORT
      LAYER Metal3 ;
        RECT  0 180.82 0.4 181.22 ;
    END
  END window_i[166]
  PIN window_i[167]
    DIRECTION INPUT ;
    USE SIGNAL ;
    PORT
      LAYER Metal3 ;
        RECT  0 179.14 0.4 179.54 ;
    END
  END window_i[167]
  PIN window_i[168]
    DIRECTION INPUT ;
    USE SIGNAL ;
    PORT
      LAYER Metal3 ;
        RECT  0 177.46 0.4 177.86 ;
    END
  END window_i[168]
  PIN window_i[169]
    DIRECTION INPUT ;
    USE SIGNAL ;
    PORT
      LAYER Metal3 ;
        RECT  0 175.78 0.4 176.18 ;
    END
  END window_i[169]
  PIN window_i[16]
    DIRECTION INPUT ;
    USE SIGNAL ;
    PORT
      LAYER Metal3 ;
        RECT  0 432.82 0.4 433.22 ;
    END
  END window_i[16]
  PIN window_i[170]
    DIRECTION INPUT ;
    USE SIGNAL ;
    PORT
      LAYER Metal3 ;
        RECT  0 174.1 0.4 174.5 ;
    END
  END window_i[170]
  PIN window_i[171]
    DIRECTION INPUT ;
    USE SIGNAL ;
    PORT
      LAYER Metal3 ;
        RECT  0 172.42 0.4 172.82 ;
    END
  END window_i[171]
  PIN window_i[172]
    DIRECTION INPUT ;
    USE SIGNAL ;
    PORT
      LAYER Metal3 ;
        RECT  0 170.74 0.4 171.14 ;
    END
  END window_i[172]
  PIN window_i[173]
    DIRECTION INPUT ;
    USE SIGNAL ;
    PORT
      LAYER Metal3 ;
        RECT  0 169.06 0.4 169.46 ;
    END
  END window_i[173]
  PIN window_i[174]
    DIRECTION INPUT ;
    USE SIGNAL ;
    PORT
      LAYER Metal3 ;
        RECT  0 167.38 0.4 167.78 ;
    END
  END window_i[174]
  PIN window_i[175]
    DIRECTION INPUT ;
    USE SIGNAL ;
    PORT
      LAYER Metal3 ;
        RECT  0 165.7 0.4 166.1 ;
    END
  END window_i[175]
  PIN window_i[176]
    DIRECTION INPUT ;
    USE SIGNAL ;
    PORT
      LAYER Metal3 ;
        RECT  0 164.02 0.4 164.42 ;
    END
  END window_i[176]
  PIN window_i[177]
    DIRECTION INPUT ;
    USE SIGNAL ;
    PORT
      LAYER Metal3 ;
        RECT  0 162.34 0.4 162.74 ;
    END
  END window_i[177]
  PIN window_i[178]
    DIRECTION INPUT ;
    USE SIGNAL ;
    PORT
      LAYER Metal3 ;
        RECT  0 160.66 0.4 161.06 ;
    END
  END window_i[178]
  PIN window_i[179]
    DIRECTION INPUT ;
    USE SIGNAL ;
    PORT
      LAYER Metal3 ;
        RECT  0 158.98 0.4 159.38 ;
    END
  END window_i[179]
  PIN window_i[17]
    DIRECTION INPUT ;
    USE SIGNAL ;
    PORT
      LAYER Metal3 ;
        RECT  0 431.14 0.4 431.54 ;
    END
  END window_i[17]
  PIN window_i[180]
    DIRECTION INPUT ;
    USE SIGNAL ;
    PORT
      LAYER Metal3 ;
        RECT  0 157.3 0.4 157.7 ;
    END
  END window_i[180]
  PIN window_i[181]
    DIRECTION INPUT ;
    USE SIGNAL ;
    PORT
      LAYER Metal3 ;
        RECT  0 155.62 0.4 156.02 ;
    END
  END window_i[181]
  PIN window_i[182]
    DIRECTION INPUT ;
    USE SIGNAL ;
    PORT
      LAYER Metal3 ;
        RECT  0 153.94 0.4 154.34 ;
    END
  END window_i[182]
  PIN window_i[183]
    DIRECTION INPUT ;
    USE SIGNAL ;
    PORT
      LAYER Metal3 ;
        RECT  0 152.26 0.4 152.66 ;
    END
  END window_i[183]
  PIN window_i[184]
    DIRECTION INPUT ;
    USE SIGNAL ;
    PORT
      LAYER Metal3 ;
        RECT  0 150.58 0.4 150.98 ;
    END
  END window_i[184]
  PIN window_i[185]
    DIRECTION INPUT ;
    USE SIGNAL ;
    PORT
      LAYER Metal3 ;
        RECT  0 148.9 0.4 149.3 ;
    END
  END window_i[185]
  PIN window_i[186]
    DIRECTION INPUT ;
    USE SIGNAL ;
    PORT
      LAYER Metal3 ;
        RECT  0 147.22 0.4 147.62 ;
    END
  END window_i[186]
  PIN window_i[187]
    DIRECTION INPUT ;
    USE SIGNAL ;
    PORT
      LAYER Metal3 ;
        RECT  0 145.54 0.4 145.94 ;
    END
  END window_i[187]
  PIN window_i[188]
    DIRECTION INPUT ;
    USE SIGNAL ;
    PORT
      LAYER Metal3 ;
        RECT  0 143.86 0.4 144.26 ;
    END
  END window_i[188]
  PIN window_i[189]
    DIRECTION INPUT ;
    USE SIGNAL ;
    PORT
      LAYER Metal3 ;
        RECT  0 142.18 0.4 142.58 ;
    END
  END window_i[189]
  PIN window_i[18]
    DIRECTION INPUT ;
    USE SIGNAL ;
    PORT
      LAYER Metal3 ;
        RECT  0 429.46 0.4 429.86 ;
    END
  END window_i[18]
  PIN window_i[190]
    DIRECTION INPUT ;
    USE SIGNAL ;
    PORT
      LAYER Metal3 ;
        RECT  0 140.5 0.4 140.9 ;
    END
  END window_i[190]
  PIN window_i[191]
    DIRECTION INPUT ;
    USE SIGNAL ;
    PORT
      LAYER Metal3 ;
        RECT  0 138.82 0.4 139.22 ;
    END
  END window_i[191]
  PIN window_i[192]
    DIRECTION INPUT ;
    USE SIGNAL ;
    PORT
      LAYER Metal3 ;
        RECT  0 137.14 0.4 137.54 ;
    END
  END window_i[192]
  PIN window_i[193]
    DIRECTION INPUT ;
    USE SIGNAL ;
    PORT
      LAYER Metal3 ;
        RECT  0 135.46 0.4 135.86 ;
    END
  END window_i[193]
  PIN window_i[194]
    DIRECTION INPUT ;
    USE SIGNAL ;
    PORT
      LAYER Metal3 ;
        RECT  0 133.78 0.4 134.18 ;
    END
  END window_i[194]
  PIN window_i[195]
    DIRECTION INPUT ;
    USE SIGNAL ;
    PORT
      LAYER Metal3 ;
        RECT  0 132.1 0.4 132.5 ;
    END
  END window_i[195]
  PIN window_i[196]
    DIRECTION INPUT ;
    USE SIGNAL ;
    PORT
      LAYER Metal3 ;
        RECT  0 130.42 0.4 130.82 ;
    END
  END window_i[196]
  PIN window_i[197]
    DIRECTION INPUT ;
    USE SIGNAL ;
    PORT
      LAYER Metal3 ;
        RECT  0 128.74 0.4 129.14 ;
    END
  END window_i[197]
  PIN window_i[198]
    DIRECTION INPUT ;
    USE SIGNAL ;
    PORT
      LAYER Metal3 ;
        RECT  0 127.06 0.4 127.46 ;
    END
  END window_i[198]
  PIN window_i[199]
    DIRECTION INPUT ;
    USE SIGNAL ;
    PORT
      LAYER Metal3 ;
        RECT  0 125.38 0.4 125.78 ;
    END
  END window_i[199]
  PIN window_i[19]
    DIRECTION INPUT ;
    USE SIGNAL ;
    PORT
      LAYER Metal3 ;
        RECT  0 427.78 0.4 428.18 ;
    END
  END window_i[19]
  PIN window_i[1]
    DIRECTION INPUT ;
    USE SIGNAL ;
    PORT
      LAYER Metal3 ;
        RECT  0 458.02 0.4 458.42 ;
    END
  END window_i[1]
  PIN window_i[200]
    DIRECTION INPUT ;
    USE SIGNAL ;
    PORT
      LAYER Metal3 ;
        RECT  0 123.7 0.4 124.1 ;
    END
  END window_i[200]
  PIN window_i[201]
    DIRECTION INPUT ;
    USE SIGNAL ;
    PORT
      LAYER Metal3 ;
        RECT  0 122.02 0.4 122.42 ;
    END
  END window_i[201]
  PIN window_i[202]
    DIRECTION INPUT ;
    USE SIGNAL ;
    PORT
      LAYER Metal3 ;
        RECT  0 120.34 0.4 120.74 ;
    END
  END window_i[202]
  PIN window_i[203]
    DIRECTION INPUT ;
    USE SIGNAL ;
    PORT
      LAYER Metal3 ;
        RECT  0 118.66 0.4 119.06 ;
    END
  END window_i[203]
  PIN window_i[204]
    DIRECTION INPUT ;
    USE SIGNAL ;
    PORT
      LAYER Metal3 ;
        RECT  0 116.98 0.4 117.38 ;
    END
  END window_i[204]
  PIN window_i[205]
    DIRECTION INPUT ;
    USE SIGNAL ;
    PORT
      LAYER Metal3 ;
        RECT  0 115.3 0.4 115.7 ;
    END
  END window_i[205]
  PIN window_i[206]
    DIRECTION INPUT ;
    USE SIGNAL ;
    PORT
      LAYER Metal3 ;
        RECT  0 113.62 0.4 114.02 ;
    END
  END window_i[206]
  PIN window_i[207]
    DIRECTION INPUT ;
    USE SIGNAL ;
    PORT
      LAYER Metal3 ;
        RECT  0 111.94 0.4 112.34 ;
    END
  END window_i[207]
  PIN window_i[208]
    DIRECTION INPUT ;
    USE SIGNAL ;
    PORT
      LAYER Metal3 ;
        RECT  0 110.26 0.4 110.66 ;
    END
  END window_i[208]
  PIN window_i[209]
    DIRECTION INPUT ;
    USE SIGNAL ;
    PORT
      LAYER Metal3 ;
        RECT  0 108.58 0.4 108.98 ;
    END
  END window_i[209]
  PIN window_i[20]
    DIRECTION INPUT ;
    USE SIGNAL ;
    PORT
      LAYER Metal3 ;
        RECT  0 426.1 0.4 426.5 ;
    END
  END window_i[20]
  PIN window_i[210]
    DIRECTION INPUT ;
    USE SIGNAL ;
    PORT
      LAYER Metal3 ;
        RECT  0 106.9 0.4 107.3 ;
    END
  END window_i[210]
  PIN window_i[211]
    DIRECTION INPUT ;
    USE SIGNAL ;
    PORT
      LAYER Metal3 ;
        RECT  0 105.22 0.4 105.62 ;
    END
  END window_i[211]
  PIN window_i[212]
    DIRECTION INPUT ;
    USE SIGNAL ;
    PORT
      LAYER Metal3 ;
        RECT  0 103.54 0.4 103.94 ;
    END
  END window_i[212]
  PIN window_i[213]
    DIRECTION INPUT ;
    USE SIGNAL ;
    PORT
      LAYER Metal3 ;
        RECT  0 101.86 0.4 102.26 ;
    END
  END window_i[213]
  PIN window_i[214]
    DIRECTION INPUT ;
    USE SIGNAL ;
    PORT
      LAYER Metal3 ;
        RECT  0 100.18 0.4 100.58 ;
    END
  END window_i[214]
  PIN window_i[215]
    DIRECTION INPUT ;
    USE SIGNAL ;
    PORT
      LAYER Metal3 ;
        RECT  0 98.5 0.4 98.9 ;
    END
  END window_i[215]
  PIN window_i[216]
    DIRECTION INPUT ;
    USE SIGNAL ;
    PORT
      LAYER Metal3 ;
        RECT  0 96.82 0.4 97.22 ;
    END
  END window_i[216]
  PIN window_i[217]
    DIRECTION INPUT ;
    USE SIGNAL ;
    PORT
      LAYER Metal3 ;
        RECT  0 95.14 0.4 95.54 ;
    END
  END window_i[217]
  PIN window_i[218]
    DIRECTION INPUT ;
    USE SIGNAL ;
    PORT
      LAYER Metal3 ;
        RECT  0 93.46 0.4 93.86 ;
    END
  END window_i[218]
  PIN window_i[219]
    DIRECTION INPUT ;
    USE SIGNAL ;
    PORT
      LAYER Metal3 ;
        RECT  0 91.78 0.4 92.18 ;
    END
  END window_i[219]
  PIN window_i[21]
    DIRECTION INPUT ;
    USE SIGNAL ;
    PORT
      LAYER Metal3 ;
        RECT  0 424.42 0.4 424.82 ;
    END
  END window_i[21]
  PIN window_i[220]
    DIRECTION INPUT ;
    USE SIGNAL ;
    PORT
      LAYER Metal3 ;
        RECT  0 90.1 0.4 90.5 ;
    END
  END window_i[220]
  PIN window_i[221]
    DIRECTION INPUT ;
    USE SIGNAL ;
    PORT
      LAYER Metal3 ;
        RECT  0 88.42 0.4 88.82 ;
    END
  END window_i[221]
  PIN window_i[222]
    DIRECTION INPUT ;
    USE SIGNAL ;
    PORT
      LAYER Metal3 ;
        RECT  0 86.74 0.4 87.14 ;
    END
  END window_i[222]
  PIN window_i[223]
    DIRECTION INPUT ;
    USE SIGNAL ;
    PORT
      LAYER Metal3 ;
        RECT  0 85.06 0.4 85.46 ;
    END
  END window_i[223]
  PIN window_i[224]
    DIRECTION INPUT ;
    USE SIGNAL ;
    PORT
      LAYER Metal3 ;
        RECT  0 83.38 0.4 83.78 ;
    END
  END window_i[224]
  PIN window_i[225]
    DIRECTION INPUT ;
    USE SIGNAL ;
    PORT
      LAYER Metal3 ;
        RECT  0 81.7 0.4 82.1 ;
    END
  END window_i[225]
  PIN window_i[226]
    DIRECTION INPUT ;
    USE SIGNAL ;
    PORT
      LAYER Metal3 ;
        RECT  0 80.02 0.4 80.42 ;
    END
  END window_i[226]
  PIN window_i[227]
    DIRECTION INPUT ;
    USE SIGNAL ;
    PORT
      LAYER Metal3 ;
        RECT  0 78.34 0.4 78.74 ;
    END
  END window_i[227]
  PIN window_i[228]
    DIRECTION INPUT ;
    USE SIGNAL ;
    PORT
      LAYER Metal3 ;
        RECT  0 76.66 0.4 77.06 ;
    END
  END window_i[228]
  PIN window_i[229]
    DIRECTION INPUT ;
    USE SIGNAL ;
    PORT
      LAYER Metal3 ;
        RECT  0 74.98 0.4 75.38 ;
    END
  END window_i[229]
  PIN window_i[22]
    DIRECTION INPUT ;
    USE SIGNAL ;
    PORT
      LAYER Metal3 ;
        RECT  0 422.74 0.4 423.14 ;
    END
  END window_i[22]
  PIN window_i[230]
    DIRECTION INPUT ;
    USE SIGNAL ;
    PORT
      LAYER Metal3 ;
        RECT  0 73.3 0.4 73.7 ;
    END
  END window_i[230]
  PIN window_i[231]
    DIRECTION INPUT ;
    USE SIGNAL ;
    PORT
      LAYER Metal3 ;
        RECT  0 71.62 0.4 72.02 ;
    END
  END window_i[231]
  PIN window_i[232]
    DIRECTION INPUT ;
    USE SIGNAL ;
    PORT
      LAYER Metal3 ;
        RECT  0 69.94 0.4 70.34 ;
    END
  END window_i[232]
  PIN window_i[233]
    DIRECTION INPUT ;
    USE SIGNAL ;
    PORT
      LAYER Metal3 ;
        RECT  0 68.26 0.4 68.66 ;
    END
  END window_i[233]
  PIN window_i[234]
    DIRECTION INPUT ;
    USE SIGNAL ;
    PORT
      LAYER Metal3 ;
        RECT  0 66.58 0.4 66.98 ;
    END
  END window_i[234]
  PIN window_i[235]
    DIRECTION INPUT ;
    USE SIGNAL ;
    PORT
      LAYER Metal3 ;
        RECT  0 64.9 0.4 65.3 ;
    END
  END window_i[235]
  PIN window_i[236]
    DIRECTION INPUT ;
    USE SIGNAL ;
    PORT
      LAYER Metal3 ;
        RECT  0 63.22 0.4 63.62 ;
    END
  END window_i[236]
  PIN window_i[237]
    DIRECTION INPUT ;
    USE SIGNAL ;
    PORT
      LAYER Metal3 ;
        RECT  0 61.54 0.4 61.94 ;
    END
  END window_i[237]
  PIN window_i[238]
    DIRECTION INPUT ;
    USE SIGNAL ;
    PORT
      LAYER Metal3 ;
        RECT  0 59.86 0.4 60.26 ;
    END
  END window_i[238]
  PIN window_i[239]
    DIRECTION INPUT ;
    USE SIGNAL ;
    PORT
      LAYER Metal3 ;
        RECT  0 58.18 0.4 58.58 ;
    END
  END window_i[239]
  PIN window_i[23]
    DIRECTION INPUT ;
    USE SIGNAL ;
    PORT
      LAYER Metal3 ;
        RECT  0 421.06 0.4 421.46 ;
    END
  END window_i[23]
  PIN window_i[240]
    DIRECTION INPUT ;
    USE SIGNAL ;
    PORT
      LAYER Metal3 ;
        RECT  0 56.5 0.4 56.9 ;
    END
  END window_i[240]
  PIN window_i[241]
    DIRECTION INPUT ;
    USE SIGNAL ;
    PORT
      LAYER Metal3 ;
        RECT  0 54.82 0.4 55.22 ;
    END
  END window_i[241]
  PIN window_i[242]
    DIRECTION INPUT ;
    USE SIGNAL ;
    PORT
      LAYER Metal3 ;
        RECT  0 53.14 0.4 53.54 ;
    END
  END window_i[242]
  PIN window_i[243]
    DIRECTION INPUT ;
    USE SIGNAL ;
    PORT
      LAYER Metal3 ;
        RECT  0 51.46 0.4 51.86 ;
    END
  END window_i[243]
  PIN window_i[244]
    DIRECTION INPUT ;
    USE SIGNAL ;
    PORT
      LAYER Metal3 ;
        RECT  0 49.78 0.4 50.18 ;
    END
  END window_i[244]
  PIN window_i[245]
    DIRECTION INPUT ;
    USE SIGNAL ;
    PORT
      LAYER Metal3 ;
        RECT  0 48.1 0.4 48.5 ;
    END
  END window_i[245]
  PIN window_i[246]
    DIRECTION INPUT ;
    USE SIGNAL ;
    PORT
      LAYER Metal3 ;
        RECT  0 46.42 0.4 46.82 ;
    END
  END window_i[246]
  PIN window_i[247]
    DIRECTION INPUT ;
    USE SIGNAL ;
    PORT
      LAYER Metal3 ;
        RECT  0 44.74 0.4 45.14 ;
    END
  END window_i[247]
  PIN window_i[248]
    DIRECTION INPUT ;
    USE SIGNAL ;
    PORT
      LAYER Metal3 ;
        RECT  0 43.06 0.4 43.46 ;
    END
  END window_i[248]
  PIN window_i[249]
    DIRECTION INPUT ;
    USE SIGNAL ;
    PORT
      LAYER Metal3 ;
        RECT  0 41.38 0.4 41.78 ;
    END
  END window_i[249]
  PIN window_i[24]
    DIRECTION INPUT ;
    USE SIGNAL ;
    PORT
      LAYER Metal3 ;
        RECT  0 419.38 0.4 419.78 ;
    END
  END window_i[24]
  PIN window_i[250]
    DIRECTION INPUT ;
    USE SIGNAL ;
    PORT
      LAYER Metal3 ;
        RECT  0 39.7 0.4 40.1 ;
    END
  END window_i[250]
  PIN window_i[251]
    DIRECTION INPUT ;
    USE SIGNAL ;
    PORT
      LAYER Metal3 ;
        RECT  0 38.02 0.4 38.42 ;
    END
  END window_i[251]
  PIN window_i[252]
    DIRECTION INPUT ;
    USE SIGNAL ;
    PORT
      LAYER Metal3 ;
        RECT  0 36.34 0.4 36.74 ;
    END
  END window_i[252]
  PIN window_i[253]
    DIRECTION INPUT ;
    USE SIGNAL ;
    PORT
      LAYER Metal3 ;
        RECT  0 34.66 0.4 35.06 ;
    END
  END window_i[253]
  PIN window_i[254]
    DIRECTION INPUT ;
    USE SIGNAL ;
    PORT
      LAYER Metal3 ;
        RECT  0 32.98 0.4 33.38 ;
    END
  END window_i[254]
  PIN window_i[255]
    DIRECTION INPUT ;
    USE SIGNAL ;
    PORT
      LAYER Metal3 ;
        RECT  0 31.3 0.4 31.7 ;
    END
  END window_i[255]
  PIN window_i[25]
    DIRECTION INPUT ;
    USE SIGNAL ;
    PORT
      LAYER Metal3 ;
        RECT  0 417.7 0.4 418.1 ;
    END
  END window_i[25]
  PIN window_i[26]
    DIRECTION INPUT ;
    USE SIGNAL ;
    PORT
      LAYER Metal3 ;
        RECT  0 416.02 0.4 416.42 ;
    END
  END window_i[26]
  PIN window_i[27]
    DIRECTION INPUT ;
    USE SIGNAL ;
    PORT
      LAYER Metal3 ;
        RECT  0 414.34 0.4 414.74 ;
    END
  END window_i[27]
  PIN window_i[28]
    DIRECTION INPUT ;
    USE SIGNAL ;
    PORT
      LAYER Metal3 ;
        RECT  0 412.66 0.4 413.06 ;
    END
  END window_i[28]
  PIN window_i[29]
    DIRECTION INPUT ;
    USE SIGNAL ;
    PORT
      LAYER Metal3 ;
        RECT  0 410.98 0.4 411.38 ;
    END
  END window_i[29]
  PIN window_i[2]
    DIRECTION INPUT ;
    USE SIGNAL ;
    PORT
      LAYER Metal3 ;
        RECT  0 456.34 0.4 456.74 ;
    END
  END window_i[2]
  PIN window_i[30]
    DIRECTION INPUT ;
    USE SIGNAL ;
    PORT
      LAYER Metal3 ;
        RECT  0 409.3 0.4 409.7 ;
    END
  END window_i[30]
  PIN window_i[31]
    DIRECTION INPUT ;
    USE SIGNAL ;
    PORT
      LAYER Metal3 ;
        RECT  0 407.62 0.4 408.02 ;
    END
  END window_i[31]
  PIN window_i[32]
    DIRECTION INPUT ;
    USE SIGNAL ;
    PORT
      LAYER Metal3 ;
        RECT  0 405.94 0.4 406.34 ;
    END
  END window_i[32]
  PIN window_i[33]
    DIRECTION INPUT ;
    USE SIGNAL ;
    PORT
      LAYER Metal3 ;
        RECT  0 404.26 0.4 404.66 ;
    END
  END window_i[33]
  PIN window_i[34]
    DIRECTION INPUT ;
    USE SIGNAL ;
    PORT
      LAYER Metal3 ;
        RECT  0 402.58 0.4 402.98 ;
    END
  END window_i[34]
  PIN window_i[35]
    DIRECTION INPUT ;
    USE SIGNAL ;
    PORT
      LAYER Metal3 ;
        RECT  0 400.9 0.4 401.3 ;
    END
  END window_i[35]
  PIN window_i[36]
    DIRECTION INPUT ;
    USE SIGNAL ;
    PORT
      LAYER Metal3 ;
        RECT  0 399.22 0.4 399.62 ;
    END
  END window_i[36]
  PIN window_i[37]
    DIRECTION INPUT ;
    USE SIGNAL ;
    PORT
      LAYER Metal3 ;
        RECT  0 397.54 0.4 397.94 ;
    END
  END window_i[37]
  PIN window_i[38]
    DIRECTION INPUT ;
    USE SIGNAL ;
    PORT
      LAYER Metal3 ;
        RECT  0 395.86 0.4 396.26 ;
    END
  END window_i[38]
  PIN window_i[39]
    DIRECTION INPUT ;
    USE SIGNAL ;
    PORT
      LAYER Metal3 ;
        RECT  0 394.18 0.4 394.58 ;
    END
  END window_i[39]
  PIN window_i[3]
    DIRECTION INPUT ;
    USE SIGNAL ;
    PORT
      LAYER Metal3 ;
        RECT  0 454.66 0.4 455.06 ;
    END
  END window_i[3]
  PIN window_i[40]
    DIRECTION INPUT ;
    USE SIGNAL ;
    PORT
      LAYER Metal3 ;
        RECT  0 392.5 0.4 392.9 ;
    END
  END window_i[40]
  PIN window_i[41]
    DIRECTION INPUT ;
    USE SIGNAL ;
    PORT
      LAYER Metal3 ;
        RECT  0 390.82 0.4 391.22 ;
    END
  END window_i[41]
  PIN window_i[42]
    DIRECTION INPUT ;
    USE SIGNAL ;
    PORT
      LAYER Metal3 ;
        RECT  0 389.14 0.4 389.54 ;
    END
  END window_i[42]
  PIN window_i[43]
    DIRECTION INPUT ;
    USE SIGNAL ;
    PORT
      LAYER Metal3 ;
        RECT  0 387.46 0.4 387.86 ;
    END
  END window_i[43]
  PIN window_i[44]
    DIRECTION INPUT ;
    USE SIGNAL ;
    PORT
      LAYER Metal3 ;
        RECT  0 385.78 0.4 386.18 ;
    END
  END window_i[44]
  PIN window_i[45]
    DIRECTION INPUT ;
    USE SIGNAL ;
    PORT
      LAYER Metal3 ;
        RECT  0 384.1 0.4 384.5 ;
    END
  END window_i[45]
  PIN window_i[46]
    DIRECTION INPUT ;
    USE SIGNAL ;
    PORT
      LAYER Metal3 ;
        RECT  0 382.42 0.4 382.82 ;
    END
  END window_i[46]
  PIN window_i[47]
    DIRECTION INPUT ;
    USE SIGNAL ;
    PORT
      LAYER Metal3 ;
        RECT  0 380.74 0.4 381.14 ;
    END
  END window_i[47]
  PIN window_i[48]
    DIRECTION INPUT ;
    USE SIGNAL ;
    PORT
      LAYER Metal3 ;
        RECT  0 379.06 0.4 379.46 ;
    END
  END window_i[48]
  PIN window_i[49]
    DIRECTION INPUT ;
    USE SIGNAL ;
    PORT
      LAYER Metal3 ;
        RECT  0 377.38 0.4 377.78 ;
    END
  END window_i[49]
  PIN window_i[4]
    DIRECTION INPUT ;
    USE SIGNAL ;
    PORT
      LAYER Metal3 ;
        RECT  0 452.98 0.4 453.38 ;
    END
  END window_i[4]
  PIN window_i[50]
    DIRECTION INPUT ;
    USE SIGNAL ;
    PORT
      LAYER Metal3 ;
        RECT  0 375.7 0.4 376.1 ;
    END
  END window_i[50]
  PIN window_i[51]
    DIRECTION INPUT ;
    USE SIGNAL ;
    PORT
      LAYER Metal3 ;
        RECT  0 374.02 0.4 374.42 ;
    END
  END window_i[51]
  PIN window_i[52]
    DIRECTION INPUT ;
    USE SIGNAL ;
    PORT
      LAYER Metal3 ;
        RECT  0 372.34 0.4 372.74 ;
    END
  END window_i[52]
  PIN window_i[53]
    DIRECTION INPUT ;
    USE SIGNAL ;
    PORT
      LAYER Metal3 ;
        RECT  0 370.66 0.4 371.06 ;
    END
  END window_i[53]
  PIN window_i[54]
    DIRECTION INPUT ;
    USE SIGNAL ;
    PORT
      LAYER Metal3 ;
        RECT  0 368.98 0.4 369.38 ;
    END
  END window_i[54]
  PIN window_i[55]
    DIRECTION INPUT ;
    USE SIGNAL ;
    PORT
      LAYER Metal3 ;
        RECT  0 367.3 0.4 367.7 ;
    END
  END window_i[55]
  PIN window_i[56]
    DIRECTION INPUT ;
    USE SIGNAL ;
    PORT
      LAYER Metal3 ;
        RECT  0 365.62 0.4 366.02 ;
    END
  END window_i[56]
  PIN window_i[57]
    DIRECTION INPUT ;
    USE SIGNAL ;
    PORT
      LAYER Metal3 ;
        RECT  0 363.94 0.4 364.34 ;
    END
  END window_i[57]
  PIN window_i[58]
    DIRECTION INPUT ;
    USE SIGNAL ;
    PORT
      LAYER Metal3 ;
        RECT  0 362.26 0.4 362.66 ;
    END
  END window_i[58]
  PIN window_i[59]
    DIRECTION INPUT ;
    USE SIGNAL ;
    PORT
      LAYER Metal3 ;
        RECT  0 360.58 0.4 360.98 ;
    END
  END window_i[59]
  PIN window_i[5]
    DIRECTION INPUT ;
    USE SIGNAL ;
    PORT
      LAYER Metal3 ;
        RECT  0 451.3 0.4 451.7 ;
    END
  END window_i[5]
  PIN window_i[60]
    DIRECTION INPUT ;
    USE SIGNAL ;
    PORT
      LAYER Metal3 ;
        RECT  0 358.9 0.4 359.3 ;
    END
  END window_i[60]
  PIN window_i[61]
    DIRECTION INPUT ;
    USE SIGNAL ;
    PORT
      LAYER Metal3 ;
        RECT  0 357.22 0.4 357.62 ;
    END
  END window_i[61]
  PIN window_i[62]
    DIRECTION INPUT ;
    USE SIGNAL ;
    PORT
      LAYER Metal3 ;
        RECT  0 355.54 0.4 355.94 ;
    END
  END window_i[62]
  PIN window_i[63]
    DIRECTION INPUT ;
    USE SIGNAL ;
    PORT
      LAYER Metal3 ;
        RECT  0 353.86 0.4 354.26 ;
    END
  END window_i[63]
  PIN window_i[64]
    DIRECTION INPUT ;
    USE SIGNAL ;
    PORT
      LAYER Metal3 ;
        RECT  0 352.18 0.4 352.58 ;
    END
  END window_i[64]
  PIN window_i[65]
    DIRECTION INPUT ;
    USE SIGNAL ;
    PORT
      LAYER Metal3 ;
        RECT  0 350.5 0.4 350.9 ;
    END
  END window_i[65]
  PIN window_i[66]
    DIRECTION INPUT ;
    USE SIGNAL ;
    PORT
      LAYER Metal3 ;
        RECT  0 348.82 0.4 349.22 ;
    END
  END window_i[66]
  PIN window_i[67]
    DIRECTION INPUT ;
    USE SIGNAL ;
    PORT
      LAYER Metal3 ;
        RECT  0 347.14 0.4 347.54 ;
    END
  END window_i[67]
  PIN window_i[68]
    DIRECTION INPUT ;
    USE SIGNAL ;
    PORT
      LAYER Metal3 ;
        RECT  0 345.46 0.4 345.86 ;
    END
  END window_i[68]
  PIN window_i[69]
    DIRECTION INPUT ;
    USE SIGNAL ;
    PORT
      LAYER Metal3 ;
        RECT  0 343.78 0.4 344.18 ;
    END
  END window_i[69]
  PIN window_i[6]
    DIRECTION INPUT ;
    USE SIGNAL ;
    PORT
      LAYER Metal3 ;
        RECT  0 449.62 0.4 450.02 ;
    END
  END window_i[6]
  PIN window_i[70]
    DIRECTION INPUT ;
    USE SIGNAL ;
    PORT
      LAYER Metal3 ;
        RECT  0 342.1 0.4 342.5 ;
    END
  END window_i[70]
  PIN window_i[71]
    DIRECTION INPUT ;
    USE SIGNAL ;
    PORT
      LAYER Metal3 ;
        RECT  0 340.42 0.4 340.82 ;
    END
  END window_i[71]
  PIN window_i[72]
    DIRECTION INPUT ;
    USE SIGNAL ;
    PORT
      LAYER Metal3 ;
        RECT  0 338.74 0.4 339.14 ;
    END
  END window_i[72]
  PIN window_i[73]
    DIRECTION INPUT ;
    USE SIGNAL ;
    PORT
      LAYER Metal3 ;
        RECT  0 337.06 0.4 337.46 ;
    END
  END window_i[73]
  PIN window_i[74]
    DIRECTION INPUT ;
    USE SIGNAL ;
    PORT
      LAYER Metal3 ;
        RECT  0 335.38 0.4 335.78 ;
    END
  END window_i[74]
  PIN window_i[75]
    DIRECTION INPUT ;
    USE SIGNAL ;
    PORT
      LAYER Metal3 ;
        RECT  0 333.7 0.4 334.1 ;
    END
  END window_i[75]
  PIN window_i[76]
    DIRECTION INPUT ;
    USE SIGNAL ;
    PORT
      LAYER Metal3 ;
        RECT  0 332.02 0.4 332.42 ;
    END
  END window_i[76]
  PIN window_i[77]
    DIRECTION INPUT ;
    USE SIGNAL ;
    PORT
      LAYER Metal3 ;
        RECT  0 330.34 0.4 330.74 ;
    END
  END window_i[77]
  PIN window_i[78]
    DIRECTION INPUT ;
    USE SIGNAL ;
    PORT
      LAYER Metal3 ;
        RECT  0 328.66 0.4 329.06 ;
    END
  END window_i[78]
  PIN window_i[79]
    DIRECTION INPUT ;
    USE SIGNAL ;
    PORT
      LAYER Metal3 ;
        RECT  0 326.98 0.4 327.38 ;
    END
  END window_i[79]
  PIN window_i[7]
    DIRECTION INPUT ;
    USE SIGNAL ;
    PORT
      LAYER Metal3 ;
        RECT  0 447.94 0.4 448.34 ;
    END
  END window_i[7]
  PIN window_i[80]
    DIRECTION INPUT ;
    USE SIGNAL ;
    PORT
      LAYER Metal3 ;
        RECT  0 325.3 0.4 325.7 ;
    END
  END window_i[80]
  PIN window_i[81]
    DIRECTION INPUT ;
    USE SIGNAL ;
    PORT
      LAYER Metal3 ;
        RECT  0 323.62 0.4 324.02 ;
    END
  END window_i[81]
  PIN window_i[82]
    DIRECTION INPUT ;
    USE SIGNAL ;
    PORT
      LAYER Metal3 ;
        RECT  0 321.94 0.4 322.34 ;
    END
  END window_i[82]
  PIN window_i[83]
    DIRECTION INPUT ;
    USE SIGNAL ;
    PORT
      LAYER Metal3 ;
        RECT  0 320.26 0.4 320.66 ;
    END
  END window_i[83]
  PIN window_i[84]
    DIRECTION INPUT ;
    USE SIGNAL ;
    PORT
      LAYER Metal3 ;
        RECT  0 318.58 0.4 318.98 ;
    END
  END window_i[84]
  PIN window_i[85]
    DIRECTION INPUT ;
    USE SIGNAL ;
    PORT
      LAYER Metal3 ;
        RECT  0 316.9 0.4 317.3 ;
    END
  END window_i[85]
  PIN window_i[86]
    DIRECTION INPUT ;
    USE SIGNAL ;
    PORT
      LAYER Metal3 ;
        RECT  0 315.22 0.4 315.62 ;
    END
  END window_i[86]
  PIN window_i[87]
    DIRECTION INPUT ;
    USE SIGNAL ;
    PORT
      LAYER Metal3 ;
        RECT  0 313.54 0.4 313.94 ;
    END
  END window_i[87]
  PIN window_i[88]
    DIRECTION INPUT ;
    USE SIGNAL ;
    PORT
      LAYER Metal3 ;
        RECT  0 311.86 0.4 312.26 ;
    END
  END window_i[88]
  PIN window_i[89]
    DIRECTION INPUT ;
    USE SIGNAL ;
    PORT
      LAYER Metal3 ;
        RECT  0 310.18 0.4 310.58 ;
    END
  END window_i[89]
  PIN window_i[8]
    DIRECTION INPUT ;
    USE SIGNAL ;
    PORT
      LAYER Metal3 ;
        RECT  0 446.26 0.4 446.66 ;
    END
  END window_i[8]
  PIN window_i[90]
    DIRECTION INPUT ;
    USE SIGNAL ;
    PORT
      LAYER Metal3 ;
        RECT  0 308.5 0.4 308.9 ;
    END
  END window_i[90]
  PIN window_i[91]
    DIRECTION INPUT ;
    USE SIGNAL ;
    PORT
      LAYER Metal3 ;
        RECT  0 306.82 0.4 307.22 ;
    END
  END window_i[91]
  PIN window_i[92]
    DIRECTION INPUT ;
    USE SIGNAL ;
    PORT
      LAYER Metal3 ;
        RECT  0 305.14 0.4 305.54 ;
    END
  END window_i[92]
  PIN window_i[93]
    DIRECTION INPUT ;
    USE SIGNAL ;
    PORT
      LAYER Metal3 ;
        RECT  0 303.46 0.4 303.86 ;
    END
  END window_i[93]
  PIN window_i[94]
    DIRECTION INPUT ;
    USE SIGNAL ;
    PORT
      LAYER Metal3 ;
        RECT  0 301.78 0.4 302.18 ;
    END
  END window_i[94]
  PIN window_i[95]
    DIRECTION INPUT ;
    USE SIGNAL ;
    PORT
      LAYER Metal3 ;
        RECT  0 300.1 0.4 300.5 ;
    END
  END window_i[95]
  PIN window_i[96]
    DIRECTION INPUT ;
    USE SIGNAL ;
    PORT
      LAYER Metal3 ;
        RECT  0 298.42 0.4 298.82 ;
    END
  END window_i[96]
  PIN window_i[97]
    DIRECTION INPUT ;
    USE SIGNAL ;
    PORT
      LAYER Metal3 ;
        RECT  0 296.74 0.4 297.14 ;
    END
  END window_i[97]
  PIN window_i[98]
    DIRECTION INPUT ;
    USE SIGNAL ;
    PORT
      LAYER Metal3 ;
        RECT  0 295.06 0.4 295.46 ;
    END
  END window_i[98]
  PIN window_i[99]
    DIRECTION INPUT ;
    USE SIGNAL ;
    PORT
      LAYER Metal3 ;
        RECT  0 293.38 0.4 293.78 ;
    END
  END window_i[99]
  PIN window_i[9]
    DIRECTION INPUT ;
    USE SIGNAL ;
    PORT
      LAYER Metal3 ;
        RECT  0 444.58 0.4 444.98 ;
    END
  END window_i[9]
  PIN window_pc_i[0]
    DIRECTION INPUT ;
    USE SIGNAL ;
    PORT
      LAYER Metal3 ;
        RECT  0 728.5 0.4 728.9 ;
    END
  END window_pc_i[0]
  PIN window_pc_i[10]
    DIRECTION INPUT ;
    USE SIGNAL ;
    PORT
      LAYER Metal3 ;
        RECT  0 711.7 0.4 712.1 ;
    END
  END window_pc_i[10]
  PIN window_pc_i[11]
    DIRECTION INPUT ;
    USE SIGNAL ;
    PORT
      LAYER Metal3 ;
        RECT  0 710.02 0.4 710.42 ;
    END
  END window_pc_i[11]
  PIN window_pc_i[12]
    DIRECTION INPUT ;
    USE SIGNAL ;
    PORT
      LAYER Metal3 ;
        RECT  0 708.34 0.4 708.74 ;
    END
  END window_pc_i[12]
  PIN window_pc_i[13]
    DIRECTION INPUT ;
    USE SIGNAL ;
    PORT
      LAYER Metal3 ;
        RECT  0 706.66 0.4 707.06 ;
    END
  END window_pc_i[13]
  PIN window_pc_i[14]
    DIRECTION INPUT ;
    USE SIGNAL ;
    PORT
      LAYER Metal3 ;
        RECT  0 704.98 0.4 705.38 ;
    END
  END window_pc_i[14]
  PIN window_pc_i[15]
    DIRECTION INPUT ;
    USE SIGNAL ;
    PORT
      LAYER Metal3 ;
        RECT  0 703.3 0.4 703.7 ;
    END
  END window_pc_i[15]
  PIN window_pc_i[16]
    DIRECTION INPUT ;
    USE SIGNAL ;
    PORT
      LAYER Metal3 ;
        RECT  0 701.62 0.4 702.02 ;
    END
  END window_pc_i[16]
  PIN window_pc_i[17]
    DIRECTION INPUT ;
    USE SIGNAL ;
    PORT
      LAYER Metal3 ;
        RECT  0 699.94 0.4 700.34 ;
    END
  END window_pc_i[17]
  PIN window_pc_i[18]
    DIRECTION INPUT ;
    USE SIGNAL ;
    PORT
      LAYER Metal3 ;
        RECT  0 698.26 0.4 698.66 ;
    END
  END window_pc_i[18]
  PIN window_pc_i[19]
    DIRECTION INPUT ;
    USE SIGNAL ;
    PORT
      LAYER Metal3 ;
        RECT  0 696.58 0.4 696.98 ;
    END
  END window_pc_i[19]
  PIN window_pc_i[1]
    DIRECTION INPUT ;
    USE SIGNAL ;
    PORT
      LAYER Metal3 ;
        RECT  0 726.82 0.4 727.22 ;
    END
  END window_pc_i[1]
  PIN window_pc_i[20]
    DIRECTION INPUT ;
    USE SIGNAL ;
    PORT
      LAYER Metal3 ;
        RECT  0 694.9 0.4 695.3 ;
    END
  END window_pc_i[20]
  PIN window_pc_i[21]
    DIRECTION INPUT ;
    USE SIGNAL ;
    PORT
      LAYER Metal3 ;
        RECT  0 693.22 0.4 693.62 ;
    END
  END window_pc_i[21]
  PIN window_pc_i[22]
    DIRECTION INPUT ;
    USE SIGNAL ;
    PORT
      LAYER Metal3 ;
        RECT  0 691.54 0.4 691.94 ;
    END
  END window_pc_i[22]
  PIN window_pc_i[23]
    DIRECTION INPUT ;
    USE SIGNAL ;
    PORT
      LAYER Metal3 ;
        RECT  0 689.86 0.4 690.26 ;
    END
  END window_pc_i[23]
  PIN window_pc_i[24]
    DIRECTION INPUT ;
    USE SIGNAL ;
    PORT
      LAYER Metal3 ;
        RECT  0 688.18 0.4 688.58 ;
    END
  END window_pc_i[24]
  PIN window_pc_i[25]
    DIRECTION INPUT ;
    USE SIGNAL ;
    PORT
      LAYER Metal3 ;
        RECT  0 686.5 0.4 686.9 ;
    END
  END window_pc_i[25]
  PIN window_pc_i[26]
    DIRECTION INPUT ;
    USE SIGNAL ;
    PORT
      LAYER Metal3 ;
        RECT  0 684.82 0.4 685.22 ;
    END
  END window_pc_i[26]
  PIN window_pc_i[27]
    DIRECTION INPUT ;
    USE SIGNAL ;
    PORT
      LAYER Metal3 ;
        RECT  0 683.14 0.4 683.54 ;
    END
  END window_pc_i[27]
  PIN window_pc_i[28]
    DIRECTION INPUT ;
    USE SIGNAL ;
    PORT
      LAYER Metal3 ;
        RECT  0 681.46 0.4 681.86 ;
    END
  END window_pc_i[28]
  PIN window_pc_i[29]
    DIRECTION INPUT ;
    USE SIGNAL ;
    PORT
      LAYER Metal3 ;
        RECT  0 679.78 0.4 680.18 ;
    END
  END window_pc_i[29]
  PIN window_pc_i[2]
    DIRECTION INPUT ;
    USE SIGNAL ;
    PORT
      LAYER Metal3 ;
        RECT  0 725.14 0.4 725.54 ;
    END
  END window_pc_i[2]
  PIN window_pc_i[30]
    DIRECTION INPUT ;
    USE SIGNAL ;
    PORT
      LAYER Metal3 ;
        RECT  0 678.1 0.4 678.5 ;
    END
  END window_pc_i[30]
  PIN window_pc_i[31]
    DIRECTION INPUT ;
    USE SIGNAL ;
    PORT
      LAYER Metal3 ;
        RECT  0 676.42 0.4 676.82 ;
    END
  END window_pc_i[31]
  PIN window_pc_i[3]
    DIRECTION INPUT ;
    USE SIGNAL ;
    PORT
      LAYER Metal3 ;
        RECT  0 723.46 0.4 723.86 ;
    END
  END window_pc_i[3]
  PIN window_pc_i[4]
    DIRECTION INPUT ;
    USE SIGNAL ;
    PORT
      LAYER Metal3 ;
        RECT  0 721.78 0.4 722.18 ;
    END
  END window_pc_i[4]
  PIN window_pc_i[5]
    DIRECTION INPUT ;
    USE SIGNAL ;
    PORT
      LAYER Metal3 ;
        RECT  0 720.1 0.4 720.5 ;
    END
  END window_pc_i[5]
  PIN window_pc_i[6]
    DIRECTION INPUT ;
    USE SIGNAL ;
    PORT
      LAYER Metal3 ;
        RECT  0 718.42 0.4 718.82 ;
    END
  END window_pc_i[6]
  PIN window_pc_i[7]
    DIRECTION INPUT ;
    USE SIGNAL ;
    PORT
      LAYER Metal3 ;
        RECT  0 716.74 0.4 717.14 ;
    END
  END window_pc_i[7]
  PIN window_pc_i[8]
    DIRECTION INPUT ;
    USE SIGNAL ;
    PORT
      LAYER Metal3 ;
        RECT  0 715.06 0.4 715.46 ;
    END
  END window_pc_i[8]
  PIN window_pc_i[9]
    DIRECTION INPUT ;
    USE SIGNAL ;
    PORT
      LAYER Metal3 ;
        RECT  0 713.38 0.4 713.78 ;
    END
  END window_pc_i[9]
  PIN VPWR
    DIRECTION INOUT ;
    USE POWER ;
    PORT
      LAYER TopMetal1 ;
        RECT  5.76 1074.12 1093.92 1076.12 ;
        RECT  5.76 1024.12 1093.92 1026.12 ;
        RECT  5.76 974.12 1093.92 976.12 ;
        RECT  5.76 924.12 1093.92 926.12 ;
        RECT  5.76 874.12 1093.92 876.12 ;
        RECT  5.76 824.12 1093.92 826.12 ;
        RECT  5.76 774.12 1093.92 776.12 ;
        RECT  5.76 724.12 1093.92 726.12 ;
        RECT  5.76 674.12 1093.92 676.12 ;
        RECT  5.76 624.12 1093.92 626.12 ;
        RECT  5.76 574.12 1093.92 576.12 ;
        RECT  5.76 524.12 1093.92 526.12 ;
        RECT  5.76 474.12 1093.92 476.12 ;
        RECT  5.76 424.12 1093.92 426.12 ;
        RECT  5.76 374.12 1093.92 376.12 ;
        RECT  5.76 324.12 1093.92 326.12 ;
        RECT  5.76 274.12 1093.92 276.12 ;
        RECT  5.76 224.12 1093.92 226.12 ;
        RECT  5.76 174.12 1093.92 176.12 ;
        RECT  5.76 124.12 1093.92 126.12 ;
        RECT  5.76 74.12 1093.92 76.12 ;
        RECT  5.76 24.12 1093.92 26.12 ;
      LAYER Metal4 ;
        RECT  1065.26 14.9 1066.26 1085.08 ;
        RECT  1015.26 14.9 1016.26 1085.08 ;
        RECT  965.26 14.9 966.26 1085.08 ;
        RECT  915.26 14.9 916.26 1085.08 ;
        RECT  865.26 14.9 866.26 1085.08 ;
        RECT  815.26 14.9 816.26 1085.08 ;
        RECT  765.26 14.9 766.26 1085.08 ;
        RECT  715.26 14.9 716.26 1085.08 ;
        RECT  665.26 14.9 666.26 1085.08 ;
        RECT  615.26 14.9 616.26 1085.08 ;
        RECT  565.26 14.9 566.26 1085.08 ;
        RECT  515.26 14.9 516.26 1085.08 ;
        RECT  465.26 14.9 466.26 1085.08 ;
        RECT  415.26 14.9 416.26 1085.08 ;
        RECT  365.26 14.9 366.26 1085.08 ;
        RECT  315.26 14.9 316.26 1085.08 ;
        RECT  265.26 14.9 266.26 1085.08 ;
        RECT  215.26 14.9 216.26 1085.08 ;
        RECT  165.26 14.9 166.26 1085.08 ;
        RECT  115.26 14.9 116.26 1085.08 ;
        RECT  65.26 14.9 66.26 1085.08 ;
        RECT  15.26 14.9 16.26 1085.08 ;
    END
  END VPWR
  PIN VGND
    DIRECTION INOUT ;
    USE GROUND ;
    PORT
      LAYER TopMetal1 ;
        RECT  5.76 1080.12 1093.92 1082.12 ;
        RECT  5.76 1030.12 1093.92 1032.12 ;
        RECT  5.76 980.12 1093.92 982.12 ;
        RECT  5.76 930.12 1093.92 932.12 ;
        RECT  5.76 880.12 1093.92 882.12 ;
        RECT  5.76 830.12 1093.92 832.12 ;
        RECT  5.76 780.12 1093.92 782.12 ;
        RECT  5.76 730.12 1093.92 732.12 ;
        RECT  5.76 680.12 1093.92 682.12 ;
        RECT  5.76 630.12 1093.92 632.12 ;
        RECT  5.76 580.12 1093.92 582.12 ;
        RECT  5.76 530.12 1093.92 532.12 ;
        RECT  5.76 480.12 1093.92 482.12 ;
        RECT  5.76 430.12 1093.92 432.12 ;
        RECT  5.76 380.12 1093.92 382.12 ;
        RECT  5.76 330.12 1093.92 332.12 ;
        RECT  5.76 280.12 1093.92 282.12 ;
        RECT  5.76 230.12 1093.92 232.12 ;
        RECT  5.76 180.12 1093.92 182.12 ;
        RECT  5.76 130.12 1093.92 132.12 ;
        RECT  5.76 80.12 1093.92 82.12 ;
        RECT  5.76 30.12 1093.92 32.12 ;
      LAYER Metal4 ;
        RECT  1068.26 14.9 1069.26 1085.08 ;
        RECT  1018.26 14.9 1019.26 1085.08 ;
        RECT  968.26 14.9 969.26 1085.08 ;
        RECT  918.26 14.9 919.26 1085.08 ;
        RECT  868.26 14.9 869.26 1085.08 ;
        RECT  818.26 14.9 819.26 1085.08 ;
        RECT  768.26 14.9 769.26 1085.08 ;
        RECT  718.26 14.9 719.26 1085.08 ;
        RECT  668.26 14.9 669.26 1085.08 ;
        RECT  618.26 14.9 619.26 1085.08 ;
        RECT  568.26 14.9 569.26 1085.08 ;
        RECT  518.26 14.9 519.26 1085.08 ;
        RECT  468.26 14.9 469.26 1085.08 ;
        RECT  418.26 14.9 419.26 1085.08 ;
        RECT  368.26 14.9 369.26 1085.08 ;
        RECT  318.26 14.9 319.26 1085.08 ;
        RECT  268.26 14.9 269.26 1085.08 ;
        RECT  218.26 14.9 219.26 1085.08 ;
        RECT  168.26 14.9 169.26 1085.08 ;
        RECT  118.26 14.9 119.26 1085.08 ;
        RECT  68.26 14.9 69.26 1085.08 ;
        RECT  18.26 14.9 19.26 1085.08 ;
    END
  END VGND
  OBS
    LAYER Metal1 ;
     RECT  0 0 1100 1100 ;
    LAYER Metal2 ;
     RECT  0 0 1100 1100 ;
    LAYER Metal3 ;
     RECT  0 0 1100 1100 ;
    LAYER Metal4 ;
     RECT  0 0 1100 1100 ;
    LAYER TopMetal1 ;
     RECT  0 0 1100 1100 ;
  END
END ino_decode_predict
END LIBRARY
